VERSION 5.8 ;
BUSBITCHARS "[]" ;
DIVIDERCHAR "/" ;
UNITS
    DATABASE MICRONS 1000 ;
END UNITS

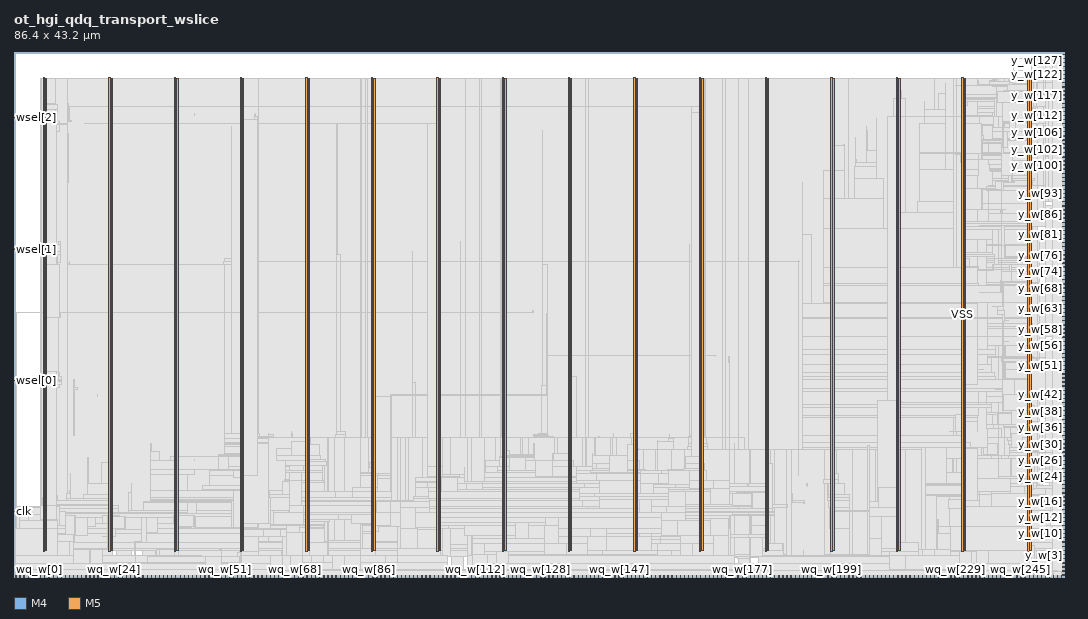
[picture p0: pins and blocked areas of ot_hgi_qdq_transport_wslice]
MACRO ot_hgi_qdq_transport_wslice
  FOREIGN ot_hgi_qdq_transport_wslice 0 0 ;
  CLASS BLOCK ;
  SIZE 86.4 BY 43.2 ;
  PIN clk
    DIRECTION INPUT ;
    USE SIGNAL ;
    PORT
      LAYER M4 ;
        RECT  0 5.376 0.084 5.4 ;
    END
    PORT
      LAYER M4 ;
        RECT  0.06 5.376 0.469 5.4 ;
    END
  END clk
  PIN wq_w[0]
    DIRECTION OUTPUT ;
    USE SIGNAL ;
    PORT
      LAYER M5 ;
        RECT  0.144 0 0.168 0.084 ;
    END
  END wq_w[0]
  PIN wq_w[100]
    DIRECTION OUTPUT ;
    USE SIGNAL ;
    PORT
      LAYER M5 ;
        RECT  33.888 0 33.912 0.084 ;
    END
  END wq_w[100]
  PIN wq_w[101]
    DIRECTION OUTPUT ;
    USE SIGNAL ;
    PORT
      LAYER M5 ;
        RECT  34.224 0 34.248 0.084 ;
    END
  END wq_w[101]
  PIN wq_w[102]
    DIRECTION OUTPUT ;
    USE SIGNAL ;
    PORT
      LAYER M5 ;
        RECT  34.56 0 34.584 0.084 ;
    END
  END wq_w[102]
  PIN wq_w[103]
    DIRECTION OUTPUT ;
    USE SIGNAL ;
    PORT
      LAYER M5 ;
        RECT  34.896 0 34.92 0.084 ;
    END
  END wq_w[103]
  PIN wq_w[104]
    DIRECTION OUTPUT ;
    USE SIGNAL ;
    PORT
      LAYER M5 ;
        RECT  35.28 0 35.304 0.084 ;
    END
  END wq_w[104]
  PIN wq_w[105]
    DIRECTION OUTPUT ;
    USE SIGNAL ;
    PORT
      LAYER M5 ;
        RECT  35.616 0 35.64 0.084 ;
    END
  END wq_w[105]
  PIN wq_w[106]
    DIRECTION OUTPUT ;
    USE SIGNAL ;
    PORT
      LAYER M5 ;
        RECT  35.952 0 35.976 0.084 ;
    END
  END wq_w[106]
  PIN wq_w[107]
    DIRECTION OUTPUT ;
    USE SIGNAL ;
    PORT
      LAYER M5 ;
        RECT  36.288 0 36.312 0.084 ;
    END
  END wq_w[107]
  PIN wq_w[108]
    DIRECTION OUTPUT ;
    USE SIGNAL ;
    PORT
      LAYER M5 ;
        RECT  36.624 0 36.648 0.084 ;
    END
  END wq_w[108]
  PIN wq_w[109]
    DIRECTION OUTPUT ;
    USE SIGNAL ;
    PORT
      LAYER M5 ;
        RECT  36.96 0 36.984 0.084 ;
    END
  END wq_w[109]
  PIN wq_w[10]
    DIRECTION OUTPUT ;
    USE SIGNAL ;
    PORT
      LAYER M5 ;
        RECT  3.552 0 3.576 0.084 ;
    END
  END wq_w[10]
  PIN wq_w[110]
    DIRECTION OUTPUT ;
    USE SIGNAL ;
    PORT
      LAYER M5 ;
        RECT  37.296 0 37.32 0.084 ;
    END
  END wq_w[110]
  PIN wq_w[111]
    DIRECTION OUTPUT ;
    USE SIGNAL ;
    PORT
      LAYER M5 ;
        RECT  37.632 0 37.656 0.084 ;
    END
  END wq_w[111]
  PIN wq_w[112]
    DIRECTION OUTPUT ;
    USE SIGNAL ;
    PORT
      LAYER M5 ;
        RECT  37.968 0 37.992 0.084 ;
    END
  END wq_w[112]
  PIN wq_w[113]
    DIRECTION OUTPUT ;
    USE SIGNAL ;
    PORT
      LAYER M5 ;
        RECT  38.304 0 38.328 0.084 ;
    END
  END wq_w[113]
  PIN wq_w[114]
    DIRECTION OUTPUT ;
    USE SIGNAL ;
    PORT
      LAYER M5 ;
        RECT  38.64 0 38.664 0.084 ;
    END
  END wq_w[114]
  PIN wq_w[115]
    DIRECTION OUTPUT ;
    USE SIGNAL ;
    PORT
      LAYER M5 ;
        RECT  38.976 0 39 0.084 ;
    END
  END wq_w[115]
  PIN wq_w[116]
    DIRECTION OUTPUT ;
    USE SIGNAL ;
    PORT
      LAYER M5 ;
        RECT  39.312 0 39.336 0.084 ;
    END
  END wq_w[116]
  PIN wq_w[117]
    DIRECTION OUTPUT ;
    USE SIGNAL ;
    PORT
      LAYER M5 ;
        RECT  39.648 0 39.672 0.084 ;
    END
  END wq_w[117]
  PIN wq_w[118]
    DIRECTION OUTPUT ;
    USE SIGNAL ;
    PORT
      LAYER M5 ;
        RECT  39.984 0 40.008 0.084 ;
    END
  END wq_w[118]
  PIN wq_w[119]
    DIRECTION OUTPUT ;
    USE SIGNAL ;
    PORT
      LAYER M5 ;
        RECT  40.32 0 40.344 0.084 ;
    END
  END wq_w[119]
  PIN wq_w[11]
    DIRECTION OUTPUT ;
    USE SIGNAL ;
    PORT
      LAYER M5 ;
        RECT  3.888 0 3.912 0.084 ;
    END
  END wq_w[11]
  PIN wq_w[120]
    DIRECTION OUTPUT ;
    USE SIGNAL ;
    PORT
      LAYER M5 ;
        RECT  40.656 0 40.68 0.084 ;
    END
  END wq_w[120]
  PIN wq_w[121]
    DIRECTION OUTPUT ;
    USE SIGNAL ;
    PORT
      LAYER M5 ;
        RECT  40.992 0 41.016 0.084 ;
    END
  END wq_w[121]
  PIN wq_w[122]
    DIRECTION OUTPUT ;
    USE SIGNAL ;
    PORT
      LAYER M5 ;
        RECT  41.328 0 41.352 0.084 ;
    END
  END wq_w[122]
  PIN wq_w[123]
    DIRECTION OUTPUT ;
    USE SIGNAL ;
    PORT
      LAYER M5 ;
        RECT  41.664 0 41.688 0.084 ;
    END
  END wq_w[123]
  PIN wq_w[124]
    DIRECTION OUTPUT ;
    USE SIGNAL ;
    PORT
      LAYER M5 ;
        RECT  42 0 42.024 0.084 ;
    END
  END wq_w[124]
  PIN wq_w[125]
    DIRECTION OUTPUT ;
    USE SIGNAL ;
    PORT
      LAYER M5 ;
        RECT  42.336 0 42.36 0.084 ;
    END
  END wq_w[125]
  PIN wq_w[126]
    DIRECTION OUTPUT ;
    USE SIGNAL ;
    PORT
      LAYER M5 ;
        RECT  42.672 0 42.696 0.084 ;
    END
  END wq_w[126]
  PIN wq_w[127]
    DIRECTION OUTPUT ;
    USE SIGNAL ;
    PORT
      LAYER M5 ;
        RECT  43.008 0 43.032 0.084 ;
    END
  END wq_w[127]
  PIN wq_w[128]
    DIRECTION OUTPUT ;
    USE SIGNAL ;
    PORT
      LAYER M5 ;
        RECT  43.344 0 43.368 0.084 ;
    END
  END wq_w[128]
  PIN wq_w[129]
    DIRECTION OUTPUT ;
    USE SIGNAL ;
    PORT
      LAYER M5 ;
        RECT  43.68 0 43.704 0.084 ;
    END
  END wq_w[129]
  PIN wq_w[12]
    DIRECTION OUTPUT ;
    USE SIGNAL ;
    PORT
      LAYER M5 ;
        RECT  4.224 0 4.248 0.084 ;
    END
  END wq_w[12]
  PIN wq_w[130]
    DIRECTION OUTPUT ;
    USE SIGNAL ;
    PORT
      LAYER M5 ;
        RECT  44.016 0 44.04 0.084 ;
    END
  END wq_w[130]
  PIN wq_w[131]
    DIRECTION OUTPUT ;
    USE SIGNAL ;
    PORT
      LAYER M5 ;
        RECT  44.352 0 44.376 0.084 ;
    END
  END wq_w[131]
  PIN wq_w[132]
    DIRECTION OUTPUT ;
    USE SIGNAL ;
    PORT
      LAYER M5 ;
        RECT  44.688 0 44.712 0.084 ;
    END
  END wq_w[132]
  PIN wq_w[133]
    DIRECTION OUTPUT ;
    USE SIGNAL ;
    PORT
      LAYER M5 ;
        RECT  45.024 0 45.048 0.084 ;
    END
  END wq_w[133]
  PIN wq_w[134]
    DIRECTION OUTPUT ;
    USE SIGNAL ;
    PORT
      LAYER M5 ;
        RECT  45.36 0 45.384 0.084 ;
    END
  END wq_w[134]
  PIN wq_w[135]
    DIRECTION OUTPUT ;
    USE SIGNAL ;
    PORT
      LAYER M5 ;
        RECT  45.696 0 45.72 0.084 ;
    END
  END wq_w[135]
  PIN wq_w[136]
    DIRECTION OUTPUT ;
    USE SIGNAL ;
    PORT
      LAYER M5 ;
        RECT  46.08 0 46.104 0.084 ;
    END
  END wq_w[136]
  PIN wq_w[137]
    DIRECTION OUTPUT ;
    USE SIGNAL ;
    PORT
      LAYER M5 ;
        RECT  46.416 0 46.44 0.084 ;
    END
  END wq_w[137]
  PIN wq_w[138]
    DIRECTION OUTPUT ;
    USE SIGNAL ;
    PORT
      LAYER M5 ;
        RECT  46.752 0 46.776 0.084 ;
    END
  END wq_w[138]
  PIN wq_w[139]
    DIRECTION OUTPUT ;
    USE SIGNAL ;
    PORT
      LAYER M5 ;
        RECT  47.088 0 47.112 0.084 ;
    END
  END wq_w[139]
  PIN wq_w[13]
    DIRECTION OUTPUT ;
    USE SIGNAL ;
    PORT
      LAYER M5 ;
        RECT  4.56 0 4.584 0.084 ;
    END
  END wq_w[13]
  PIN wq_w[140]
    DIRECTION OUTPUT ;
    USE SIGNAL ;
    PORT
      LAYER M5 ;
        RECT  47.424 0 47.448 0.084 ;
    END
  END wq_w[140]
  PIN wq_w[141]
    DIRECTION OUTPUT ;
    USE SIGNAL ;
    PORT
      LAYER M5 ;
        RECT  47.76 0 47.784 0.084 ;
    END
  END wq_w[141]
  PIN wq_w[142]
    DIRECTION OUTPUT ;
    USE SIGNAL ;
    PORT
      LAYER M5 ;
        RECT  48.096 0 48.12 0.084 ;
    END
  END wq_w[142]
  PIN wq_w[143]
    DIRECTION OUTPUT ;
    USE SIGNAL ;
    PORT
      LAYER M5 ;
        RECT  48.432 0 48.456 0.084 ;
    END
  END wq_w[143]
  PIN wq_w[144]
    DIRECTION OUTPUT ;
    USE SIGNAL ;
    PORT
      LAYER M5 ;
        RECT  48.768 0 48.792 0.084 ;
    END
  END wq_w[144]
  PIN wq_w[145]
    DIRECTION OUTPUT ;
    USE SIGNAL ;
    PORT
      LAYER M5 ;
        RECT  49.104 0 49.128 0.084 ;
    END
  END wq_w[145]
  PIN wq_w[146]
    DIRECTION OUTPUT ;
    USE SIGNAL ;
    PORT
      LAYER M5 ;
        RECT  49.44 0 49.464 0.084 ;
    END
  END wq_w[146]
  PIN wq_w[147]
    DIRECTION OUTPUT ;
    USE SIGNAL ;
    PORT
      LAYER M5 ;
        RECT  49.776 0 49.8 0.084 ;
    END
  END wq_w[147]
  PIN wq_w[148]
    DIRECTION OUTPUT ;
    USE SIGNAL ;
    PORT
      LAYER M5 ;
        RECT  50.112 0 50.136 0.084 ;
    END
  END wq_w[148]
  PIN wq_w[149]
    DIRECTION OUTPUT ;
    USE SIGNAL ;
    PORT
      LAYER M5 ;
        RECT  50.448 0 50.472 0.084 ;
    END
  END wq_w[149]
  PIN wq_w[14]
    DIRECTION OUTPUT ;
    USE SIGNAL ;
    PORT
      LAYER M5 ;
        RECT  4.896 0 4.92 0.084 ;
    END
  END wq_w[14]
  PIN wq_w[150]
    DIRECTION OUTPUT ;
    USE SIGNAL ;
    PORT
      LAYER M5 ;
        RECT  50.784 0 50.808 0.084 ;
    END
  END wq_w[150]
  PIN wq_w[151]
    DIRECTION OUTPUT ;
    USE SIGNAL ;
    PORT
      LAYER M5 ;
        RECT  51.12 0 51.144 0.084 ;
    END
  END wq_w[151]
  PIN wq_w[152]
    DIRECTION OUTPUT ;
    USE SIGNAL ;
    PORT
      LAYER M5 ;
        RECT  51.456 0 51.48 0.084 ;
    END
  END wq_w[152]
  PIN wq_w[153]
    DIRECTION OUTPUT ;
    USE SIGNAL ;
    PORT
      LAYER M5 ;
        RECT  51.792 0 51.816 0.084 ;
    END
  END wq_w[153]
  PIN wq_w[154]
    DIRECTION OUTPUT ;
    USE SIGNAL ;
    PORT
      LAYER M5 ;
        RECT  52.128 0 52.152 0.084 ;
    END
  END wq_w[154]
  PIN wq_w[155]
    DIRECTION OUTPUT ;
    USE SIGNAL ;
    PORT
      LAYER M5 ;
        RECT  52.464 0 52.488 0.084 ;
    END
  END wq_w[155]
  PIN wq_w[156]
    DIRECTION OUTPUT ;
    USE SIGNAL ;
    PORT
      LAYER M5 ;
        RECT  52.8 0 52.824 0.084 ;
    END
  END wq_w[156]
  PIN wq_w[157]
    DIRECTION OUTPUT ;
    USE SIGNAL ;
    PORT
      LAYER M5 ;
        RECT  53.136 0 53.16 0.084 ;
    END
  END wq_w[157]
  PIN wq_w[158]
    DIRECTION OUTPUT ;
    USE SIGNAL ;
    PORT
      LAYER M5 ;
        RECT  53.472 0 53.496 0.084 ;
    END
  END wq_w[158]
  PIN wq_w[159]
    DIRECTION OUTPUT ;
    USE SIGNAL ;
    PORT
      LAYER M5 ;
        RECT  53.808 0 53.832 0.084 ;
    END
  END wq_w[159]
  PIN wq_w[15]
    DIRECTION OUTPUT ;
    USE SIGNAL ;
    PORT
      LAYER M5 ;
        RECT  5.232 0 5.256 0.084 ;
    END
  END wq_w[15]
  PIN wq_w[160]
    DIRECTION OUTPUT ;
    USE SIGNAL ;
    PORT
      LAYER M5 ;
        RECT  54.144 0 54.168 0.084 ;
    END
  END wq_w[160]
  PIN wq_w[161]
    DIRECTION OUTPUT ;
    USE SIGNAL ;
    PORT
      LAYER M5 ;
        RECT  54.48 0 54.504 0.084 ;
    END
  END wq_w[161]
  PIN wq_w[162]
    DIRECTION OUTPUT ;
    USE SIGNAL ;
    PORT
      LAYER M5 ;
        RECT  54.816 0 54.84 0.084 ;
    END
  END wq_w[162]
  PIN wq_w[163]
    DIRECTION OUTPUT ;
    USE SIGNAL ;
    PORT
      LAYER M5 ;
        RECT  55.152 0 55.176 0.084 ;
    END
  END wq_w[163]
  PIN wq_w[164]
    DIRECTION OUTPUT ;
    USE SIGNAL ;
    PORT
      LAYER M5 ;
        RECT  55.488 0 55.512 0.084 ;
    END
  END wq_w[164]
  PIN wq_w[165]
    DIRECTION OUTPUT ;
    USE SIGNAL ;
    PORT
      LAYER M5 ;
        RECT  55.824 0 55.848 0.084 ;
    END
  END wq_w[165]
  PIN wq_w[166]
    DIRECTION OUTPUT ;
    USE SIGNAL ;
    PORT
      LAYER M5 ;
        RECT  56.16 0 56.184 0.084 ;
    END
  END wq_w[166]
  PIN wq_w[167]
    DIRECTION OUTPUT ;
    USE SIGNAL ;
    PORT
      LAYER M5 ;
        RECT  56.496 0 56.52 0.084 ;
    END
  END wq_w[167]
  PIN wq_w[168]
    DIRECTION OUTPUT ;
    USE SIGNAL ;
    PORT
      LAYER M5 ;
        RECT  56.88 0 56.904 0.084 ;
    END
  END wq_w[168]
  PIN wq_w[169]
    DIRECTION OUTPUT ;
    USE SIGNAL ;
    PORT
      LAYER M5 ;
        RECT  57.216 0 57.24 0.084 ;
    END
  END wq_w[169]
  PIN wq_w[16]
    DIRECTION OUTPUT ;
    USE SIGNAL ;
    PORT
      LAYER M5 ;
        RECT  5.568 0 5.592 0.084 ;
    END
  END wq_w[16]
  PIN wq_w[170]
    DIRECTION OUTPUT ;
    USE SIGNAL ;
    PORT
      LAYER M5 ;
        RECT  57.552 0 57.576 0.084 ;
    END
  END wq_w[170]
  PIN wq_w[171]
    DIRECTION OUTPUT ;
    USE SIGNAL ;
    PORT
      LAYER M5 ;
        RECT  57.888 0 57.912 0.084 ;
    END
  END wq_w[171]
  PIN wq_w[172]
    DIRECTION OUTPUT ;
    USE SIGNAL ;
    PORT
      LAYER M5 ;
        RECT  58.224 0 58.248 0.084 ;
    END
  END wq_w[172]
  PIN wq_w[173]
    DIRECTION OUTPUT ;
    USE SIGNAL ;
    PORT
      LAYER M5 ;
        RECT  58.56 0 58.584 0.084 ;
    END
  END wq_w[173]
  PIN wq_w[174]
    DIRECTION OUTPUT ;
    USE SIGNAL ;
    PORT
      LAYER M5 ;
        RECT  58.896 0 58.92 0.084 ;
    END
  END wq_w[174]
  PIN wq_w[175]
    DIRECTION OUTPUT ;
    USE SIGNAL ;
    PORT
      LAYER M5 ;
        RECT  59.232 0 59.256 0.084 ;
    END
  END wq_w[175]
  PIN wq_w[176]
    DIRECTION OUTPUT ;
    USE SIGNAL ;
    PORT
      LAYER M5 ;
        RECT  59.568 0 59.592 0.084 ;
    END
  END wq_w[176]
  PIN wq_w[177]
    DIRECTION OUTPUT ;
    USE SIGNAL ;
    PORT
      LAYER M5 ;
        RECT  59.904 0 59.928 0.084 ;
    END
  END wq_w[177]
  PIN wq_w[178]
    DIRECTION OUTPUT ;
    USE SIGNAL ;
    PORT
      LAYER M5 ;
        RECT  60.24 0 60.264 0.084 ;
    END
  END wq_w[178]
  PIN wq_w[179]
    DIRECTION OUTPUT ;
    USE SIGNAL ;
    PORT
      LAYER M5 ;
        RECT  60.576 0 60.6 0.084 ;
    END
  END wq_w[179]
  PIN wq_w[17]
    DIRECTION OUTPUT ;
    USE SIGNAL ;
    PORT
      LAYER M5 ;
        RECT  5.904 0 5.928 0.084 ;
    END
  END wq_w[17]
  PIN wq_w[180]
    DIRECTION OUTPUT ;
    USE SIGNAL ;
    PORT
      LAYER M5 ;
        RECT  60.912 0 60.936 0.084 ;
    END
  END wq_w[180]
  PIN wq_w[181]
    DIRECTION OUTPUT ;
    USE SIGNAL ;
    PORT
      LAYER M5 ;
        RECT  61.248 0 61.272 0.084 ;
    END
  END wq_w[181]
  PIN wq_w[182]
    DIRECTION OUTPUT ;
    USE SIGNAL ;
    PORT
      LAYER M5 ;
        RECT  61.584 0 61.608 0.084 ;
    END
  END wq_w[182]
  PIN wq_w[183]
    DIRECTION OUTPUT ;
    USE SIGNAL ;
    PORT
      LAYER M5 ;
        RECT  61.92 0 61.944 0.084 ;
    END
  END wq_w[183]
  PIN wq_w[184]
    DIRECTION OUTPUT ;
    USE SIGNAL ;
    PORT
      LAYER M5 ;
        RECT  62.256 0 62.28 0.084 ;
    END
  END wq_w[184]
  PIN wq_w[185]
    DIRECTION OUTPUT ;
    USE SIGNAL ;
    PORT
      LAYER M5 ;
        RECT  62.592 0 62.616 0.084 ;
    END
  END wq_w[185]
  PIN wq_w[186]
    DIRECTION OUTPUT ;
    USE SIGNAL ;
    PORT
      LAYER M5 ;
        RECT  62.928 0 62.952 0.084 ;
    END
  END wq_w[186]
  PIN wq_w[187]
    DIRECTION OUTPUT ;
    USE SIGNAL ;
    PORT
      LAYER M5 ;
        RECT  63.264 0 63.288 0.084 ;
    END
  END wq_w[187]
  PIN wq_w[188]
    DIRECTION OUTPUT ;
    USE SIGNAL ;
    PORT
      LAYER M5 ;
        RECT  63.6 0 63.624 0.084 ;
    END
  END wq_w[188]
  PIN wq_w[189]
    DIRECTION OUTPUT ;
    USE SIGNAL ;
    PORT
      LAYER M5 ;
        RECT  63.936 0 63.96 0.084 ;
    END
  END wq_w[189]
  PIN wq_w[18]
    DIRECTION OUTPUT ;
    USE SIGNAL ;
    PORT
      LAYER M5 ;
        RECT  6.24 0 6.264 0.084 ;
    END
  END wq_w[18]
  PIN wq_w[190]
    DIRECTION OUTPUT ;
    USE SIGNAL ;
    PORT
      LAYER M5 ;
        RECT  64.272 0 64.296 0.084 ;
    END
  END wq_w[190]
  PIN wq_w[191]
    DIRECTION OUTPUT ;
    USE SIGNAL ;
    PORT
      LAYER M5 ;
        RECT  64.608 0 64.632 0.084 ;
    END
  END wq_w[191]
  PIN wq_w[192]
    DIRECTION OUTPUT ;
    USE SIGNAL ;
    PORT
      LAYER M5 ;
        RECT  64.944 0 64.968 0.084 ;
    END
  END wq_w[192]
  PIN wq_w[193]
    DIRECTION OUTPUT ;
    USE SIGNAL ;
    PORT
      LAYER M5 ;
        RECT  65.28 0 65.304 0.084 ;
    END
  END wq_w[193]
  PIN wq_w[194]
    DIRECTION OUTPUT ;
    USE SIGNAL ;
    PORT
      LAYER M5 ;
        RECT  65.616 0 65.64 0.084 ;
    END
  END wq_w[194]
  PIN wq_w[195]
    DIRECTION OUTPUT ;
    USE SIGNAL ;
    PORT
      LAYER M5 ;
        RECT  65.952 0 65.976 0.084 ;
    END
  END wq_w[195]
  PIN wq_w[196]
    DIRECTION OUTPUT ;
    USE SIGNAL ;
    PORT
      LAYER M5 ;
        RECT  66.288 0 66.312 0.084 ;
    END
  END wq_w[196]
  PIN wq_w[197]
    DIRECTION OUTPUT ;
    USE SIGNAL ;
    PORT
      LAYER M5 ;
        RECT  66.624 0 66.648 0.084 ;
    END
  END wq_w[197]
  PIN wq_w[198]
    DIRECTION OUTPUT ;
    USE SIGNAL ;
    PORT
      LAYER M5 ;
        RECT  66.96 0 66.984 0.084 ;
    END
  END wq_w[198]
  PIN wq_w[199]
    DIRECTION OUTPUT ;
    USE SIGNAL ;
    PORT
      LAYER M5 ;
        RECT  67.296 0 67.32 0.084 ;
    END
  END wq_w[199]
  PIN wq_w[19]
    DIRECTION OUTPUT ;
    USE SIGNAL ;
    PORT
      LAYER M5 ;
        RECT  6.576 0 6.6 0.084 ;
    END
  END wq_w[19]
  PIN wq_w[1]
    DIRECTION OUTPUT ;
    USE SIGNAL ;
    PORT
      LAYER M5 ;
        RECT  0.48 0 0.504 0.084 ;
    END
  END wq_w[1]
  PIN wq_w[200]
    DIRECTION OUTPUT ;
    USE SIGNAL ;
    PORT
      LAYER M5 ;
        RECT  67.68 0 67.704 0.084 ;
    END
  END wq_w[200]
  PIN wq_w[201]
    DIRECTION OUTPUT ;
    USE SIGNAL ;
    PORT
      LAYER M5 ;
        RECT  68.016 0 68.04 0.084 ;
    END
  END wq_w[201]
  PIN wq_w[202]
    DIRECTION OUTPUT ;
    USE SIGNAL ;
    PORT
      LAYER M5 ;
        RECT  68.352 0 68.376 0.084 ;
    END
  END wq_w[202]
  PIN wq_w[203]
    DIRECTION OUTPUT ;
    USE SIGNAL ;
    PORT
      LAYER M5 ;
        RECT  68.688 0 68.712 0.084 ;
    END
  END wq_w[203]
  PIN wq_w[204]
    DIRECTION OUTPUT ;
    USE SIGNAL ;
    PORT
      LAYER M5 ;
        RECT  69.024 0 69.048 0.084 ;
    END
  END wq_w[204]
  PIN wq_w[205]
    DIRECTION OUTPUT ;
    USE SIGNAL ;
    PORT
      LAYER M5 ;
        RECT  69.36 0 69.384 0.084 ;
    END
  END wq_w[205]
  PIN wq_w[206]
    DIRECTION OUTPUT ;
    USE SIGNAL ;
    PORT
      LAYER M5 ;
        RECT  69.696 0 69.72 0.084 ;
    END
  END wq_w[206]
  PIN wq_w[207]
    DIRECTION OUTPUT ;
    USE SIGNAL ;
    PORT
      LAYER M5 ;
        RECT  70.032 0 70.056 0.084 ;
    END
  END wq_w[207]
  PIN wq_w[208]
    DIRECTION OUTPUT ;
    USE SIGNAL ;
    PORT
      LAYER M5 ;
        RECT  70.368 0 70.392 0.084 ;
    END
  END wq_w[208]
  PIN wq_w[209]
    DIRECTION OUTPUT ;
    USE SIGNAL ;
    PORT
      LAYER M5 ;
        RECT  70.704 0 70.728 0.084 ;
    END
  END wq_w[209]
  PIN wq_w[20]
    DIRECTION OUTPUT ;
    USE SIGNAL ;
    PORT
      LAYER M5 ;
        RECT  6.912 0 6.936 0.084 ;
    END
  END wq_w[20]
  PIN wq_w[210]
    DIRECTION OUTPUT ;
    USE SIGNAL ;
    PORT
      LAYER M5 ;
        RECT  71.04 0 71.064 0.084 ;
    END
  END wq_w[210]
  PIN wq_w[211]
    DIRECTION OUTPUT ;
    USE SIGNAL ;
    PORT
      LAYER M5 ;
        RECT  71.376 0 71.4 0.084 ;
    END
  END wq_w[211]
  PIN wq_w[212]
    DIRECTION OUTPUT ;
    USE SIGNAL ;
    PORT
      LAYER M5 ;
        RECT  71.712 0 71.736 0.084 ;
    END
  END wq_w[212]
  PIN wq_w[213]
    DIRECTION OUTPUT ;
    USE SIGNAL ;
    PORT
      LAYER M5 ;
        RECT  72.048 0 72.072 0.084 ;
    END
  END wq_w[213]
  PIN wq_w[214]
    DIRECTION OUTPUT ;
    USE SIGNAL ;
    PORT
      LAYER M5 ;
        RECT  72.384 0 72.408 0.084 ;
    END
  END wq_w[214]
  PIN wq_w[215]
    DIRECTION OUTPUT ;
    USE SIGNAL ;
    PORT
      LAYER M5 ;
        RECT  72.72 0 72.744 0.084 ;
    END
  END wq_w[215]
  PIN wq_w[216]
    DIRECTION OUTPUT ;
    USE SIGNAL ;
    PORT
      LAYER M5 ;
        RECT  73.056 0 73.08 0.084 ;
    END
  END wq_w[216]
  PIN wq_w[217]
    DIRECTION OUTPUT ;
    USE SIGNAL ;
    PORT
      LAYER M5 ;
        RECT  73.392 0 73.416 0.084 ;
    END
  END wq_w[217]
  PIN wq_w[218]
    DIRECTION OUTPUT ;
    USE SIGNAL ;
    PORT
      LAYER M5 ;
        RECT  73.728 0 73.752 0.084 ;
    END
  END wq_w[218]
  PIN wq_w[219]
    DIRECTION OUTPUT ;
    USE SIGNAL ;
    PORT
      LAYER M5 ;
        RECT  74.064 0 74.088 0.084 ;
    END
  END wq_w[219]
  PIN wq_w[21]
    DIRECTION OUTPUT ;
    USE SIGNAL ;
    PORT
      LAYER M5 ;
        RECT  7.248 0 7.272 0.084 ;
    END
  END wq_w[21]
  PIN wq_w[220]
    DIRECTION OUTPUT ;
    USE SIGNAL ;
    PORT
      LAYER M5 ;
        RECT  74.4 0 74.424 0.084 ;
    END
  END wq_w[220]
  PIN wq_w[221]
    DIRECTION OUTPUT ;
    USE SIGNAL ;
    PORT
      LAYER M5 ;
        RECT  74.736 0 74.76 0.084 ;
    END
  END wq_w[221]
  PIN wq_w[222]
    DIRECTION OUTPUT ;
    USE SIGNAL ;
    PORT
      LAYER M5 ;
        RECT  75.072 0 75.096 0.084 ;
    END
  END wq_w[222]
  PIN wq_w[223]
    DIRECTION OUTPUT ;
    USE SIGNAL ;
    PORT
      LAYER M5 ;
        RECT  75.408 0 75.432 0.084 ;
    END
  END wq_w[223]
  PIN wq_w[224]
    DIRECTION OUTPUT ;
    USE SIGNAL ;
    PORT
      LAYER M5 ;
        RECT  75.744 0 75.768 0.084 ;
    END
  END wq_w[224]
  PIN wq_w[225]
    DIRECTION OUTPUT ;
    USE SIGNAL ;
    PORT
      LAYER M5 ;
        RECT  76.08 0 76.104 0.084 ;
    END
  END wq_w[225]
  PIN wq_w[226]
    DIRECTION OUTPUT ;
    USE SIGNAL ;
    PORT
      LAYER M5 ;
        RECT  76.416 0 76.44 0.084 ;
    END
  END wq_w[226]
  PIN wq_w[227]
    DIRECTION OUTPUT ;
    USE SIGNAL ;
    PORT
      LAYER M5 ;
        RECT  76.752 0 76.776 0.084 ;
    END
  END wq_w[227]
  PIN wq_w[228]
    DIRECTION OUTPUT ;
    USE SIGNAL ;
    PORT
      LAYER M5 ;
        RECT  77.088 0 77.112 0.084 ;
    END
  END wq_w[228]
  PIN wq_w[229]
    DIRECTION OUTPUT ;
    USE SIGNAL ;
    PORT
      LAYER M5 ;
        RECT  77.424 0 77.448 0.084 ;
    END
  END wq_w[229]
  PIN wq_w[22]
    DIRECTION OUTPUT ;
    USE SIGNAL ;
    PORT
      LAYER M5 ;
        RECT  7.584 0 7.608 0.084 ;
    END
  END wq_w[22]
  PIN wq_w[230]
    DIRECTION OUTPUT ;
    USE SIGNAL ;
    PORT
      LAYER M5 ;
        RECT  77.76 0 77.784 0.084 ;
    END
  END wq_w[230]
  PIN wq_w[231]
    DIRECTION OUTPUT ;
    USE SIGNAL ;
    PORT
      LAYER M5 ;
        RECT  78.096 0 78.12 0.084 ;
    END
  END wq_w[231]
  PIN wq_w[232]
    DIRECTION OUTPUT ;
    USE SIGNAL ;
    PORT
      LAYER M5 ;
        RECT  78.48 0 78.504 0.084 ;
    END
  END wq_w[232]
  PIN wq_w[233]
    DIRECTION OUTPUT ;
    USE SIGNAL ;
    PORT
      LAYER M5 ;
        RECT  78.816 0 78.84 0.084 ;
    END
  END wq_w[233]
  PIN wq_w[234]
    DIRECTION OUTPUT ;
    USE SIGNAL ;
    PORT
      LAYER M5 ;
        RECT  79.152 0 79.176 0.084 ;
    END
  END wq_w[234]
  PIN wq_w[235]
    DIRECTION OUTPUT ;
    USE SIGNAL ;
    PORT
      LAYER M5 ;
        RECT  79.488 0 79.512 0.084 ;
    END
  END wq_w[235]
  PIN wq_w[236]
    DIRECTION OUTPUT ;
    USE SIGNAL ;
    PORT
      LAYER M5 ;
        RECT  79.824 0 79.848 0.084 ;
    END
  END wq_w[236]
  PIN wq_w[237]
    DIRECTION OUTPUT ;
    USE SIGNAL ;
    PORT
      LAYER M5 ;
        RECT  80.16 0 80.184 0.084 ;
    END
  END wq_w[237]
  PIN wq_w[238]
    DIRECTION OUTPUT ;
    USE SIGNAL ;
    PORT
      LAYER M5 ;
        RECT  80.496 0 80.52 0.084 ;
    END
  END wq_w[238]
  PIN wq_w[239]
    DIRECTION OUTPUT ;
    USE SIGNAL ;
    PORT
      LAYER M5 ;
        RECT  80.832 0 80.856 0.084 ;
    END
  END wq_w[239]
  PIN wq_w[23]
    DIRECTION OUTPUT ;
    USE SIGNAL ;
    PORT
      LAYER M5 ;
        RECT  7.92 0 7.944 0.084 ;
    END
  END wq_w[23]
  PIN wq_w[240]
    DIRECTION OUTPUT ;
    USE SIGNAL ;
    PORT
      LAYER M5 ;
        RECT  81.168 0 81.192 0.084 ;
    END
  END wq_w[240]
  PIN wq_w[241]
    DIRECTION OUTPUT ;
    USE SIGNAL ;
    PORT
      LAYER M5 ;
        RECT  81.504 0 81.528 0.084 ;
    END
  END wq_w[241]
  PIN wq_w[242]
    DIRECTION OUTPUT ;
    USE SIGNAL ;
    PORT
      LAYER M5 ;
        RECT  81.84 0 81.864 0.084 ;
    END
  END wq_w[242]
  PIN wq_w[243]
    DIRECTION OUTPUT ;
    USE SIGNAL ;
    PORT
      LAYER M5 ;
        RECT  82.176 0 82.2 0.084 ;
    END
  END wq_w[243]
  PIN wq_w[244]
    DIRECTION OUTPUT ;
    USE SIGNAL ;
    PORT
      LAYER M5 ;
        RECT  82.512 0 82.536 0.084 ;
    END
  END wq_w[244]
  PIN wq_w[245]
    DIRECTION OUTPUT ;
    USE SIGNAL ;
    PORT
      LAYER M5 ;
        RECT  82.848 0 82.872 0.084 ;
    END
  END wq_w[245]
  PIN wq_w[246]
    DIRECTION OUTPUT ;
    USE SIGNAL ;
    PORT
      LAYER M5 ;
        RECT  83.184 0 83.208 0.084 ;
    END
  END wq_w[246]
  PIN wq_w[247]
    DIRECTION OUTPUT ;
    USE SIGNAL ;
    PORT
      LAYER M5 ;
        RECT  83.52 0 83.544 0.084 ;
    END
  END wq_w[247]
  PIN wq_w[248]
    DIRECTION OUTPUT ;
    USE SIGNAL ;
    PORT
      LAYER M5 ;
        RECT  83.856 0 83.88 0.084 ;
    END
  END wq_w[248]
  PIN wq_w[249]
    DIRECTION OUTPUT ;
    USE SIGNAL ;
    PORT
      LAYER M5 ;
        RECT  84.192 0 84.216 0.084 ;
    END
  END wq_w[249]
  PIN wq_w[24]
    DIRECTION OUTPUT ;
    USE SIGNAL ;
    PORT
      LAYER M5 ;
        RECT  8.256 0 8.28 0.084 ;
    END
  END wq_w[24]
  PIN wq_w[250]
    DIRECTION OUTPUT ;
    USE SIGNAL ;
    PORT
      LAYER M5 ;
        RECT  84.528 0 84.552 0.084 ;
    END
  END wq_w[250]
  PIN wq_w[251]
    DIRECTION OUTPUT ;
    USE SIGNAL ;
    PORT
      LAYER M5 ;
        RECT  84.864 0 84.888 0.084 ;
    END
  END wq_w[251]
  PIN wq_w[252]
    DIRECTION OUTPUT ;
    USE SIGNAL ;
    PORT
      LAYER M5 ;
        RECT  85.2 0 85.224 0.084 ;
    END
  END wq_w[252]
  PIN wq_w[253]
    DIRECTION OUTPUT ;
    USE SIGNAL ;
    PORT
      LAYER M5 ;
        RECT  85.536 0 85.56 0.084 ;
    END
  END wq_w[253]
  PIN wq_w[254]
    DIRECTION OUTPUT ;
    USE SIGNAL ;
    PORT
      LAYER M5 ;
        RECT  85.872 0 85.896 0.084 ;
    END
  END wq_w[254]
  PIN wq_w[255]
    DIRECTION OUTPUT ;
    USE SIGNAL ;
    PORT
      LAYER M5 ;
        RECT  86.208 0 86.232 0.084 ;
    END
  END wq_w[255]
  PIN wq_w[25]
    DIRECTION OUTPUT ;
    USE SIGNAL ;
    PORT
      LAYER M5 ;
        RECT  8.592 0 8.616 0.084 ;
    END
  END wq_w[25]
  PIN wq_w[26]
    DIRECTION OUTPUT ;
    USE SIGNAL ;
    PORT
      LAYER M5 ;
        RECT  8.928 0 8.952 0.084 ;
    END
  END wq_w[26]
  PIN wq_w[27]
    DIRECTION OUTPUT ;
    USE SIGNAL ;
    PORT
      LAYER M5 ;
        RECT  9.264 0 9.288 0.084 ;
    END
  END wq_w[27]
  PIN wq_w[28]
    DIRECTION OUTPUT ;
    USE SIGNAL ;
    PORT
      LAYER M5 ;
        RECT  9.6 0 9.624 0.084 ;
    END
  END wq_w[28]
  PIN wq_w[29]
    DIRECTION OUTPUT ;
    USE SIGNAL ;
    PORT
      LAYER M5 ;
        RECT  9.936 0 9.96 0.084 ;
    END
  END wq_w[29]
  PIN wq_w[2]
    DIRECTION OUTPUT ;
    USE SIGNAL ;
    PORT
      LAYER M5 ;
        RECT  0.816 0 0.84 0.084 ;
    END
  END wq_w[2]
  PIN wq_w[30]
    DIRECTION OUTPUT ;
    USE SIGNAL ;
    PORT
      LAYER M5 ;
        RECT  10.272 0 10.296 0.084 ;
    END
  END wq_w[30]
  PIN wq_w[31]
    DIRECTION OUTPUT ;
    USE SIGNAL ;
    PORT
      LAYER M5 ;
        RECT  10.608 0 10.632 0.084 ;
    END
  END wq_w[31]
  PIN wq_w[32]
    DIRECTION OUTPUT ;
    USE SIGNAL ;
    PORT
      LAYER M5 ;
        RECT  10.944 0 10.968 0.084 ;
    END
  END wq_w[32]
  PIN wq_w[33]
    DIRECTION OUTPUT ;
    USE SIGNAL ;
    PORT
      LAYER M5 ;
        RECT  11.28 0 11.304 0.084 ;
    END
  END wq_w[33]
  PIN wq_w[34]
    DIRECTION OUTPUT ;
    USE SIGNAL ;
    PORT
      LAYER M5 ;
        RECT  11.616 0 11.64 0.084 ;
    END
  END wq_w[34]
  PIN wq_w[35]
    DIRECTION OUTPUT ;
    USE SIGNAL ;
    PORT
      LAYER M5 ;
        RECT  11.952 0 11.976 0.084 ;
    END
  END wq_w[35]
  PIN wq_w[36]
    DIRECTION OUTPUT ;
    USE SIGNAL ;
    PORT
      LAYER M5 ;
        RECT  12.288 0 12.312 0.084 ;
    END
  END wq_w[36]
  PIN wq_w[37]
    DIRECTION OUTPUT ;
    USE SIGNAL ;
    PORT
      LAYER M5 ;
        RECT  12.624 0 12.648 0.084 ;
    END
  END wq_w[37]
  PIN wq_w[38]
    DIRECTION OUTPUT ;
    USE SIGNAL ;
    PORT
      LAYER M5 ;
        RECT  12.96 0 12.984 0.084 ;
    END
  END wq_w[38]
  PIN wq_w[39]
    DIRECTION OUTPUT ;
    USE SIGNAL ;
    PORT
      LAYER M5 ;
        RECT  13.296 0 13.32 0.084 ;
    END
  END wq_w[39]
  PIN wq_w[3]
    DIRECTION OUTPUT ;
    USE SIGNAL ;
    PORT
      LAYER M5 ;
        RECT  1.152 0 1.176 0.084 ;
    END
  END wq_w[3]
  PIN wq_w[40]
    DIRECTION OUTPUT ;
    USE SIGNAL ;
    PORT
      LAYER M5 ;
        RECT  13.68 0 13.704 0.084 ;
    END
  END wq_w[40]
  PIN wq_w[41]
    DIRECTION OUTPUT ;
    USE SIGNAL ;
    PORT
      LAYER M5 ;
        RECT  14.016 0 14.04 0.084 ;
    END
  END wq_w[41]
  PIN wq_w[42]
    DIRECTION OUTPUT ;
    USE SIGNAL ;
    PORT
      LAYER M5 ;
        RECT  14.352 0 14.376 0.084 ;
    END
  END wq_w[42]
  PIN wq_w[43]
    DIRECTION OUTPUT ;
    USE SIGNAL ;
    PORT
      LAYER M5 ;
        RECT  14.688 0 14.712 0.084 ;
    END
  END wq_w[43]
  PIN wq_w[44]
    DIRECTION OUTPUT ;
    USE SIGNAL ;
    PORT
      LAYER M5 ;
        RECT  15.024 0 15.048 0.084 ;
    END
  END wq_w[44]
  PIN wq_w[45]
    DIRECTION OUTPUT ;
    USE SIGNAL ;
    PORT
      LAYER M5 ;
        RECT  15.36 0 15.384 0.084 ;
    END
  END wq_w[45]
  PIN wq_w[46]
    DIRECTION OUTPUT ;
    USE SIGNAL ;
    PORT
      LAYER M5 ;
        RECT  15.696 0 15.72 0.084 ;
    END
  END wq_w[46]
  PIN wq_w[47]
    DIRECTION OUTPUT ;
    USE SIGNAL ;
    PORT
      LAYER M5 ;
        RECT  16.032 0 16.056 0.084 ;
    END
  END wq_w[47]
  PIN wq_w[48]
    DIRECTION OUTPUT ;
    USE SIGNAL ;
    PORT
      LAYER M5 ;
        RECT  16.368 0 16.392 0.084 ;
    END
  END wq_w[48]
  PIN wq_w[49]
    DIRECTION OUTPUT ;
    USE SIGNAL ;
    PORT
      LAYER M5 ;
        RECT  16.704 0 16.728 0.084 ;
    END
  END wq_w[49]
  PIN wq_w[4]
    DIRECTION OUTPUT ;
    USE SIGNAL ;
    PORT
      LAYER M5 ;
        RECT  1.488 0 1.512 0.084 ;
    END
  END wq_w[4]
  PIN wq_w[50]
    DIRECTION OUTPUT ;
    USE SIGNAL ;
    PORT
      LAYER M5 ;
        RECT  17.04 0 17.064 0.084 ;
    END
  END wq_w[50]
  PIN wq_w[51]
    DIRECTION OUTPUT ;
    USE SIGNAL ;
    PORT
      LAYER M5 ;
        RECT  17.376 0 17.4 0.084 ;
    END
  END wq_w[51]
  PIN wq_w[52]
    DIRECTION OUTPUT ;
    USE SIGNAL ;
    PORT
      LAYER M5 ;
        RECT  17.712 0 17.736 0.084 ;
    END
  END wq_w[52]
  PIN wq_w[53]
    DIRECTION OUTPUT ;
    USE SIGNAL ;
    PORT
      LAYER M5 ;
        RECT  18.048 0 18.072 0.084 ;
    END
  END wq_w[53]
  PIN wq_w[54]
    DIRECTION OUTPUT ;
    USE SIGNAL ;
    PORT
      LAYER M5 ;
        RECT  18.384 0 18.408 0.084 ;
    END
  END wq_w[54]
  PIN wq_w[55]
    DIRECTION OUTPUT ;
    USE SIGNAL ;
    PORT
      LAYER M5 ;
        RECT  18.72 0 18.744 0.084 ;
    END
  END wq_w[55]
  PIN wq_w[56]
    DIRECTION OUTPUT ;
    USE SIGNAL ;
    PORT
      LAYER M5 ;
        RECT  19.056 0 19.08 0.084 ;
    END
  END wq_w[56]
  PIN wq_w[57]
    DIRECTION OUTPUT ;
    USE SIGNAL ;
    PORT
      LAYER M5 ;
        RECT  19.392 0 19.416 0.084 ;
    END
  END wq_w[57]
  PIN wq_w[58]
    DIRECTION OUTPUT ;
    USE SIGNAL ;
    PORT
      LAYER M5 ;
        RECT  19.728 0 19.752 0.084 ;
    END
  END wq_w[58]
  PIN wq_w[59]
    DIRECTION OUTPUT ;
    USE SIGNAL ;
    PORT
      LAYER M5 ;
        RECT  20.064 0 20.088 0.084 ;
    END
  END wq_w[59]
  PIN wq_w[5]
    DIRECTION OUTPUT ;
    USE SIGNAL ;
    PORT
      LAYER M5 ;
        RECT  1.824 0 1.848 0.084 ;
    END
  END wq_w[5]
  PIN wq_w[60]
    DIRECTION OUTPUT ;
    USE SIGNAL ;
    PORT
      LAYER M5 ;
        RECT  20.4 0 20.424 0.084 ;
    END
  END wq_w[60]
  PIN wq_w[61]
    DIRECTION OUTPUT ;
    USE SIGNAL ;
    PORT
      LAYER M5 ;
        RECT  20.736 0 20.76 0.084 ;
    END
  END wq_w[61]
  PIN wq_w[62]
    DIRECTION OUTPUT ;
    USE SIGNAL ;
    PORT
      LAYER M5 ;
        RECT  21.072 0 21.096 0.084 ;
    END
  END wq_w[62]
  PIN wq_w[63]
    DIRECTION OUTPUT ;
    USE SIGNAL ;
    PORT
      LAYER M5 ;
        RECT  21.408 0 21.432 0.084 ;
    END
  END wq_w[63]
  PIN wq_w[64]
    DIRECTION OUTPUT ;
    USE SIGNAL ;
    PORT
      LAYER M5 ;
        RECT  21.744 0 21.768 0.084 ;
    END
  END wq_w[64]
  PIN wq_w[65]
    DIRECTION OUTPUT ;
    USE SIGNAL ;
    PORT
      LAYER M5 ;
        RECT  22.08 0 22.104 0.084 ;
    END
  END wq_w[65]
  PIN wq_w[66]
    DIRECTION OUTPUT ;
    USE SIGNAL ;
    PORT
      LAYER M5 ;
        RECT  22.416 0 22.44 0.084 ;
    END
  END wq_w[66]
  PIN wq_w[67]
    DIRECTION OUTPUT ;
    USE SIGNAL ;
    PORT
      LAYER M5 ;
        RECT  22.752 0 22.776 0.084 ;
    END
  END wq_w[67]
  PIN wq_w[68]
    DIRECTION OUTPUT ;
    USE SIGNAL ;
    PORT
      LAYER M5 ;
        RECT  23.088 0 23.112 0.084 ;
    END
  END wq_w[68]
  PIN wq_w[69]
    DIRECTION OUTPUT ;
    USE SIGNAL ;
    PORT
      LAYER M5 ;
        RECT  23.424 0 23.448 0.084 ;
    END
  END wq_w[69]
  PIN wq_w[6]
    DIRECTION OUTPUT ;
    USE SIGNAL ;
    PORT
      LAYER M5 ;
        RECT  2.16 0 2.184 0.084 ;
    END
  END wq_w[6]
  PIN wq_w[70]
    DIRECTION OUTPUT ;
    USE SIGNAL ;
    PORT
      LAYER M5 ;
        RECT  23.76 0 23.784 0.084 ;
    END
  END wq_w[70]
  PIN wq_w[71]
    DIRECTION OUTPUT ;
    USE SIGNAL ;
    PORT
      LAYER M5 ;
        RECT  24.096 0 24.12 0.084 ;
    END
  END wq_w[71]
  PIN wq_w[72]
    DIRECTION OUTPUT ;
    USE SIGNAL ;
    PORT
      LAYER M5 ;
        RECT  24.48 0 24.504 0.084 ;
    END
  END wq_w[72]
  PIN wq_w[73]
    DIRECTION OUTPUT ;
    USE SIGNAL ;
    PORT
      LAYER M5 ;
        RECT  24.816 0 24.84 0.084 ;
    END
  END wq_w[73]
  PIN wq_w[74]
    DIRECTION OUTPUT ;
    USE SIGNAL ;
    PORT
      LAYER M5 ;
        RECT  25.152 0 25.176 0.084 ;
    END
  END wq_w[74]
  PIN wq_w[75]
    DIRECTION OUTPUT ;
    USE SIGNAL ;
    PORT
      LAYER M5 ;
        RECT  25.488 0 25.512 0.084 ;
    END
  END wq_w[75]
  PIN wq_w[76]
    DIRECTION OUTPUT ;
    USE SIGNAL ;
    PORT
      LAYER M5 ;
        RECT  25.824 0 25.848 0.084 ;
    END
  END wq_w[76]
  PIN wq_w[77]
    DIRECTION OUTPUT ;
    USE SIGNAL ;
    PORT
      LAYER M5 ;
        RECT  26.16 0 26.184 0.084 ;
    END
  END wq_w[77]
  PIN wq_w[78]
    DIRECTION OUTPUT ;
    USE SIGNAL ;
    PORT
      LAYER M5 ;
        RECT  26.496 0 26.52 0.084 ;
    END
  END wq_w[78]
  PIN wq_w[79]
    DIRECTION OUTPUT ;
    USE SIGNAL ;
    PORT
      LAYER M5 ;
        RECT  26.832 0 26.856 0.084 ;
    END
  END wq_w[79]
  PIN wq_w[7]
    DIRECTION OUTPUT ;
    USE SIGNAL ;
    PORT
      LAYER M5 ;
        RECT  2.496 0 2.52 0.084 ;
    END
  END wq_w[7]
  PIN wq_w[80]
    DIRECTION OUTPUT ;
    USE SIGNAL ;
    PORT
      LAYER M5 ;
        RECT  27.168 0 27.192 0.084 ;
    END
  END wq_w[80]
  PIN wq_w[81]
    DIRECTION OUTPUT ;
    USE SIGNAL ;
    PORT
      LAYER M5 ;
        RECT  27.504 0 27.528 0.084 ;
    END
  END wq_w[81]
  PIN wq_w[82]
    DIRECTION OUTPUT ;
    USE SIGNAL ;
    PORT
      LAYER M5 ;
        RECT  27.84 0 27.864 0.084 ;
    END
  END wq_w[82]
  PIN wq_w[83]
    DIRECTION OUTPUT ;
    USE SIGNAL ;
    PORT
      LAYER M5 ;
        RECT  28.176 0 28.2 0.084 ;
    END
  END wq_w[83]
  PIN wq_w[84]
    DIRECTION OUTPUT ;
    USE SIGNAL ;
    PORT
      LAYER M5 ;
        RECT  28.512 0 28.536 0.084 ;
    END
  END wq_w[84]
  PIN wq_w[85]
    DIRECTION OUTPUT ;
    USE SIGNAL ;
    PORT
      LAYER M5 ;
        RECT  28.848 0 28.872 0.084 ;
    END
  END wq_w[85]
  PIN wq_w[86]
    DIRECTION OUTPUT ;
    USE SIGNAL ;
    PORT
      LAYER M5 ;
        RECT  29.184 0 29.208 0.084 ;
    END
  END wq_w[86]
  PIN wq_w[87]
    DIRECTION OUTPUT ;
    USE SIGNAL ;
    PORT
      LAYER M5 ;
        RECT  29.52 0 29.544 0.084 ;
    END
  END wq_w[87]
  PIN wq_w[88]
    DIRECTION OUTPUT ;
    USE SIGNAL ;
    PORT
      LAYER M5 ;
        RECT  29.856 0 29.88 0.084 ;
    END
  END wq_w[88]
  PIN wq_w[89]
    DIRECTION OUTPUT ;
    USE SIGNAL ;
    PORT
      LAYER M5 ;
        RECT  30.192 0 30.216 0.084 ;
    END
  END wq_w[89]
  PIN wq_w[8]
    DIRECTION OUTPUT ;
    USE SIGNAL ;
    PORT
      LAYER M5 ;
        RECT  2.88 0 2.904 0.084 ;
    END
  END wq_w[8]
  PIN wq_w[90]
    DIRECTION OUTPUT ;
    USE SIGNAL ;
    PORT
      LAYER M5 ;
        RECT  30.528 0 30.552 0.084 ;
    END
  END wq_w[90]
  PIN wq_w[91]
    DIRECTION OUTPUT ;
    USE SIGNAL ;
    PORT
      LAYER M5 ;
        RECT  30.864 0 30.888 0.084 ;
    END
  END wq_w[91]
  PIN wq_w[92]
    DIRECTION OUTPUT ;
    USE SIGNAL ;
    PORT
      LAYER M5 ;
        RECT  31.2 0 31.224 0.084 ;
    END
  END wq_w[92]
  PIN wq_w[93]
    DIRECTION OUTPUT ;
    USE SIGNAL ;
    PORT
      LAYER M5 ;
        RECT  31.536 0 31.56 0.084 ;
    END
  END wq_w[93]
  PIN wq_w[94]
    DIRECTION OUTPUT ;
    USE SIGNAL ;
    PORT
      LAYER M5 ;
        RECT  31.872 0 31.896 0.084 ;
    END
  END wq_w[94]
  PIN wq_w[95]
    DIRECTION OUTPUT ;
    USE SIGNAL ;
    PORT
      LAYER M5 ;
        RECT  32.208 0 32.232 0.084 ;
    END
  END wq_w[95]
  PIN wq_w[96]
    DIRECTION OUTPUT ;
    USE SIGNAL ;
    PORT
      LAYER M5 ;
        RECT  32.544 0 32.568 0.084 ;
    END
  END wq_w[96]
  PIN wq_w[97]
    DIRECTION OUTPUT ;
    USE SIGNAL ;
    PORT
      LAYER M5 ;
        RECT  32.88 0 32.904 0.084 ;
    END
  END wq_w[97]
  PIN wq_w[98]
    DIRECTION OUTPUT ;
    USE SIGNAL ;
    PORT
      LAYER M5 ;
        RECT  33.216 0 33.24 0.084 ;
    END
  END wq_w[98]
  PIN wq_w[99]
    DIRECTION OUTPUT ;
    USE SIGNAL ;
    PORT
      LAYER M5 ;
        RECT  33.552 0 33.576 0.084 ;
    END
  END wq_w[99]
  PIN wq_w[9]
    DIRECTION OUTPUT ;
    USE SIGNAL ;
    PORT
      LAYER M5 ;
        RECT  3.216 0 3.24 0.084 ;
    END
  END wq_w[9]
  PIN wsel[0]
    DIRECTION INPUT ;
    USE SIGNAL ;
    PORT
      LAYER M4 ;
        RECT  0 16.176 0.084 16.2 ;
    END
    PORT
      LAYER M4 ;
        RECT  0.06 16.176 2.408 16.2 ;
    END
  END wsel[0]
  PIN wsel[1]
    DIRECTION INPUT ;
    USE SIGNAL ;
    PORT
      LAYER M4 ;
        RECT  0 26.976 0.084 27 ;
    END
    PORT
      LAYER M4 ;
        RECT  0.06 26.976 2.408 27 ;
    END
  END wsel[1]
  PIN wsel[2]
    DIRECTION INPUT ;
    USE SIGNAL ;
    PORT
      LAYER M4 ;
        RECT  0 37.776 0.084 37.8 ;
    END
    PORT
      LAYER M4 ;
        RECT  0.06 37.776 0.137 37.8 ;
    END
  END wsel[2]
  PIN y_w[0]
    DIRECTION INPUT ;
    USE SIGNAL ;
    PORT
      LAYER M4 ;
        RECT  86.316 0.144 86.4 0.168 ;
    END
  END y_w[0]
  PIN y_w[100]
    DIRECTION INPUT ;
    USE SIGNAL ;
    PORT
      LAYER M4 ;
        RECT  86.316 33.888 86.4 33.912 ;
    END
  END y_w[100]
  PIN y_w[101]
    DIRECTION INPUT ;
    USE SIGNAL ;
    PORT
      LAYER M4 ;
        RECT  86.316 34.224 86.4 34.248 ;
    END
  END y_w[101]
  PIN y_w[102]
    DIRECTION INPUT ;
    USE SIGNAL ;
    PORT
      LAYER M4 ;
        RECT  86.316 34.56 86.4 34.584 ;
    END
  END y_w[102]
  PIN y_w[103]
    DIRECTION INPUT ;
    USE SIGNAL ;
    PORT
      LAYER M4 ;
        RECT  86.316 34.896 86.4 34.92 ;
    END
  END y_w[103]
  PIN y_w[104]
    DIRECTION INPUT ;
    USE SIGNAL ;
    PORT
      LAYER M4 ;
        RECT  86.316 35.28 86.4 35.304 ;
    END
  END y_w[104]
  PIN y_w[105]
    DIRECTION INPUT ;
    USE SIGNAL ;
    PORT
      LAYER M4 ;
        RECT  86.316 35.616 86.4 35.64 ;
    END
  END y_w[105]
  PIN y_w[106]
    DIRECTION INPUT ;
    USE SIGNAL ;
    PORT
      LAYER M4 ;
        RECT  86.316 35.952 86.4 35.976 ;
    END
  END y_w[106]
  PIN y_w[107]
    DIRECTION INPUT ;
    USE SIGNAL ;
    PORT
      LAYER M4 ;
        RECT  86.316 36.288 86.4 36.312 ;
    END
  END y_w[107]
  PIN y_w[108]
    DIRECTION INPUT ;
    USE SIGNAL ;
    PORT
      LAYER M4 ;
        RECT  86.316 36.624 86.4 36.648 ;
    END
  END y_w[108]
  PIN y_w[109]
    DIRECTION INPUT ;
    USE SIGNAL ;
    PORT
      LAYER M4 ;
        RECT  86.316 36.96 86.4 36.984 ;
    END
  END y_w[109]
  PIN y_w[10]
    DIRECTION INPUT ;
    USE SIGNAL ;
    PORT
      LAYER M4 ;
        RECT  86.316 3.552 86.4 3.576 ;
    END
  END y_w[10]
  PIN y_w[110]
    DIRECTION INPUT ;
    USE SIGNAL ;
    PORT
      LAYER M4 ;
        RECT  86.316 37.296 86.4 37.32 ;
    END
  END y_w[110]
  PIN y_w[111]
    DIRECTION INPUT ;
    USE SIGNAL ;
    PORT
      LAYER M4 ;
        RECT  86.316 37.632 86.4 37.656 ;
    END
  END y_w[111]
  PIN y_w[112]
    DIRECTION INPUT ;
    USE SIGNAL ;
    PORT
      LAYER M4 ;
        RECT  86.316 37.968 86.4 37.992 ;
    END
  END y_w[112]
  PIN y_w[113]
    DIRECTION INPUT ;
    USE SIGNAL ;
    PORT
      LAYER M4 ;
        RECT  86.316 38.304 86.4 38.328 ;
    END
  END y_w[113]
  PIN y_w[114]
    DIRECTION INPUT ;
    USE SIGNAL ;
    PORT
      LAYER M4 ;
        RECT  86.316 38.64 86.4 38.664 ;
    END
  END y_w[114]
  PIN y_w[115]
    DIRECTION INPUT ;
    USE SIGNAL ;
    PORT
      LAYER M4 ;
        RECT  86.316 38.976 86.4 39 ;
    END
  END y_w[115]
  PIN y_w[116]
    DIRECTION INPUT ;
    USE SIGNAL ;
    PORT
      LAYER M4 ;
        RECT  86.316 39.312 86.4 39.336 ;
    END
  END y_w[116]
  PIN y_w[117]
    DIRECTION INPUT ;
    USE SIGNAL ;
    PORT
      LAYER M4 ;
        RECT  86.316 39.648 86.4 39.672 ;
    END
  END y_w[117]
  PIN y_w[118]
    DIRECTION INPUT ;
    USE SIGNAL ;
    PORT
      LAYER M4 ;
        RECT  86.316 39.984 86.4 40.008 ;
    END
  END y_w[118]
  PIN y_w[119]
    DIRECTION INPUT ;
    USE SIGNAL ;
    PORT
      LAYER M4 ;
        RECT  86.316 40.32 86.4 40.344 ;
    END
  END y_w[119]
  PIN y_w[11]
    DIRECTION INPUT ;
    USE SIGNAL ;
    PORT
      LAYER M4 ;
        RECT  86.316 3.888 86.4 3.912 ;
    END
  END y_w[11]
  PIN y_w[120]
    DIRECTION INPUT ;
    USE SIGNAL ;
    PORT
      LAYER M4 ;
        RECT  86.316 40.656 86.4 40.68 ;
    END
  END y_w[120]
  PIN y_w[121]
    DIRECTION INPUT ;
    USE SIGNAL ;
    PORT
      LAYER M4 ;
        RECT  86.316 40.992 86.4 41.016 ;
    END
  END y_w[121]
  PIN y_w[122]
    DIRECTION INPUT ;
    USE SIGNAL ;
    PORT
      LAYER M4 ;
        RECT  86.316 41.328 86.4 41.352 ;
    END
  END y_w[122]
  PIN y_w[123]
    DIRECTION INPUT ;
    USE SIGNAL ;
    PORT
      LAYER M4 ;
        RECT  86.316 41.664 86.4 41.688 ;
    END
  END y_w[123]
  PIN y_w[124]
    DIRECTION INPUT ;
    USE SIGNAL ;
    PORT
      LAYER M4 ;
        RECT  86.316 42 86.4 42.024 ;
    END
  END y_w[124]
  PIN y_w[125]
    DIRECTION INPUT ;
    USE SIGNAL ;
    PORT
      LAYER M4 ;
        RECT  86.316 42.336 86.4 42.36 ;
    END
  END y_w[125]
  PIN y_w[126]
    DIRECTION INPUT ;
    USE SIGNAL ;
    PORT
      LAYER M4 ;
        RECT  86.316 42.672 86.4 42.696 ;
    END
  END y_w[126]
  PIN y_w[127]
    DIRECTION INPUT ;
    USE SIGNAL ;
    PORT
      LAYER M4 ;
        RECT  86.316 43.008 86.4 43.032 ;
    END
  END y_w[127]
  PIN y_w[12]
    DIRECTION INPUT ;
    USE SIGNAL ;
    PORT
      LAYER M4 ;
        RECT  86.316 4.224 86.4 4.248 ;
    END
  END y_w[12]
  PIN y_w[13]
    DIRECTION INPUT ;
    USE SIGNAL ;
    PORT
      LAYER M4 ;
        RECT  86.316 4.56 86.4 4.584 ;
    END
  END y_w[13]
  PIN y_w[14]
    DIRECTION INPUT ;
    USE SIGNAL ;
    PORT
      LAYER M4 ;
        RECT  86.316 4.896 86.4 4.92 ;
    END
  END y_w[14]
  PIN y_w[15]
    DIRECTION INPUT ;
    USE SIGNAL ;
    PORT
      LAYER M4 ;
        RECT  86.316 5.232 86.4 5.256 ;
    END
  END y_w[15]
  PIN y_w[16]
    DIRECTION INPUT ;
    USE SIGNAL ;
    PORT
      LAYER M4 ;
        RECT  86.316 5.568 86.4 5.592 ;
    END
  END y_w[16]
  PIN y_w[17]
    DIRECTION INPUT ;
    USE SIGNAL ;
    PORT
      LAYER M4 ;
        RECT  86.316 5.904 86.4 5.928 ;
    END
  END y_w[17]
  PIN y_w[18]
    DIRECTION INPUT ;
    USE SIGNAL ;
    PORT
      LAYER M4 ;
        RECT  86.316 6.24 86.4 6.264 ;
    END
  END y_w[18]
  PIN y_w[19]
    DIRECTION INPUT ;
    USE SIGNAL ;
    PORT
      LAYER M4 ;
        RECT  86.316 6.576 86.4 6.6 ;
    END
  END y_w[19]
  PIN y_w[1]
    DIRECTION INPUT ;
    USE SIGNAL ;
    PORT
      LAYER M4 ;
        RECT  86.316 0.48 86.4 0.504 ;
    END
  END y_w[1]
  PIN y_w[20]
    DIRECTION INPUT ;
    USE SIGNAL ;
    PORT
      LAYER M4 ;
        RECT  86.316 6.912 86.4 6.936 ;
    END
  END y_w[20]
  PIN y_w[21]
    DIRECTION INPUT ;
    USE SIGNAL ;
    PORT
      LAYER M4 ;
        RECT  86.316 7.248 86.4 7.272 ;
    END
  END y_w[21]
  PIN y_w[22]
    DIRECTION INPUT ;
    USE SIGNAL ;
    PORT
      LAYER M4 ;
        RECT  86.316 7.584 86.4 7.608 ;
    END
  END y_w[22]
  PIN y_w[23]
    DIRECTION INPUT ;
    USE SIGNAL ;
    PORT
      LAYER M4 ;
        RECT  86.316 7.92 86.4 7.944 ;
    END
  END y_w[23]
  PIN y_w[24]
    DIRECTION INPUT ;
    USE SIGNAL ;
    PORT
      LAYER M4 ;
        RECT  86.316 8.256 86.4 8.28 ;
    END
  END y_w[24]
  PIN y_w[25]
    DIRECTION INPUT ;
    USE SIGNAL ;
    PORT
      LAYER M4 ;
        RECT  86.316 8.592 86.4 8.616 ;
    END
  END y_w[25]
  PIN y_w[26]
    DIRECTION INPUT ;
    USE SIGNAL ;
    PORT
      LAYER M4 ;
        RECT  86.316 8.928 86.4 8.952 ;
    END
  END y_w[26]
  PIN y_w[27]
    DIRECTION INPUT ;
    USE SIGNAL ;
    PORT
      LAYER M4 ;
        RECT  86.316 9.264 86.4 9.288 ;
    END
  END y_w[27]
  PIN y_w[28]
    DIRECTION INPUT ;
    USE SIGNAL ;
    PORT
      LAYER M4 ;
        RECT  86.316 9.6 86.4 9.624 ;
    END
  END y_w[28]
  PIN y_w[29]
    DIRECTION INPUT ;
    USE SIGNAL ;
    PORT
      LAYER M4 ;
        RECT  86.316 9.936 86.4 9.96 ;
    END
  END y_w[29]
  PIN y_w[2]
    DIRECTION INPUT ;
    USE SIGNAL ;
    PORT
      LAYER M4 ;
        RECT  86.316 0.816 86.4 0.84 ;
    END
  END y_w[2]
  PIN y_w[30]
    DIRECTION INPUT ;
    USE SIGNAL ;
    PORT
      LAYER M4 ;
        RECT  86.316 10.272 86.4 10.296 ;
    END
  END y_w[30]
  PIN y_w[31]
    DIRECTION INPUT ;
    USE SIGNAL ;
    PORT
      LAYER M4 ;
        RECT  86.316 10.608 86.4 10.632 ;
    END
  END y_w[31]
  PIN y_w[32]
    DIRECTION INPUT ;
    USE SIGNAL ;
    PORT
      LAYER M4 ;
        RECT  86.316 10.944 86.4 10.968 ;
    END
  END y_w[32]
  PIN y_w[33]
    DIRECTION INPUT ;
    USE SIGNAL ;
    PORT
      LAYER M4 ;
        RECT  86.316 11.28 86.4 11.304 ;
    END
  END y_w[33]
  PIN y_w[34]
    DIRECTION INPUT ;
    USE SIGNAL ;
    PORT
      LAYER M4 ;
        RECT  86.316 11.616 86.4 11.64 ;
    END
  END y_w[34]
  PIN y_w[35]
    DIRECTION INPUT ;
    USE SIGNAL ;
    PORT
      LAYER M4 ;
        RECT  86.316 11.952 86.4 11.976 ;
    END
  END y_w[35]
  PIN y_w[36]
    DIRECTION INPUT ;
    USE SIGNAL ;
    PORT
      LAYER M4 ;
        RECT  86.316 12.288 86.4 12.312 ;
    END
  END y_w[36]
  PIN y_w[37]
    DIRECTION INPUT ;
    USE SIGNAL ;
    PORT
      LAYER M4 ;
        RECT  86.316 12.624 86.4 12.648 ;
    END
  END y_w[37]
  PIN y_w[38]
    DIRECTION INPUT ;
    USE SIGNAL ;
    PORT
      LAYER M4 ;
        RECT  86.316 12.96 86.4 12.984 ;
    END
  END y_w[38]
  PIN y_w[39]
    DIRECTION INPUT ;
    USE SIGNAL ;
    PORT
      LAYER M4 ;
        RECT  86.316 13.296 86.4 13.32 ;
    END
  END y_w[39]
  PIN y_w[3]
    DIRECTION INPUT ;
    USE SIGNAL ;
    PORT
      LAYER M4 ;
        RECT  86.316 1.152 86.4 1.176 ;
    END
  END y_w[3]
  PIN y_w[40]
    DIRECTION INPUT ;
    USE SIGNAL ;
    PORT
      LAYER M4 ;
        RECT  86.316 13.68 86.4 13.704 ;
    END
  END y_w[40]
  PIN y_w[41]
    DIRECTION INPUT ;
    USE SIGNAL ;
    PORT
      LAYER M4 ;
        RECT  86.316 14.016 86.4 14.04 ;
    END
  END y_w[41]
  PIN y_w[42]
    DIRECTION INPUT ;
    USE SIGNAL ;
    PORT
      LAYER M4 ;
        RECT  86.316 14.352 86.4 14.376 ;
    END
  END y_w[42]
  PIN y_w[43]
    DIRECTION INPUT ;
    USE SIGNAL ;
    PORT
      LAYER M4 ;
        RECT  86.316 14.688 86.4 14.712 ;
    END
  END y_w[43]
  PIN y_w[44]
    DIRECTION INPUT ;
    USE SIGNAL ;
    PORT
      LAYER M4 ;
        RECT  86.316 15.024 86.4 15.048 ;
    END
  END y_w[44]
  PIN y_w[45]
    DIRECTION INPUT ;
    USE SIGNAL ;
    PORT
      LAYER M4 ;
        RECT  86.316 15.36 86.4 15.384 ;
    END
  END y_w[45]
  PIN y_w[46]
    DIRECTION INPUT ;
    USE SIGNAL ;
    PORT
      LAYER M4 ;
        RECT  86.316 15.696 86.4 15.72 ;
    END
  END y_w[46]
  PIN y_w[47]
    DIRECTION INPUT ;
    USE SIGNAL ;
    PORT
      LAYER M4 ;
        RECT  86.316 16.032 86.4 16.056 ;
    END
  END y_w[47]
  PIN y_w[48]
    DIRECTION INPUT ;
    USE SIGNAL ;
    PORT
      LAYER M4 ;
        RECT  86.316 16.368 86.4 16.392 ;
    END
  END y_w[48]
  PIN y_w[49]
    DIRECTION INPUT ;
    USE SIGNAL ;
    PORT
      LAYER M4 ;
        RECT  86.316 16.704 86.4 16.728 ;
    END
  END y_w[49]
  PIN y_w[4]
    DIRECTION INPUT ;
    USE SIGNAL ;
    PORT
      LAYER M4 ;
        RECT  86.316 1.488 86.4 1.512 ;
    END
  END y_w[4]
  PIN y_w[50]
    DIRECTION INPUT ;
    USE SIGNAL ;
    PORT
      LAYER M4 ;
        RECT  86.316 17.04 86.4 17.064 ;
    END
  END y_w[50]
  PIN y_w[51]
    DIRECTION INPUT ;
    USE SIGNAL ;
    PORT
      LAYER M4 ;
        RECT  86.316 17.376 86.4 17.4 ;
    END
  END y_w[51]
  PIN y_w[52]
    DIRECTION INPUT ;
    USE SIGNAL ;
    PORT
      LAYER M4 ;
        RECT  86.316 17.712 86.4 17.736 ;
    END
  END y_w[52]
  PIN y_w[53]
    DIRECTION INPUT ;
    USE SIGNAL ;
    PORT
      LAYER M4 ;
        RECT  86.316 18.048 86.4 18.072 ;
    END
  END y_w[53]
  PIN y_w[54]
    DIRECTION INPUT ;
    USE SIGNAL ;
    PORT
      LAYER M4 ;
        RECT  86.316 18.384 86.4 18.408 ;
    END
  END y_w[54]
  PIN y_w[55]
    DIRECTION INPUT ;
    USE SIGNAL ;
    PORT
      LAYER M4 ;
        RECT  86.316 18.72 86.4 18.744 ;
    END
  END y_w[55]
  PIN y_w[56]
    DIRECTION INPUT ;
    USE SIGNAL ;
    PORT
      LAYER M4 ;
        RECT  86.316 19.056 86.4 19.08 ;
    END
  END y_w[56]
  PIN y_w[57]
    DIRECTION INPUT ;
    USE SIGNAL ;
    PORT
      LAYER M4 ;
        RECT  86.316 19.392 86.4 19.416 ;
    END
  END y_w[57]
  PIN y_w[58]
    DIRECTION INPUT ;
    USE SIGNAL ;
    PORT
      LAYER M4 ;
        RECT  86.316 19.728 86.4 19.752 ;
    END
  END y_w[58]
  PIN y_w[59]
    DIRECTION INPUT ;
    USE SIGNAL ;
    PORT
      LAYER M4 ;
        RECT  86.316 20.064 86.4 20.088 ;
    END
  END y_w[59]
  PIN y_w[5]
    DIRECTION INPUT ;
    USE SIGNAL ;
    PORT
      LAYER M4 ;
        RECT  86.316 1.824 86.4 1.848 ;
    END
  END y_w[5]
  PIN y_w[60]
    DIRECTION INPUT ;
    USE SIGNAL ;
    PORT
      LAYER M4 ;
        RECT  86.316 20.4 86.4 20.424 ;
    END
  END y_w[60]
  PIN y_w[61]
    DIRECTION INPUT ;
    USE SIGNAL ;
    PORT
      LAYER M4 ;
        RECT  86.316 20.736 86.4 20.76 ;
    END
  END y_w[61]
  PIN y_w[62]
    DIRECTION INPUT ;
    USE SIGNAL ;
    PORT
      LAYER M4 ;
        RECT  86.316 21.072 86.4 21.096 ;
    END
  END y_w[62]
  PIN y_w[63]
    DIRECTION INPUT ;
    USE SIGNAL ;
    PORT
      LAYER M4 ;
        RECT  86.316 21.408 86.4 21.432 ;
    END
  END y_w[63]
  PIN y_w[64]
    DIRECTION INPUT ;
    USE SIGNAL ;
    PORT
      LAYER M4 ;
        RECT  86.316 21.744 86.4 21.768 ;
    END
  END y_w[64]
  PIN y_w[65]
    DIRECTION INPUT ;
    USE SIGNAL ;
    PORT
      LAYER M4 ;
        RECT  86.316 22.08 86.4 22.104 ;
    END
  END y_w[65]
  PIN y_w[66]
    DIRECTION INPUT ;
    USE SIGNAL ;
    PORT
      LAYER M4 ;
        RECT  86.316 22.416 86.4 22.44 ;
    END
  END y_w[66]
  PIN y_w[67]
    DIRECTION INPUT ;
    USE SIGNAL ;
    PORT
      LAYER M4 ;
        RECT  86.316 22.752 86.4 22.776 ;
    END
  END y_w[67]
  PIN y_w[68]
    DIRECTION INPUT ;
    USE SIGNAL ;
    PORT
      LAYER M4 ;
        RECT  86.316 23.088 86.4 23.112 ;
    END
  END y_w[68]
  PIN y_w[69]
    DIRECTION INPUT ;
    USE SIGNAL ;
    PORT
      LAYER M4 ;
        RECT  86.316 23.424 86.4 23.448 ;
    END
  END y_w[69]
  PIN y_w[6]
    DIRECTION INPUT ;
    USE SIGNAL ;
    PORT
      LAYER M4 ;
        RECT  86.316 2.16 86.4 2.184 ;
    END
  END y_w[6]
  PIN y_w[70]
    DIRECTION INPUT ;
    USE SIGNAL ;
    PORT
      LAYER M4 ;
        RECT  86.316 23.76 86.4 23.784 ;
    END
  END y_w[70]
  PIN y_w[71]
    DIRECTION INPUT ;
    USE SIGNAL ;
    PORT
      LAYER M4 ;
        RECT  86.316 24.096 86.4 24.12 ;
    END
  END y_w[71]
  PIN y_w[72]
    DIRECTION INPUT ;
    USE SIGNAL ;
    PORT
      LAYER M4 ;
        RECT  86.316 24.48 86.4 24.504 ;
    END
  END y_w[72]
  PIN y_w[73]
    DIRECTION INPUT ;
    USE SIGNAL ;
    PORT
      LAYER M4 ;
        RECT  86.316 24.816 86.4 24.84 ;
    END
  END y_w[73]
  PIN y_w[74]
    DIRECTION INPUT ;
    USE SIGNAL ;
    PORT
      LAYER M4 ;
        RECT  86.316 25.152 86.4 25.176 ;
    END
  END y_w[74]
  PIN y_w[75]
    DIRECTION INPUT ;
    USE SIGNAL ;
    PORT
      LAYER M4 ;
        RECT  86.316 25.488 86.4 25.512 ;
    END
  END y_w[75]
  PIN y_w[76]
    DIRECTION INPUT ;
    USE SIGNAL ;
    PORT
      LAYER M4 ;
        RECT  86.316 25.824 86.4 25.848 ;
    END
  END y_w[76]
  PIN y_w[77]
    DIRECTION INPUT ;
    USE SIGNAL ;
    PORT
      LAYER M4 ;
        RECT  86.316 26.16 86.4 26.184 ;
    END
  END y_w[77]
  PIN y_w[78]
    DIRECTION INPUT ;
    USE SIGNAL ;
    PORT
      LAYER M4 ;
        RECT  86.316 26.496 86.4 26.52 ;
    END
  END y_w[78]
  PIN y_w[79]
    DIRECTION INPUT ;
    USE SIGNAL ;
    PORT
      LAYER M4 ;
        RECT  86.316 26.832 86.4 26.856 ;
    END
  END y_w[79]
  PIN y_w[7]
    DIRECTION INPUT ;
    USE SIGNAL ;
    PORT
      LAYER M4 ;
        RECT  86.316 2.496 86.4 2.52 ;
    END
  END y_w[7]
  PIN y_w[80]
    DIRECTION INPUT ;
    USE SIGNAL ;
    PORT
      LAYER M4 ;
        RECT  86.316 27.168 86.4 27.192 ;
    END
  END y_w[80]
  PIN y_w[81]
    DIRECTION INPUT ;
    USE SIGNAL ;
    PORT
      LAYER M4 ;
        RECT  86.316 27.504 86.4 27.528 ;
    END
  END y_w[81]
  PIN y_w[82]
    DIRECTION INPUT ;
    USE SIGNAL ;
    PORT
      LAYER M4 ;
        RECT  86.316 27.84 86.4 27.864 ;
    END
  END y_w[82]
  PIN y_w[83]
    DIRECTION INPUT ;
    USE SIGNAL ;
    PORT
      LAYER M4 ;
        RECT  86.316 28.176 86.4 28.2 ;
    END
  END y_w[83]
  PIN y_w[84]
    DIRECTION INPUT ;
    USE SIGNAL ;
    PORT
      LAYER M4 ;
        RECT  86.316 28.512 86.4 28.536 ;
    END
  END y_w[84]
  PIN y_w[85]
    DIRECTION INPUT ;
    USE SIGNAL ;
    PORT
      LAYER M4 ;
        RECT  86.316 28.848 86.4 28.872 ;
    END
  END y_w[85]
  PIN y_w[86]
    DIRECTION INPUT ;
    USE SIGNAL ;
    PORT
      LAYER M4 ;
        RECT  86.316 29.184 86.4 29.208 ;
    END
  END y_w[86]
  PIN y_w[87]
    DIRECTION INPUT ;
    USE SIGNAL ;
    PORT
      LAYER M4 ;
        RECT  86.316 29.52 86.4 29.544 ;
    END
  END y_w[87]
  PIN y_w[88]
    DIRECTION INPUT ;
    USE SIGNAL ;
    PORT
      LAYER M4 ;
        RECT  86.316 29.856 86.4 29.88 ;
    END
  END y_w[88]
  PIN y_w[89]
    DIRECTION INPUT ;
    USE SIGNAL ;
    PORT
      LAYER M4 ;
        RECT  86.316 30.192 86.4 30.216 ;
    END
  END y_w[89]
  PIN y_w[8]
    DIRECTION INPUT ;
    USE SIGNAL ;
    PORT
      LAYER M4 ;
        RECT  86.316 2.88 86.4 2.904 ;
    END
  END y_w[8]
  PIN y_w[90]
    DIRECTION INPUT ;
    USE SIGNAL ;
    PORT
      LAYER M4 ;
        RECT  86.316 30.528 86.4 30.552 ;
    END
  END y_w[90]
  PIN y_w[91]
    DIRECTION INPUT ;
    USE SIGNAL ;
    PORT
      LAYER M4 ;
        RECT  86.316 30.864 86.4 30.888 ;
    END
  END y_w[91]
  PIN y_w[92]
    DIRECTION INPUT ;
    USE SIGNAL ;
    PORT
      LAYER M4 ;
        RECT  86.316 31.2 86.4 31.224 ;
    END
  END y_w[92]
  PIN y_w[93]
    DIRECTION INPUT ;
    USE SIGNAL ;
    PORT
      LAYER M4 ;
        RECT  86.316 31.536 86.4 31.56 ;
    END
  END y_w[93]
  PIN y_w[94]
    DIRECTION INPUT ;
    USE SIGNAL ;
    PORT
      LAYER M4 ;
        RECT  86.316 31.872 86.4 31.896 ;
    END
  END y_w[94]
  PIN y_w[95]
    DIRECTION INPUT ;
    USE SIGNAL ;
    PORT
      LAYER M4 ;
        RECT  86.316 32.208 86.4 32.232 ;
    END
  END y_w[95]
  PIN y_w[96]
    DIRECTION INPUT ;
    USE SIGNAL ;
    PORT
      LAYER M4 ;
        RECT  86.316 32.544 86.4 32.568 ;
    END
  END y_w[96]
  PIN y_w[97]
    DIRECTION INPUT ;
    USE SIGNAL ;
    PORT
      LAYER M4 ;
        RECT  86.316 32.88 86.4 32.904 ;
    END
  END y_w[97]
  PIN y_w[98]
    DIRECTION INPUT ;
    USE SIGNAL ;
    PORT
      LAYER M4 ;
        RECT  86.316 33.216 86.4 33.24 ;
    END
  END y_w[98]
  PIN y_w[99]
    DIRECTION INPUT ;
    USE SIGNAL ;
    PORT
      LAYER M4 ;
        RECT  86.316 33.552 86.4 33.576 ;
    END
  END y_w[99]
  PIN y_w[9]
    DIRECTION INPUT ;
    USE SIGNAL ;
    PORT
      LAYER M4 ;
        RECT  86.316 3.216 86.4 3.24 ;
    END
  END y_w[9]
  PIN VSS
    DIRECTION INOUT ;
    USE GROUND ;
    PORT
      LAYER M5 ;
        RECT  83.4 2.137 83.52 41.063 ;
        RECT  78 2.137 78.12 41.063 ;
        RECT  72.6 2.137 72.72 41.063 ;
        RECT  67.2 2.137 67.32 41.063 ;
        RECT  61.8 2.137 61.92 41.063 ;
        RECT  56.4 2.137 56.52 41.063 ;
        RECT  51 2.137 51.12 41.063 ;
        RECT  45.6 2.137 45.72 41.063 ;
        RECT  40.2 2.137 40.32 41.063 ;
        RECT  34.8 2.137 34.92 41.063 ;
        RECT  29.4 2.137 29.52 41.063 ;
        RECT  24 2.137 24.12 41.063 ;
        RECT  18.6 2.137 18.72 41.063 ;
        RECT  13.2 2.137 13.32 41.063 ;
        RECT  7.8 2.137 7.92 41.063 ;
        RECT  2.4 2.137 2.52 41.063 ;
    END
  END VSS
  PIN VDD
    DIRECTION INOUT ;
    USE POWER ;
    PORT
      LAYER M5 ;
        RECT  83.592 2.151 83.712 41.049 ;
        RECT  78.192 2.151 78.312 41.049 ;
        RECT  72.792 2.151 72.912 41.049 ;
        RECT  67.392 2.151 67.512 41.049 ;
        RECT  61.992 2.151 62.112 41.049 ;
        RECT  56.592 2.151 56.712 41.049 ;
        RECT  51.192 2.151 51.312 41.049 ;
        RECT  45.792 2.151 45.912 41.049 ;
        RECT  40.392 2.151 40.512 41.049 ;
        RECT  34.992 2.151 35.112 41.049 ;
        RECT  29.592 2.151 29.712 41.049 ;
        RECT  24.192 2.151 24.312 41.049 ;
        RECT  18.792 2.151 18.912 41.049 ;
        RECT  13.392 2.151 13.512 41.049 ;
        RECT  7.992 2.151 8.112 41.049 ;
        RECT  2.592 2.151 2.712 41.049 ;
    END
  END VDD
  # OT_OBS_CLOSED layer=M5 d_um=1.536 added=211
  OBS
    LAYER RVTN ;
     RECT  2.16 2.16 84.24 2.295 ;
     RECT  2.16 2.565 84.24 2.835 ;
     RECT  2.16 3.105 84.24 3.375 ;
     RECT  2.16 3.645 84.24 3.915 ;
     RECT  2.16 4.185 84.24 4.455 ;
     RECT  2.16 4.725 84.24 4.995 ;
     RECT  2.16 5.265 84.24 5.535 ;
     RECT  2.16 5.805 84.24 6.075 ;
     RECT  2.16 6.345 84.24 6.615 ;
     RECT  2.16 6.885 84.24 7.155 ;
     RECT  2.16 7.425 84.24 7.695 ;
     RECT  2.16 7.965 84.24 8.235 ;
     RECT  2.16 8.505 84.24 8.775 ;
     RECT  2.16 9.045 84.24 9.315 ;
     RECT  2.16 9.585 84.24 9.855 ;
     RECT  2.16 10.125 84.24 10.395 ;
     RECT  2.16 10.665 84.24 10.935 ;
     RECT  2.16 11.205 84.24 11.475 ;
     RECT  2.16 11.745 84.24 12.015 ;
     RECT  2.16 12.285 84.24 12.555 ;
     RECT  2.16 12.825 84.24 13.095 ;
     RECT  2.16 13.365 84.24 13.635 ;
     RECT  2.16 13.905 84.24 14.175 ;
     RECT  2.16 14.445 84.24 14.715 ;
     RECT  2.16 14.985 84.24 15.255 ;
     RECT  2.16 15.525 84.24 15.795 ;
     RECT  2.16 16.065 84.24 16.335 ;
     RECT  2.16 16.605 84.24 16.875 ;
     RECT  2.16 17.145 84.24 17.415 ;
     RECT  2.16 17.685 84.24 17.955 ;
     RECT  2.16 18.225 84.24 18.495 ;
     RECT  2.16 18.765 84.24 19.035 ;
     RECT  2.16 19.305 84.24 19.575 ;
     RECT  2.16 19.845 84.24 20.115 ;
     RECT  2.16 20.385 84.24 20.655 ;
     RECT  2.16 20.925 84.24 21.195 ;
     RECT  2.16 21.465 84.24 21.735 ;
     RECT  2.16 22.005 84.24 22.275 ;
     RECT  2.16 22.545 84.24 22.815 ;
     RECT  2.16 23.085 84.24 23.355 ;
     RECT  2.16 23.625 84.24 23.895 ;
     RECT  2.16 24.165 84.24 24.435 ;
     RECT  2.16 24.705 84.24 24.975 ;
     RECT  2.16 25.245 84.24 25.515 ;
     RECT  2.16 25.785 84.24 26.055 ;
     RECT  2.16 26.325 84.24 26.595 ;
     RECT  2.16 26.865 84.24 27.135 ;
     RECT  2.16 27.405 84.24 27.675 ;
     RECT  2.16 27.945 84.24 28.215 ;
     RECT  2.16 28.485 84.24 28.755 ;
     RECT  2.16 29.025 84.24 29.295 ;
     RECT  2.16 29.565 84.24 29.835 ;
     RECT  2.16 30.105 84.24 30.375 ;
     RECT  2.16 30.645 84.24 30.915 ;
     RECT  2.16 31.185 84.24 31.455 ;
     RECT  2.16 31.725 84.24 31.995 ;
     RECT  2.16 32.265 84.24 32.535 ;
     RECT  2.16 32.805 84.24 33.075 ;
     RECT  2.16 33.345 84.24 33.615 ;
     RECT  2.16 33.885 84.24 34.155 ;
     RECT  2.16 34.425 84.24 34.695 ;
     RECT  2.16 34.965 84.24 35.235 ;
     RECT  2.16 35.505 84.24 35.775 ;
     RECT  2.16 36.045 84.24 36.315 ;
     RECT  2.16 36.585 84.24 36.855 ;
     RECT  2.16 37.125 84.24 37.395 ;
     RECT  2.16 37.665 84.24 37.935 ;
     RECT  2.16 38.205 84.24 38.475 ;
     RECT  2.16 38.745 84.24 39.015 ;
     RECT  2.16 39.285 84.24 39.555 ;
     RECT  2.16 39.825 84.24 40.095 ;
     RECT  2.16 40.365 84.24 40.635 ;
     RECT  2.16 40.905 84.24 41.04 ;
    LAYER RVTP ;
     RECT  2.16 2.295 84.24 2.565 ;
     RECT  2.16 2.835 84.24 3.105 ;
     RECT  2.16 3.375 84.24 3.645 ;
     RECT  2.16 3.915 84.24 4.185 ;
     RECT  2.16 4.455 84.24 4.725 ;
     RECT  2.16 4.995 84.24 5.265 ;
     RECT  2.16 5.535 84.24 5.805 ;
     RECT  2.16 6.075 84.24 6.345 ;
     RECT  2.16 6.615 84.24 6.885 ;
     RECT  2.16 7.155 84.24 7.425 ;
     RECT  2.16 7.695 84.24 7.965 ;
     RECT  2.16 8.235 84.24 8.505 ;
     RECT  2.16 8.775 84.24 9.045 ;
     RECT  2.16 9.315 84.24 9.585 ;
     RECT  2.16 9.855 84.24 10.125 ;
     RECT  2.16 10.395 84.24 10.665 ;
     RECT  2.16 10.935 84.24 11.205 ;
     RECT  2.16 11.475 84.24 11.745 ;
     RECT  2.16 12.015 84.24 12.285 ;
     RECT  2.16 12.555 84.24 12.825 ;
     RECT  2.16 13.095 84.24 13.365 ;
     RECT  2.16 13.635 84.24 13.905 ;
     RECT  2.16 14.175 84.24 14.445 ;
     RECT  2.16 14.715 84.24 14.985 ;
     RECT  2.16 15.255 84.24 15.525 ;
     RECT  2.16 15.795 84.24 16.065 ;
     RECT  2.16 16.335 84.24 16.605 ;
     RECT  2.16 16.875 84.24 17.145 ;
     RECT  2.16 17.415 84.24 17.685 ;
     RECT  2.16 17.955 84.24 18.225 ;
     RECT  2.16 18.495 84.24 18.765 ;
     RECT  2.16 19.035 84.24 19.305 ;
     RECT  2.16 19.575 84.24 19.845 ;
     RECT  2.16 20.115 84.24 20.385 ;
     RECT  2.16 20.655 84.24 20.925 ;
     RECT  2.16 21.195 84.24 21.465 ;
     RECT  2.16 21.735 84.24 22.005 ;
     RECT  2.16 22.275 84.24 22.545 ;
     RECT  2.16 22.815 84.24 23.085 ;
     RECT  2.16 23.355 84.24 23.625 ;
     RECT  2.16 23.895 84.24 24.165 ;
     RECT  2.16 24.435 84.24 24.705 ;
     RECT  2.16 24.975 84.24 25.245 ;
     RECT  2.16 25.515 84.24 25.785 ;
     RECT  2.16 26.055 84.24 26.325 ;
     RECT  2.16 26.595 84.24 26.865 ;
     RECT  2.16 27.135 84.24 27.405 ;
     RECT  2.16 27.675 84.24 27.945 ;
     RECT  2.16 28.215 84.24 28.485 ;
     RECT  2.16 28.755 84.24 29.025 ;
     RECT  2.16 29.295 84.24 29.565 ;
     RECT  2.16 29.835 84.24 30.105 ;
     RECT  2.16 30.375 84.24 30.645 ;
     RECT  2.16 30.915 84.24 31.185 ;
     RECT  2.16 31.455 84.24 31.725 ;
     RECT  2.16 31.995 84.24 32.265 ;
     RECT  2.16 32.535 84.24 32.805 ;
     RECT  2.16 33.075 84.24 33.345 ;
     RECT  2.16 33.615 84.24 33.885 ;
     RECT  2.16 34.155 84.24 34.425 ;
     RECT  2.16 34.695 84.24 34.965 ;
     RECT  2.16 35.235 84.24 35.505 ;
     RECT  2.16 35.775 84.24 36.045 ;
     RECT  2.16 36.315 84.24 36.585 ;
     RECT  2.16 36.855 84.24 37.125 ;
     RECT  2.16 37.395 84.24 37.665 ;
     RECT  2.16 37.935 84.24 38.205 ;
     RECT  2.16 38.475 84.24 38.745 ;
     RECT  2.16 39.015 84.24 39.285 ;
     RECT  2.16 39.555 84.24 39.825 ;
     RECT  2.16 40.095 84.24 40.365 ;
     RECT  2.16 40.635 84.24 40.905 ;
    LAYER M1 ;
     RECT  2.16 2.151 84.24 41.049 ;
    LAYER M2 ;
     RECT  1.831 5.616 2.16 5.634 ;
     RECT  0.103 37.602 2.16 37.62 ;
     RECT  2.16 2.151 2.299 41.049 ;
     RECT  2.299 2.106 3.415 41.049 ;
     RECT  3.415 1.728 4.415 41.049 ;
     RECT  18.031 1.152 18.599 1.17 ;
     RECT  4.415 2.151 20.155 41.049 ;
     RECT  22.999 1.152 23.099 1.17 ;
     RECT  20.155 2.034 28.543 41.049 ;
     RECT  28.543 1.998 28.615 41.049 ;
     RECT  28.615 1.962 28.895 41.049 ;
     RECT  28.895 1.998 29.075 41.049 ;
     RECT  34.951 1.152 35.195 1.17 ;
     RECT  36.643 1.152 36.743 1.17 ;
     RECT  29.075 2.034 37.183 41.049 ;
     RECT  37.183 1.692 38.335 41.049 ;
     RECT  38.335 1.152 38.471 41.049 ;
     RECT  38.471 1.566 40.027 41.049 ;
     RECT  40.027 1.152 40.127 41.049 ;
     RECT  40.127 1.566 47.047 41.049 ;
     RECT  47.047 1.152 47.291 41.049 ;
     RECT  47.291 1.566 56.803 41.049 ;
     RECT  56.803 1.152 56.903 41.049 ;
     RECT  56.903 1.566 58.315 41.049 ;
     RECT  58.315 1.152 58.523 41.049 ;
     RECT  58.523 1.566 59.575 41.049 ;
     RECT  59.575 1.152 60.431 41.049 ;
     RECT  60.431 1.611 68.675 41.049 ;
     RECT  68.675 1.692 75.767 41.049 ;
     RECT  75.767 2.151 77.323 41.049 ;
     RECT  77.323 1.728 77.567 41.049 ;
     RECT  77.827 1.152 77.963 1.17 ;
     RECT  77.567 2.151 81.031 41.049 ;
     RECT  81.031 2.106 81.491 41.049 ;
     RECT  81.491 2.151 83.623 41.049 ;
     RECT  83.623 2.106 84.24 41.049 ;
     RECT  84.24 2.106 84.371 14.67 ;
     RECT  84.24 15.462 84.371 20.07 ;
     RECT  84.24 20.898 84.371 28.44 ;
     RECT  84.371 15.462 84.407 15.552 ;
     RECT  84.371 2.106 84.659 12.312 ;
     RECT  84.24 29.232 84.695 40.968 ;
     RECT  84.659 2.106 84.875 6.84 ;
     RECT  84.371 20.898 84.875 23.85 ;
     RECT  84.695 37.872 84.875 40.968 ;
     RECT  84.659 7.74 84.911 12.312 ;
     RECT  84.371 13.068 84.911 14.67 ;
     RECT  84.407 15.462 84.911 15.48 ;
     RECT  84.371 16.65 84.911 20.07 ;
     RECT  84.875 20.97 84.911 23.85 ;
     RECT  84.371 24.642 84.911 28.44 ;
     RECT  84.695 29.232 84.911 37.116 ;
     RECT  84.875 37.872 84.911 37.89 ;
     RECT  84.875 38.682 84.911 40.968 ;
     RECT  84.875 2.232 85.019 6.84 ;
     RECT  84.911 34.362 85.127 35.46 ;
     RECT  84.911 7.74 85.307 9.036 ;
     RECT  85.019 2.232 85.487 3.6 ;
     RECT  85.019 4.662 85.487 6.84 ;
     RECT  85.307 8.712 85.487 9.036 ;
     RECT  84.911 9.792 85.487 10.62 ;
     RECT  84.911 17.928 85.487 17.946 ;
     RECT  84.911 18.972 85.487 18.99 ;
     RECT  84.911 19.782 85.487 20.07 ;
     RECT  84.911 22.212 85.487 22.806 ;
     RECT  84.911 23.832 85.487 23.85 ;
     RECT  84.911 24.642 85.487 24.66 ;
     RECT  84.911 25.452 85.487 25.47 ;
     RECT  84.911 26.838 85.487 26.856 ;
     RECT  84.911 27.612 85.487 27.63 ;
     RECT  84.911 28.422 85.487 28.44 ;
     RECT  84.911 30.312 85.487 30.6 ;
     RECT  84.911 31.968 85.487 32.49 ;
     RECT  85.127 34.362 85.487 34.38 ;
     RECT  85.127 35.442 85.487 35.46 ;
     RECT  84.911 36.594 85.487 36.612 ;
     RECT  84.911 39.798 85.487 40.968 ;
     RECT  85.487 6.822 85.523 6.84 ;
     RECT  85.307 7.74 85.523 7.758 ;
     RECT  84.911 13.572 85.523 13.59 ;
     RECT  85.487 40.95 85.523 40.968 ;
     RECT  85.487 39.798 85.559 39.816 ;
     RECT  85.487 2.808 86.243 2.934 ;
     RECT  85.487 4.662 86.243 5.796 ;
     RECT  85.487 9.018 86.243 9.036 ;
     RECT  86.243 2.916 86.279 2.934 ;
     RECT  86.243 4.662 86.315 5.22 ;
    LAYER M3 ;
     RECT  84.204 0.091 85.23 0.427 ;
     RECT  84.204 0.427 85.302 0.475 ;
     RECT  23.436 0.091 23.454 0.523 ;
     RECT  27.9 0.091 27.918 0.523 ;
     RECT  35.964 0.091 35.982 0.523 ;
     RECT  38.16 0.091 38.178 0.523 ;
     RECT  52.308 0.091 52.326 0.523 ;
     RECT  72.576 0.091 72.594 0.523 ;
     RECT  77.544 0.475 77.562 0.523 ;
     RECT  82.692 0.139 82.71 0.523 ;
     RECT  13.968 0.091 13.986 0.571 ;
     RECT  27.18 0.523 27.918 0.571 ;
     RECT  35.964 0.523 36.234 0.571 ;
     RECT  37.008 0.091 37.026 0.571 ;
     RECT  60.012 0.091 60.426 0.571 ;
     RECT  72.54 0.523 72.594 0.571 ;
     RECT  5.544 0.523 5.562 1.099 ;
     RECT  6.588 0.091 6.606 1.099 ;
     RECT  7.632 0.571 7.65 1.099 ;
     RECT  16.128 0.571 17.406 1.099 ;
     RECT  18.576 0.571 18.594 1.099 ;
     RECT  40.104 0.091 40.122 1.099 ;
     RECT  59.58 0.571 60.426 1.099 ;
     RECT  79.38 0.523 79.398 1.099 ;
     RECT  10.62 0.091 10.638 1.147 ;
     RECT  12.636 0.091 12.654 1.147 ;
     RECT  13.968 0.571 14.706 1.147 ;
     RECT  23.076 0.523 23.454 1.147 ;
     RECT  24.444 0.571 24.462 1.147 ;
     RECT  34.56 0.091 34.974 1.147 ;
     RECT  40.068 1.099 40.122 1.147 ;
     RECT  47.052 1.099 47.07 1.147 ;
     RECT  56.808 0.571 56.826 1.147 ;
     RECT  58.5 0.571 58.518 1.147 ;
     RECT  84.132 0.475 85.302 1.147 ;
     RECT  16.128 1.099 18.594 1.175 ;
     RECT  40.032 1.147 40.122 1.175 ;
     RECT  47.052 1.147 47.286 1.175 ;
     RECT  77.544 0.523 77.958 1.175 ;
     RECT  84.132 1.147 85.482 1.435 ;
     RECT  83.952 1.435 85.482 1.483 ;
     RECT  38.16 0.523 38.538 1.561 ;
     RECT  59.58 1.099 60.534 1.561 ;
     RECT  63.036 0.571 63.054 1.579 ;
     RECT  47.088 1.175 47.286 1.606 ;
     RECT  69.192 1.147 69.894 1.606 ;
     RECT  45.576 0.091 45.594 1.651 ;
     RECT  68.652 1.606 69.894 1.651 ;
     RECT  12.636 1.147 15.138 1.675 ;
     RECT  16.128 1.175 18.522 1.675 ;
     RECT  38.16 1.561 39.15 1.675 ;
     RECT  40.032 1.175 40.086 1.675 ;
     RECT  62.532 1.579 63.054 1.675 ;
     RECT  35.964 0.571 37.026 1.687 ;
     RECT  75.636 0.091 75.654 1.687 ;
     RECT  76.464 0.571 76.482 1.687 ;
     RECT  3.42 0.091 3.438 1.723 ;
     RECT  5.184 1.099 7.65 1.723 ;
     RECT  8.856 0.571 8.874 1.723 ;
     RECT  10.584 1.147 10.638 1.723 ;
     RECT  11.664 1.147 11.682 1.723 ;
     RECT  12.636 1.675 18.522 1.723 ;
     RECT  19.296 1.675 19.314 1.723 ;
     RECT  20.772 1.147 20.79 1.723 ;
     RECT  21.636 0.091 21.978 1.723 ;
     RECT  23.004 1.147 23.454 1.723 ;
     RECT  24.444 1.147 25.614 1.723 ;
     RECT  26.64 0.571 28.89 1.723 ;
     RECT  30.996 1.147 31.014 1.723 ;
     RECT  32.472 1.147 32.49 1.723 ;
     RECT  34.56 1.147 35.19 1.723 ;
     RECT  35.964 1.687 37.206 1.723 ;
     RECT  38.16 1.675 40.086 1.723 ;
     RECT  41.868 1.675 41.886 1.723 ;
     RECT  44.46 1.099 44.478 1.723 ;
     RECT  47.088 1.606 47.394 1.723 ;
     RECT  48.276 0.571 48.294 1.723 ;
     RECT  52.308 0.523 53.046 1.723 ;
     RECT  56.808 1.147 56.898 1.723 ;
     RECT  58.32 1.147 58.518 1.723 ;
     RECT  59.508 1.561 60.534 1.723 ;
     RECT  62.496 1.675 63.558 1.723 ;
     RECT  67.032 0.571 67.05 1.723 ;
     RECT  67.968 1.651 69.894 1.723 ;
     RECT  70.884 1.147 70.902 1.723 ;
     RECT  72.54 0.571 73.098 1.723 ;
     RECT  75.636 1.687 76.482 1.723 ;
     RECT  77.544 1.175 77.85 1.723 ;
     RECT  80.784 0.571 80.802 1.723 ;
     RECT  43.164 1.723 44.478 1.771 ;
     RECT  55.98 1.723 60.534 1.921 ;
     RECT  45.504 1.651 46.098 1.957 ;
     RECT  47.088 1.723 48.294 1.957 ;
     RECT  49.32 1.561 49.626 1.957 ;
     RECT  51.732 1.723 54.054 1.993 ;
     RECT  50.94 1.993 54.054 2.011 ;
     RECT  55.98 1.921 61.038 2.011 ;
     RECT  45.36 1.957 48.294 2.059 ;
     RECT  49.032 1.957 49.626 2.059 ;
     RECT  41.004 1.723 41.022 2.065 ;
     RECT  41.868 1.723 42.174 2.065 ;
     RECT  3.42 1.723 7.65 2.101 ;
     RECT  65.52 1.723 71.19 2.101 ;
     RECT  72.54 1.723 74.106 2.101 ;
     RECT  80.244 1.723 80.802 2.101 ;
     RECT  81.72 1.099 81.738 2.101 ;
     RECT  82.692 0.523 83.07 2.101 ;
     RECT  83.88 1.483 85.482 2.101 ;
     RECT  2.304 2.101 2.322 2.143 ;
     RECT  3.204 2.101 7.65 2.143 ;
     RECT  8.46 1.723 9.63 2.143 ;
     RECT  12.456 1.723 18.522 2.143 ;
     RECT  19.296 1.723 21.978 2.143 ;
     RECT  22.788 1.723 23.454 2.143 ;
     RECT  24.444 1.723 31.59 2.143 ;
     RECT  34.56 1.723 40.086 2.143 ;
     RECT  41.004 2.065 42.174 2.143 ;
     RECT  55.98 2.011 61.686 2.143 ;
     RECT  62.496 1.723 63.63 2.143 ;
     RECT  75.204 1.723 77.85 2.143 ;
     RECT  45.36 2.059 49.626 2.155 ;
     RECT  50.904 2.011 54.45 2.155 ;
     RECT  55.188 1.723 55.206 2.155 ;
     RECT  64.368 1.723 64.782 2.155 ;
     RECT  65.52 2.101 74.106 2.155 ;
     RECT  2.304 2.143 9.63 2.191 ;
     RECT  10.584 1.723 11.682 2.191 ;
     RECT  12.456 2.143 21.978 2.191 ;
     RECT  22.788 2.143 31.59 2.191 ;
     RECT  32.472 1.723 33.606 2.191 ;
     RECT  34.56 2.143 42.174 2.191 ;
     RECT  43.164 1.771 44.55 2.191 ;
     RECT  45.36 2.155 55.206 2.191 ;
     RECT  55.98 2.143 63.63 2.191 ;
     RECT  64.368 2.155 74.106 2.191 ;
     RECT  75.204 2.143 78.105 2.191 ;
     RECT  79.38 1.099 79.506 2.191 ;
     RECT  80.244 2.101 81.738 2.191 ;
     RECT  82.692 2.101 85.482 2.191 ;
     RECT  2.304 2.191 74.106 2.203 ;
     RECT  75.204 2.191 85.482 2.203 ;
     RECT  2.304 2.203 85.482 2.371 ;
     RECT  86.22 0.475 86.238 2.491 ;
     RECT  2.268 2.371 85.482 2.839 ;
     RECT  86.22 2.491 86.274 2.842 ;
     RECT  86.256 2.842 86.274 2.939 ;
     RECT  2.196 2.839 85.482 3.605 ;
     RECT  2.196 3.605 85.302 4.027 ;
     RECT  1.836 4.027 85.302 5.189 ;
     RECT  86.292 4.555 86.31 5.225 ;
     RECT  15.048 5.189 85.302 5.227 ;
     RECT  1.836 5.189 14.31 5.333 ;
     RECT  9.396 5.333 14.31 5.459 ;
     RECT  15.048 5.227 85.482 5.495 ;
     RECT  1.836 5.333 8.586 5.639 ;
     RECT  86.22 5.563 86.238 5.801 ;
     RECT  2.304 5.639 8.586 5.909 ;
     RECT  2.304 5.909 8.097 5.999 ;
     RECT  10.62 5.459 14.31 6.151 ;
     RECT  15.048 5.495 85.302 6.151 ;
     RECT  10.62 6.151 85.302 6.179 ;
     RECT  11.196 6.179 85.302 6.235 ;
     RECT  11.196 6.235 85.482 6.269 ;
     RECT  2.376 5.999 8.097 6.305 ;
     RECT  11.196 6.269 62.406 6.413 ;
     RECT  4.356 6.305 8.097 6.449 ;
     RECT  11.196 6.413 62.262 6.509 ;
     RECT  2.376 6.305 3.546 6.539 ;
     RECT  2.415 6.539 3.546 6.719 ;
     RECT  63.144 6.269 85.482 6.719 ;
     RECT  2.415 6.719 3.366 6.809 ;
     RECT  5.724 6.449 8.097 6.809 ;
     RECT  65.016 6.719 85.482 6.817 ;
     RECT  2.415 6.809 3.042 6.845 ;
     RECT  4.356 6.449 4.626 6.881 ;
     RECT  9.396 5.459 9.702 6.917 ;
     RECT  4.572 6.881 4.626 7.079 ;
     RECT  11.196 6.509 62.226 7.151 ;
     RECT  63.288 6.719 64.242 7.151 ;
     RECT  15.48 7.151 62.226 7.231 ;
     RECT  63.288 7.151 63.882 7.349 ;
     RECT  63.432 7.349 63.882 7.457 ;
     RECT  15.48 7.231 62.514 7.529 ;
     RECT  65.016 6.817 85.518 7.529 ;
     RECT  65.016 7.529 84.15 7.619 ;
     RECT  65.016 7.619 84.114 7.627 ;
     RECT  6.084 6.809 8.097 7.691 ;
     RECT  9.684 6.917 9.702 7.727 ;
     RECT  85.212 7.529 85.518 7.763 ;
     RECT  64.908 7.627 84.114 7.889 ;
     RECT  85.212 7.763 85.302 7.889 ;
     RECT  63.828 7.457 63.882 7.963 ;
     RECT  64.908 7.889 77.238 7.963 ;
     RECT  16.128 7.529 62.19 8.333 ;
     RECT  63.828 7.963 77.238 8.381 ;
     RECT  78.015 7.889 84.114 8.429 ;
     RECT  11.196 7.151 14.31 8.437 ;
     RECT  64.728 8.381 77.238 8.477 ;
     RECT  4.608 7.079 4.626 8.537 ;
     RECT  85.248 7.889 85.302 8.587 ;
     RECT  63.828 8.381 63.882 8.609 ;
     RECT  85.248 8.587 85.482 8.735 ;
     RECT  16.128 8.333 62.097 8.765 ;
     RECT  11.196 8.437 14.85 8.843 ;
     RECT  11.196 8.843 13.95 8.861 ;
     RECT  16.128 8.765 57.222 8.879 ;
     RECT  58.104 8.765 62.097 9.041 ;
     RECT  86.22 7.915 86.238 9.041 ;
     RECT  17.64 8.879 57.222 9.113 ;
     RECT  61.02 9.041 62.097 9.113 ;
     RECT  62.82 8.941 62.838 9.113 ;
     RECT  61.74 9.113 62.097 9.121 ;
     RECT  78.015 8.429 83.97 9.149 ;
     RECT  61.74 9.121 62.766 9.239 ;
     RECT  78.015 9.149 80.982 9.239 ;
     RECT  84.888 8.923 84.906 9.293 ;
     RECT  58.104 9.041 60.174 9.341 ;
     RECT  81.72 9.149 83.97 9.383 ;
     RECT  7.164 7.691 8.097 9.419 ;
     RECT  81.72 9.383 83.826 9.509 ;
     RECT  11.196 8.861 13.497 9.581 ;
     RECT  63.828 8.609 63.846 9.581 ;
     RECT  11.268 9.581 13.497 9.617 ;
     RECT  14.868 9.553 14.886 9.689 ;
     RECT  81.72 9.509 83.697 9.779 ;
     RECT  59.292 9.341 60.174 9.815 ;
     RECT  78.015 9.239 79.794 9.821 ;
     RECT  6.084 7.691 6.102 9.851 ;
     RECT  58.104 9.341 58.194 9.887 ;
     RECT  16.812 8.879 16.83 9.895 ;
     RECT  17.64 9.113 57.042 9.895 ;
     RECT  12.888 9.617 13.497 9.917 ;
     RECT  58.104 9.887 58.122 9.923 ;
     RECT  64.872 8.477 77.238 9.931 ;
     RECT  78.015 9.821 78.297 9.931 ;
     RECT  16.812 9.895 57.042 9.959 ;
     RECT  79.128 9.821 79.794 9.979 ;
     RECT  80.568 9.239 80.982 9.979 ;
     RECT  81.828 9.779 83.697 10.013 ;
     RECT  52.416 9.959 57.042 10.049 ;
     RECT  79.128 9.979 80.982 10.049 ;
     RECT  16.812 9.959 51.534 10.085 ;
     RECT  16.812 10.085 51.462 10.121 ;
     RECT  17.352 10.121 51.462 10.157 ;
     RECT  52.416 10.049 54.702 10.157 ;
     RECT  59.292 9.815 60.102 10.157 ;
     RECT  17.352 10.157 37.17 10.193 ;
     RECT  38.088 10.157 38.97 10.193 ;
     RECT  30.708 10.193 37.17 10.205 ;
     RECT  39.708 10.157 48.294 10.205 ;
     RECT  34.056 10.205 37.17 10.229 ;
     RECT  38.088 10.193 38.898 10.229 ;
     RECT  52.452 10.157 54.666 10.229 ;
     RECT  81.936 10.013 83.697 10.267 ;
     RECT  11.268 9.617 11.97 10.319 ;
     RECT  34.308 10.229 37.17 10.319 ;
     RECT  38.088 10.229 38.466 10.319 ;
     RECT  61.74 9.239 62.097 10.319 ;
     RECT  47.376 10.205 48.294 10.349 ;
     RECT  30.708 10.205 33.138 10.355 ;
     RECT  52.452 10.229 54.306 10.355 ;
     RECT  81.936 10.267 84.366 10.391 ;
     RECT  30.744 10.355 33.138 10.397 ;
     RECT  30.744 10.397 31.806 10.427 ;
     RECT  39.708 10.205 46.278 10.427 ;
     RECT  49.176 10.157 51.462 10.427 ;
     RECT  32.724 10.397 33.138 10.445 ;
     RECT  49.32 10.427 51.462 10.463 ;
     RECT  32.76 10.445 33.138 10.493 ;
     RECT  38.448 10.319 38.466 10.493 ;
     RECT  41.4 10.427 46.278 10.499 ;
     RECT  80.964 10.049 80.982 10.561 ;
     RECT  35.892 10.319 37.17 10.589 ;
     RECT  49.32 10.463 51.426 10.589 ;
     RECT  79.128 10.049 80.118 10.625 ;
     RECT  81.936 10.391 83.79 10.625 ;
     RECT  36.36 10.589 37.17 10.637 ;
     RECT  79.776 10.625 80.118 10.637 ;
     RECT  85.464 9.595 85.482 10.637 ;
     RECT  64.872 9.931 78.297 10.669 ;
     RECT  81.936 10.625 82.278 10.697 ;
     RECT  17.352 10.193 29.898 10.733 ;
     RECT  34.308 10.319 35.097 10.733 ;
     RECT  30.852 10.427 31.806 10.769 ;
     RECT  55.44 10.049 57.042 10.769 ;
     RECT  36.36 10.637 36.774 10.859 ;
     RECT  81.936 10.697 82.098 10.867 ;
     RECT  17.352 10.733 29.697 10.895 ;
     RECT  17.352 10.895 28.602 10.931 ;
     RECT  32.76 10.493 33.102 10.931 ;
     RECT  11.268 10.319 11.286 10.967 ;
     RECT  17.352 10.931 28.314 10.967 ;
     RECT  55.476 10.769 57.042 10.967 ;
     RECT  17.352 10.967 23.094 10.973 ;
     RECT  36.432 10.859 36.774 10.973 ;
     RECT  47.412 10.349 48.294 11.003 ;
     RECT  49.32 10.589 51.297 11.003 ;
     RECT  59.292 10.157 59.31 11.003 ;
     RECT  80.1 10.637 80.118 11.011 ;
     RECT  80.964 10.561 81.018 11.011 ;
     RECT  17.352 10.973 21.438 11.039 ;
     RECT  64.872 10.669 78.678 11.039 ;
     RECT  22.212 10.973 23.094 11.069 ;
     RECT  22.356 11.069 23.094 11.129 ;
     RECT  24.015 10.967 28.314 11.129 ;
     RECT  83.016 10.625 83.79 11.129 ;
     RECT  41.652 10.499 46.278 11.165 ;
     RECT  52.956 10.355 54.306 11.165 ;
     RECT  22.572 11.129 23.094 11.201 ;
     RECT  31.572 10.769 31.806 11.201 ;
     RECT  39.708 10.427 40.497 11.201 ;
     RECT  50.292 11.003 51.297 11.201 ;
     RECT  29.34 10.895 29.697 11.213 ;
     RECT  52.956 11.165 52.974 11.237 ;
     RECT  81.828 10.867 82.098 11.245 ;
     RECT  22.608 11.201 23.094 11.273 ;
     RECT  22.716 11.273 23.094 11.309 ;
     RECT  24.015 11.129 27.27 11.309 ;
     RECT  22.824 11.309 23.094 11.399 ;
     RECT  24.015 11.309 25.398 11.399 ;
     RECT  17.352 11.039 21.33 11.435 ;
     RECT  53.892 11.165 54.306 11.435 ;
     RECT  80.1 11.011 81.018 11.443 ;
     RECT  81.756 11.245 82.098 11.443 ;
     RECT  48.132 11.003 48.294 11.453 ;
     RECT  31.788 11.201 31.806 11.471 ;
     RECT  53.928 11.435 54.306 11.471 ;
     RECT  80.1 11.443 82.098 11.471 ;
     RECT  83.016 11.129 83.697 11.471 ;
     RECT  41.652 11.165 41.67 11.501 ;
     RECT  60.084 10.157 60.102 11.501 ;
     RECT  19.62 11.435 21.33 11.507 ;
     RECT  26.424 11.309 27.27 11.507 ;
     RECT  28.296 11.129 28.314 11.507 ;
     RECT  42.768 11.165 46.278 11.507 ;
     RECT  55.476 10.967 56.97 11.507 ;
     RECT  42.768 11.507 44.406 11.543 ;
     RECT  55.476 11.507 56.697 11.543 ;
     RECT  19.728 11.507 21.33 11.579 ;
     RECT  48.132 11.453 48.15 11.579 ;
     RECT  42.768 11.543 43.974 11.669 ;
     RECT  55.584 11.543 56.697 11.669 ;
     RECT  64.872 11.039 78.297 11.669 ;
     RECT  26.496 11.507 27.27 11.705 ;
     RECT  42.768 11.669 43.938 11.705 ;
     RECT  20.916 11.579 21.33 11.741 ;
     RECT  53.928 11.471 53.946 11.741 ;
     RECT  19.728 11.579 20.178 11.777 ;
     RECT  22.824 11.399 22.914 11.777 ;
     RECT  50.688 11.201 51.297 11.777 ;
     RECT  82.008 11.471 82.098 11.785 ;
     RECT  20.916 11.741 20.934 11.813 ;
     RECT  49.32 11.003 49.338 11.813 ;
     RECT  17.352 11.435 18.897 11.849 ;
     RECT  43.128 11.705 43.938 11.849 ;
     RECT  22.824 11.777 22.842 11.975 ;
     RECT  26.568 11.705 27.27 11.975 ;
     RECT  80.1 11.471 81.27 12.209 ;
     RECT  80.1 12.209 80.586 12.253 ;
     RECT  82.008 11.785 82.602 12.325 ;
     RECT  81.432 12.325 82.602 12.361 ;
     RECT  83.376 11.471 83.697 12.361 ;
     RECT  80.064 12.253 80.586 12.557 ;
     RECT  81.432 12.361 83.826 12.619 ;
     RECT  84.888 10.939 84.906 12.619 ;
     RECT  81.432 12.619 84.906 12.785 ;
     RECT  78.015 11.669 78.297 12.829 ;
     RECT  79.272 11.983 79.29 12.829 ;
     RECT  64.872 11.669 77.274 13.099 ;
     RECT  78.015 12.829 79.29 13.099 ;
     RECT  64.872 13.099 79.29 13.291 ;
     RECT  80.064 12.557 80.514 13.405 ;
     RECT  81.432 12.785 83.697 13.405 ;
     RECT  80.064 13.405 83.697 13.559 ;
     RECT  84.888 12.785 84.906 13.567 ;
     RECT  84.888 13.567 85.518 13.709 ;
     RECT  81.576 13.559 83.697 13.801 ;
     RECT  64.872 13.291 79.326 13.945 ;
     RECT  80.064 13.559 80.442 13.945 ;
     RECT  81.576 13.801 83.934 14.099 ;
     RECT  64.872 13.945 80.442 14.171 ;
     RECT  80.064 14.171 80.442 14.341 ;
     RECT  81.576 14.099 83.697 14.341 ;
     RECT  80.064 14.341 83.697 14.881 ;
     RECT  30.996 14.683 31.014 14.909 ;
     RECT  6.84 14.881 6.858 14.981 ;
     RECT  30.96 14.971 30.978 15.017 ;
     RECT  2.415 6.845 2.697 15.025 ;
     RECT  2.415 15.025 3.078 15.061 ;
     RECT  64.872 14.171 79.326 15.295 ;
     RECT  80.064 14.881 84.042 15.295 ;
     RECT  4.932 11.677 4.95 15.457 ;
     RECT  84.888 13.709 84.906 15.485 ;
     RECT  64.872 15.295 84.042 15.529 ;
     RECT  2.415 15.061 3.33 15.565 ;
     RECT  4.932 15.457 5.202 15.629 ;
     RECT  43.38 11.849 43.938 15.719 ;
     RECT  2.415 15.565 3.762 15.871 ;
     RECT  32.76 10.931 33.03 15.989 ;
     RECT  2.415 15.871 3.942 16.105 ;
     RECT  19.728 11.777 19.89 16.169 ;
     RECT  2.304 16.105 3.942 16.205 ;
     RECT  2.415 16.205 3.942 16.259 ;
     RECT  4.932 15.629 4.95 16.259 ;
     RECT  64.872 15.529 84.402 16.259 ;
     RECT  81.612 16.259 84.402 16.363 ;
     RECT  3.6 16.259 3.942 16.529 ;
     RECT  45.615 11.507 46.278 16.529 ;
     RECT  64.872 16.259 80.766 16.529 ;
     RECT  3.6 16.529 3.762 16.799 ;
     RECT  34.488 10.733 35.097 16.799 ;
     RECT  64.872 16.529 80.694 16.799 ;
     RECT  3.6 16.799 3.618 16.973 ;
     RECT  81.612 16.363 84.906 17.069 ;
     RECT  84.888 17.069 84.906 17.405 ;
     RECT  64.872 16.799 80.442 17.519 ;
     RECT  81.612 17.069 84.114 17.689 ;
     RECT  81.432 17.689 84.114 17.761 ;
     RECT  85.464 17.707 85.482 17.951 ;
     RECT  81.288 17.761 84.114 17.995 ;
     RECT  81.252 17.995 84.402 18.077 ;
     RECT  80.136 17.519 80.442 18.091 ;
     RECT  81.252 18.077 83.862 18.091 ;
     RECT  58.824 17.659 58.842 18.149 ;
     RECT  80.136 18.091 83.862 18.149 ;
     RECT  81.612 18.149 83.862 18.185 ;
     RECT  57.708 18.121 57.726 18.221 ;
     RECT  64.872 17.519 79.29 18.301 ;
     RECT  80.136 18.149 80.766 18.301 ;
     RECT  64.872 18.301 80.766 18.689 ;
     RECT  84.888 18.379 84.906 18.967 ;
     RECT  80.136 18.689 80.766 19.075 ;
     RECT  81.612 18.185 83.697 19.075 ;
     RECT  84.888 18.967 85.482 19.535 ;
     RECT  64.872 18.689 79.29 19.771 ;
     RECT  80.136 19.075 83.697 19.771 ;
     RECT  64.872 19.771 83.697 19.811 ;
     RECT  85.464 19.535 85.482 20.093 ;
     RECT  80.136 19.811 83.697 20.461 ;
     RECT  80.136 20.461 83.934 20.615 ;
     RECT  84.888 20.395 84.906 20.731 ;
     RECT  80.136 20.615 83.826 20.849 ;
     RECT  84.852 20.731 84.906 20.921 ;
     RECT  64.872 19.811 79.29 21.235 ;
     RECT  80.136 20.849 83.697 21.235 ;
     RECT  64.872 21.235 83.697 21.389 ;
     RECT  3.492 21.355 3.798 21.395 ;
     RECT  42.696 21.739 42.714 21.929 ;
     RECT  84.888 20.921 84.906 22.075 ;
     RECT  64.872 21.389 79.29 22.469 ;
     RECT  66.6 22.469 79.29 22.585 ;
     RECT  80.136 21.389 83.697 22.585 ;
     RECT  84.888 22.075 85.482 22.811 ;
     RECT  84.888 22.811 84.906 23.419 ;
     RECT  84.816 23.419 84.906 23.693 ;
     RECT  66.6 22.585 83.697 23.999 ;
     RECT  80.064 23.999 83.697 24.091 ;
     RECT  66.6 23.999 79.326 24.173 ;
     RECT  80.064 24.091 84.366 24.233 ;
     RECT  85.464 23.755 85.482 24.665 ;
     RECT  80.064 24.233 83.697 25.321 ;
     RECT  66.6 24.173 79.29 25.439 ;
     RECT  80.028 25.321 83.697 25.439 ;
     RECT  84.888 24.811 84.906 25.447 ;
     RECT  84.888 25.447 85.482 25.517 ;
     RECT  43.488 15.719 43.938 25.709 ;
     RECT  17.352 11.849 17.874 25.723 ;
     RECT  4.5 25.681 4.518 25.757 ;
     RECT  3.564 25.675 3.582 25.861 ;
     RECT  80.064 25.439 83.697 25.861 ;
     RECT  24.015 11.399 24.297 25.951 ;
     RECT  34.815 16.799 35.097 25.951 ;
     RECT  45.615 16.529 45.897 25.951 ;
     RECT  55.584 11.669 55.602 25.951 ;
     RECT  56.415 11.669 56.697 25.951 ;
     RECT  4.572 25.825 4.59 25.979 ;
     RECT  17.208 25.723 17.874 25.979 ;
     RECT  23.904 25.951 24.297 25.997 ;
     RECT  34.704 25.951 35.097 25.997 ;
     RECT  45.504 25.951 45.897 25.997 ;
     RECT  55.584 25.951 56.697 25.997 ;
     RECT  80.064 25.861 83.826 26.023 ;
     RECT  80.064 26.023 83.862 26.189 ;
     RECT  80.064 26.189 83.826 26.237 ;
     RECT  17.352 25.979 17.874 26.249 ;
     RECT  81.504 26.237 83.826 26.285 ;
     RECT  81.504 26.285 83.697 26.357 ;
     RECT  78.015 25.439 79.29 26.365 ;
     RECT  80.064 26.237 80.694 26.365 ;
     RECT  26.568 11.975 26.838 26.519 ;
     RECT  78.015 26.365 80.694 26.519 ;
     RECT  3.564 25.861 3.834 26.563 ;
     RECT  78.015 26.519 80.514 26.699 ;
     RECT  3.492 26.563 3.834 26.761 ;
     RECT  32.76 15.989 32.778 26.789 ;
     RECT  84.888 25.517 84.906 26.824 ;
     RECT  2.415 16.259 2.697 26.905 ;
     RECT  2.304 26.905 2.697 27.005 ;
     RECT  19.8 16.169 19.89 27.059 ;
     RECT  80.064 26.699 80.514 27.301 ;
     RECT  81.612 26.357 83.697 27.301 ;
     RECT  3.42 26.761 3.834 27.329 ;
     RECT  55.584 25.997 55.602 27.329 ;
     RECT  80.064 27.301 83.697 27.341 ;
     RECT  3.672 27.329 3.834 27.599 ;
     RECT  36.756 10.973 36.774 27.599 ;
     RECT  84.888 26.824 85.482 27.635 ;
     RECT  78.015 26.699 79.29 27.751 ;
     RECT  80.064 27.341 80.514 27.751 ;
     RECT  64.872 22.469 65.61 28.211 ;
     RECT  84.888 27.635 84.906 28.283 ;
     RECT  85.464 28.417 85.482 28.541 ;
     RECT  78.015 27.751 80.514 28.561 ;
     RECT  81.54 27.341 83.697 28.561 ;
     RECT  66.6 25.439 77.274 28.679 ;
     RECT  78.015 28.561 83.826 28.831 ;
     RECT  78.015 28.831 83.934 29.057 ;
     RECT  78.015 29.057 82.674 29.219 ;
     RECT  83.415 29.057 83.934 29.497 ;
     RECT  84.888 29.179 84.906 29.497 ;
     RECT  83.415 29.497 84.906 29.549 ;
     RECT  80.208 29.219 82.674 29.875 ;
     RECT  83.415 29.549 83.697 29.875 ;
     RECT  84.888 29.549 84.906 29.885 ;
     RECT  72.36 28.679 77.274 30.029 ;
     RECT  85.464 30.187 85.482 30.605 ;
     RECT  78.015 29.219 79.29 30.715 ;
     RECT  80.208 29.875 83.697 30.715 ;
     RECT  78.015 30.715 83.697 30.755 ;
     RECT  74.304 30.029 77.274 30.911 ;
     RECT  66.6 28.679 71.55 31.109 ;
     RECT  84.888 30.847 84.906 31.522 ;
     RECT  84.852 31.522 84.906 31.685 ;
     RECT  80.208 30.755 83.697 31.801 ;
     RECT  80.028 31.801 83.697 32.099 ;
     RECT  80.208 32.099 83.697 32.189 ;
     RECT  80.496 32.189 83.697 32.197 ;
     RECT  64.872 28.211 64.89 32.459 ;
     RECT  85.464 31.867 85.482 32.573 ;
     RECT  80.496 32.197 83.79 32.611 ;
     RECT  80.496 32.611 83.934 32.765 ;
     RECT  69.156 31.109 71.55 32.801 ;
     RECT  78.015 30.755 79.29 33.007 ;
     RECT  80.496 32.765 83.697 33.349 ;
     RECT  80.316 33.349 83.697 33.421 ;
     RECT  66.6 31.109 68.31 33.449 ;
     RECT  74.52 30.911 77.274 33.539 ;
     RECT  80.244 33.421 83.697 33.547 ;
     RECT  84.888 32.875 84.906 33.547 ;
     RECT  78.015 33.007 79.326 33.581 ;
     RECT  80.244 33.547 84.906 33.584 ;
     RECT  69.156 32.801 71.01 33.809 ;
     RECT  80.244 33.584 83.697 33.925 ;
     RECT  69.264 33.809 71.01 34.079 ;
     RECT  78.015 33.581 79.29 34.087 ;
     RECT  84.888 33.584 84.906 34.219 ;
     RECT  77.868 34.087 79.29 34.315 ;
     RECT  80.172 33.925 83.697 34.315 ;
     RECT  69.264 34.079 69.318 34.349 ;
     RECT  84.888 34.219 85.482 34.385 ;
     RECT  84.888 34.385 85.122 34.655 ;
     RECT  77.868 34.315 83.697 34.699 ;
     RECT  77.868 34.699 83.826 34.771 ;
     RECT  77.508 34.771 83.826 34.799 ;
     RECT  74.52 33.539 76.662 34.888 ;
     RECT  77.508 34.799 83.697 34.888 ;
     RECT  74.52 34.888 83.697 34.925 ;
     RECT  70.128 34.079 71.01 35.069 ;
     RECT  85.104 34.655 85.122 35.275 ;
     RECT  85.104 35.275 85.482 35.465 ;
     RECT  67.215 33.449 68.31 35.501 ;
     RECT  68.292 35.501 68.31 35.609 ;
     RECT  78.015 34.925 79.29 35.899 ;
     RECT  80.172 34.925 83.697 35.899 ;
     RECT  78.015 35.899 83.697 35.969 ;
     RECT  80.496 35.969 83.697 36.049 ;
     RECT  69.264 34.349 69.282 36.149 ;
     RECT  78.015 35.969 79.758 36.347 ;
     RECT  4.5 32.431 4.518 36.509 ;
     RECT  84.888 35.611 84.906 36.589 ;
     RECT  84.888 36.589 85.482 36.653 ;
     RECT  80.496 36.049 84.006 36.661 ;
     RECT  43.488 25.709 43.506 36.779 ;
     RECT  70.128 35.069 70.254 36.779 ;
     RECT  70.128 36.779 70.182 36.959 ;
     RECT  80.496 36.661 84.114 36.959 ;
     RECT  17.856 26.249 17.874 37.049 ;
     RECT  70.128 36.959 70.146 37.049 ;
     RECT  84.888 36.653 84.906 37.121 ;
     RECT  78.015 36.347 79.722 37.165 ;
     RECT  80.496 36.959 80.586 37.165 ;
     RECT  3.456 36.661 3.726 37.201 ;
     RECT  26.568 26.519 26.586 37.229 ;
     RECT  78.015 37.165 80.586 37.229 ;
     RECT  13.215 9.917 13.497 37.291 ;
     RECT  24.015 25.997 24.297 37.291 ;
     RECT  81.504 36.959 84.114 37.291 ;
     RECT  3.456 37.201 4.41 37.319 ;
     RECT  80.388 37.229 80.586 37.319 ;
     RECT  5.796 37.291 5.814 37.328 ;
     RECT  13.104 37.291 13.497 37.328 ;
     RECT  23.904 37.291 24.297 37.328 ;
     RECT  74.52 34.925 76.662 37.355 ;
     RECT  81.504 37.291 84.69 37.355 ;
     RECT  3.456 37.319 3.726 37.499 ;
     RECT  4.5 37.471 4.77 37.589 ;
     RECT  81.504 37.355 83.862 37.589 ;
     RECT  3.456 37.499 3.618 37.627 ;
     RECT  19.8 27.059 19.818 37.627 ;
     RECT  84.672 37.355 84.69 37.661 ;
     RECT  2.415 27.005 2.697 37.741 ;
     RECT  70.992 35.069 71.01 37.769 ;
     RECT  0.108 37.597 0.126 37.805 ;
     RECT  2.304 37.741 2.697 37.859 ;
     RECT  19.8 37.627 20.034 37.859 ;
     RECT  78.015 37.229 79.65 37.967 ;
     RECT  81.504 37.589 83.826 37.975 ;
     RECT  79.272 37.967 79.65 38.011 ;
     RECT  80.388 37.319 80.514 38.011 ;
     RECT  19.8 37.859 19.854 38.039 ;
     RECT  14.868 38.011 14.886 38.129 ;
     RECT  19.836 38.039 19.854 38.129 ;
     RECT  56.415 25.997 56.697 38.203 ;
     RECT  79.272 38.011 80.514 38.203 ;
     RECT  81.396 37.975 83.826 38.203 ;
     RECT  84.852 37.867 84.906 38.333 ;
     RECT  2.415 37.859 2.697 38.443 ;
     RECT  3.42 37.627 3.618 38.443 ;
     RECT  74.916 37.355 76.662 38.471 ;
     RECT  79.272 38.203 83.826 38.515 ;
     RECT  79.272 38.515 83.898 38.551 ;
     RECT  55.764 38.203 56.697 38.669 ;
     RECT  4.5 37.589 4.554 38.717 ;
     RECT  55.584 38.677 55.602 38.717 ;
     RECT  79.272 38.551 84.042 38.717 ;
     RECT  78.015 37.967 78.297 38.821 ;
     RECT  2.415 38.443 3.618 38.849 ;
     RECT  2.415 38.849 3.438 38.939 ;
     RECT  4.5 38.717 4.518 38.939 ;
     RECT  84.888 38.333 84.906 39.083 ;
     RECT  78.015 38.821 78.498 39.091 ;
     RECT  79.272 38.717 83.934 39.091 ;
     RECT  74.916 38.471 74.934 39.119 ;
     RECT  86.292 39.211 86.31 39.341 ;
     RECT  72.36 30.029 73.386 39.353 ;
     RECT  72.615 39.353 73.386 39.389 ;
     RECT  78.015 39.091 83.934 39.451 ;
     RECT  78.015 39.451 84.402 39.677 ;
     RECT  76.104 38.471 76.662 39.749 ;
     RECT  85.536 39.793 85.554 39.865 ;
     RECT  72.615 39.389 73.062 40.019 ;
     RECT  78.015 39.677 84.114 40.405 ;
     RECT  77.472 40.405 84.114 40.445 ;
     RECT  78.015 40.445 84.114 40.469 ;
     RECT  79.272 40.469 84.114 40.559 ;
     RECT  76.644 39.749 76.662 40.631 ;
     RECT  80.244 40.559 84.114 40.739 ;
     RECT  2.415 38.939 2.697 40.787 ;
     RECT  7.815 9.419 8.097 40.787 ;
     RECT  13.215 37.328 13.497 40.787 ;
     RECT  18.615 11.849 18.897 40.787 ;
     RECT  24.015 37.328 24.297 40.787 ;
     RECT  29.415 11.213 29.697 40.787 ;
     RECT  34.815 25.997 35.097 40.787 ;
     RECT  40.215 11.201 40.497 40.787 ;
     RECT  45.615 25.997 45.897 40.787 ;
     RECT  51.015 11.777 51.297 40.787 ;
     RECT  56.415 38.669 56.697 40.787 ;
     RECT  61.815 10.319 62.097 40.787 ;
     RECT  67.215 35.501 67.497 40.787 ;
     RECT  72.615 40.019 72.897 40.787 ;
     RECT  78.015 40.469 78.297 40.787 ;
     RECT  80.244 40.739 80.874 40.829 ;
     RECT  81.828 40.739 84.114 40.829 ;
     RECT  79.272 40.559 79.326 40.865 ;
     RECT  81.864 40.829 83.79 40.865 ;
     RECT  85.464 39.865 85.554 40.909 ;
     RECT  79.272 40.865 79.29 40.937 ;
     RECT  80.532 40.829 80.874 40.973 ;
     RECT  80.856 40.973 80.874 41.009 ;
     RECT  81.864 40.865 82.242 41.009 ;
     RECT  84.888 40.909 85.554 41.021 ;
     RECT  2.415 40.787 2.505 41.057 ;
     RECT  7.815 40.787 7.905 41.057 ;
     RECT  13.215 40.787 13.305 41.057 ;
     RECT  18.615 40.787 18.705 41.057 ;
     RECT  24.015 40.787 24.105 41.057 ;
     RECT  29.415 40.787 29.505 41.057 ;
     RECT  34.815 40.787 34.905 41.057 ;
     RECT  40.215 40.787 40.305 41.057 ;
     RECT  45.615 40.787 45.705 41.057 ;
     RECT  51.015 40.787 51.105 41.057 ;
     RECT  56.415 40.787 56.505 41.057 ;
     RECT  61.815 40.787 61.905 41.057 ;
     RECT  67.215 40.787 67.305 41.057 ;
     RECT  72.615 40.787 72.705 41.057 ;
     RECT  78.015 40.787 78.105 41.057 ;
     RECT  83.415 40.865 83.79 41.057 ;
     RECT  83.772 41.057 83.79 42.029 ;
     RECT  85.464 41.021 85.554 42.365 ;
     RECT  82.224 41.009 82.242 42.701 ;
     RECT  85.464 42.365 85.482 43.037 ;
    LAYER M4 ;
     RECT  0.469 5.376 1.141 5.784 ;
     RECT  0.133 3.984 1.477 4.008 ;
     RECT  1.141 5.136 1.477 5.784 ;
     RECT  1.477 3.984 2.149 5.784 ;
     RECT  2.149 3.984 2.293 5.832 ;
     RECT  2.293 3.936 2.408 5.832 ;
     RECT  0.181 21.744 2.408 21.768 ;
     RECT  2.408 2.148 2.512 41.052 ;
     RECT  2.512 2.418 2.704 40.782 ;
     RECT  2.485 1.152 3.155 1.176 ;
     RECT  3.205 0.096 3.449 0.12 ;
     RECT  2.704 37.632 3.539 37.656 ;
     RECT  2.704 16.272 3.629 16.968 ;
     RECT  3.629 16.944 3.635 16.968 ;
     RECT  2.704 25.68 3.731 25.704 ;
     RECT  2.704 4.224 3.737 5.832 ;
     RECT  2.704 2.88 3.769 2.904 ;
     RECT  2.704 21.36 3.809 21.768 ;
     RECT  3.769 2.736 4.201 2.904 ;
     RECT  3.737 4.224 4.201 5.4 ;
     RECT  4.201 2.736 4.277 5.4 ;
     RECT  3.869 1.728 4.565 1.752 ;
     RECT  4.277 2.88 4.997 5.064 ;
     RECT  4.997 3.408 5.069 5.064 ;
     RECT  5.173 1.104 5.516 1.128 ;
     RECT  5.516 0.528 5.603 1.128 ;
     RECT  5.069 3.408 6.041 4.92 ;
     RECT  6.533 0.096 6.617 0.12 ;
     RECT  6.041 4.128 6.689 4.92 ;
     RECT  5.603 1.104 6.947 1.128 ;
     RECT  6.689 4.416 7.261 4.92 ;
     RECT  6.145 2.256 7.585 2.28 ;
     RECT  7.261 3.312 7.669 3.336 ;
     RECT  7.261 4.416 7.669 5.064 ;
     RECT  7.585 2.016 7.808 2.28 ;
     RECT  7.669 3.312 7.808 5.064 ;
     RECT  3.809 21.744 7.808 21.768 ;
     RECT  4.489 25.728 7.808 25.752 ;
     RECT  5.785 37.296 7.808 37.32 ;
     RECT  4.525 38.688 7.808 38.712 ;
     RECT  7.808 2.016 7.912 41.052 ;
     RECT  7.912 2.016 8.104 40.782 ;
     RECT  8.104 3.312 8.381 3.96 ;
     RECT  8.104 4.992 8.669 5.064 ;
     RECT  7.573 0.576 8.885 0.6 ;
     RECT  8.381 3.936 9.097 3.96 ;
     RECT  8.669 4.992 9.097 5.016 ;
     RECT  9.097 3.936 9.137 5.016 ;
     RECT  8.245 1.728 9.641 1.752 ;
     RECT  9.925 2.88 10.501 2.904 ;
     RECT  9.137 3.936 10.501 4.92 ;
     RECT  10.261 1.152 10.613 1.176 ;
     RECT  10.565 0.096 10.649 0.12 ;
     RECT  10.501 2.88 10.937 4.92 ;
     RECT  10.925 1.728 11.605 1.752 ;
     RECT  11.605 1.152 11.693 1.752 ;
     RECT  11.693 1.728 11.761 1.752 ;
     RECT  10.937 3.696 11.837 4.92 ;
     RECT  11.761 1.728 11.987 2.28 ;
     RECT  12.581 0.096 12.665 0.12 ;
     RECT  11.837 4.416 13.093 4.92 ;
     RECT  11.987 1.728 13.208 1.752 ;
     RECT  13.093 4.416 13.208 5.064 ;
     RECT  12.877 9.888 13.208 9.912 ;
     RECT  8.104 21.744 13.208 21.768 ;
     RECT  8.104 25.728 13.208 25.752 ;
     RECT  8.104 37.296 13.208 37.32 ;
     RECT  8.104 38.688 13.208 38.712 ;
     RECT  13.208 1.728 13.285 41.052 ;
     RECT  13.285 1.152 13.312 41.052 ;
     RECT  13.312 1.152 13.385 40.782 ;
     RECT  13.385 1.728 13.504 40.782 ;
     RECT  13.669 0.096 13.997 0.12 ;
     RECT  13.504 4.08 14.569 5.064 ;
     RECT  14.341 0.576 14.717 0.6 ;
     RECT  14.569 4.032 14.819 5.064 ;
     RECT  14.819 4.032 14.933 4.968 ;
     RECT  13.504 1.728 15.013 1.752 ;
     RECT  15.013 1.152 15.149 1.752 ;
     RECT  15.149 1.68 15.401 1.752 ;
     RECT  15.401 1.68 15.731 1.704 ;
     RECT  16.945 2.256 17.075 2.28 ;
     RECT  13.504 8.832 17.089 8.856 ;
     RECT  17.089 8.736 17.129 8.856 ;
     RECT  13.504 25.728 17.237 25.752 ;
     RECT  16.021 0.576 17.701 0.6 ;
     RECT  17.089 6.288 17.881 6.312 ;
     RECT  14.933 4.08 17.917 4.968 ;
     RECT  17.881 6 17.917 6.312 ;
     RECT  17.129 8.736 18.025 8.76 ;
     RECT  17.917 4.08 18.061 6.312 ;
     RECT  17.701 0.576 18.209 1.176 ;
     RECT  18.209 0.576 18.605 0.6 ;
     RECT  18.385 1.68 18.608 2.04 ;
     RECT  18.061 4.08 18.608 7.128 ;
     RECT  18.025 8.208 18.608 8.76 ;
     RECT  13.504 9.888 18.608 9.912 ;
     RECT  17.881 10.944 18.608 10.968 ;
     RECT  13.504 21.744 18.608 21.768 ;
     RECT  13.504 37.296 18.608 37.32 ;
     RECT  13.504 38.688 18.608 38.712 ;
     RECT  18.608 1.68 18.712 41.052 ;
     RECT  18.712 1.68 18.904 40.782 ;
     RECT  18.904 1.68 19.325 1.752 ;
     RECT  18.904 37.296 20.005 37.32 ;
     RECT  20.005 37.296 20.089 37.656 ;
     RECT  19.325 1.728 20.717 1.752 ;
     RECT  20.717 1.152 20.801 1.752 ;
     RECT  18.904 2.928 20.977 11.016 ;
     RECT  20.801 1.728 21.305 1.752 ;
     RECT  21.397 0.096 21.989 0.12 ;
     RECT  22.733 1.728 22.817 1.752 ;
     RECT  23.036 0.528 23.123 0.552 ;
     RECT  23.381 0.096 23.465 0.12 ;
     RECT  20.977 2.928 23.965 11.448 ;
     RECT  23.965 2.88 24.008 11.448 ;
     RECT  18.904 21.744 24.008 21.768 ;
     RECT  18.904 25.968 24.008 25.992 ;
     RECT  20.089 37.296 24.008 37.32 ;
     RECT  18.904 38.688 24.008 38.712 ;
     RECT  24.008 2.148 24.112 41.052 ;
     RECT  24.112 2.148 24.304 40.782 ;
     RECT  24.304 2.88 24.362 11.448 ;
     RECT  24.085 0.576 24.473 0.6 ;
     RECT  24.469 1.728 24.805 1.752 ;
     RECT  24.805 1.152 25.625 1.752 ;
     RECT  24.362 2.928 25.793 11.448 ;
     RECT  25.793 2.832 25.877 11.448 ;
     RECT  25.877 3.024 26.413 11.448 ;
     RECT  26.485 0.576 26.957 0.6 ;
     RECT  26.413 3.024 27.173 11.496 ;
     RECT  25.625 1.728 27.217 1.752 ;
     RECT  27.169 0.528 27.829 0.552 ;
     RECT  27.829 0.096 27.929 0.552 ;
     RECT  27.173 3.024 28.501 11.448 ;
     RECT  28.165 0.576 28.901 0.6 ;
     RECT  28.501 2.304 29.173 11.448 ;
     RECT  29.173 1.728 29.408 11.448 ;
     RECT  24.304 21.744 29.408 21.768 ;
     RECT  24.304 25.968 29.408 25.992 ;
     RECT  24.304 37.296 29.408 37.32 ;
     RECT  24.304 38.688 29.408 38.712 ;
     RECT  29.408 1.728 29.512 41.052 ;
     RECT  29.512 1.728 29.704 40.782 ;
     RECT  29.704 1.728 30.853 1.752 ;
     RECT  30.949 14.976 30.956 15 ;
     RECT  30.853 1.152 31.025 1.752 ;
     RECT  30.956 14.784 31.043 15 ;
     RECT  29.704 2.928 31.561 11.448 ;
     RECT  31.189 0.144 31.619 0.168 ;
     RECT  31.025 1.728 31.765 1.752 ;
     RECT  31.561 2.832 31.765 11.448 ;
     RECT  31.765 1.728 32.197 11.448 ;
     RECT  32.197 1.152 32.501 11.448 ;
     RECT  32.501 1.728 33.617 11.448 ;
     RECT  33.617 2.64 34.808 11.448 ;
     RECT  31.043 14.976 34.808 15 ;
     RECT  29.704 21.744 34.808 21.768 ;
     RECT  29.704 25.968 34.808 25.992 ;
     RECT  29.704 37.296 34.808 37.32 ;
     RECT  29.704 38.688 34.808 38.712 ;
     RECT  34.808 2.148 34.912 41.052 ;
     RECT  34.912 2.148 35.104 40.782 ;
     RECT  35.104 2.148 35.261 11.448 ;
     RECT  35.261 1.728 35.885 11.448 ;
     RECT  34.213 0.096 36.205 0.12 ;
     RECT  36.205 0.096 36.593 0.552 ;
     RECT  36.593 0.096 36.677 0.6 ;
     RECT  35.885 2.64 37.285 11.448 ;
     RECT  37.285 1.728 37.613 11.448 ;
     RECT  37.621 1.152 37.763 1.176 ;
     RECT  36.677 0.096 38.189 0.12 ;
     RECT  38.293 0.528 38.477 0.6 ;
     RECT  38.477 0.528 38.675 0.552 ;
     RECT  37.613 2.64 38.725 11.448 ;
     RECT  38.725 1.872 39.596 11.448 ;
     RECT  39.596 1.68 40.057 11.448 ;
     RECT  39.973 0.096 40.133 0.12 ;
     RECT  40.057 1.104 40.208 11.448 ;
     RECT  35.104 14.976 40.208 15 ;
     RECT  35.104 21.744 40.208 21.768 ;
     RECT  35.104 25.968 40.208 25.992 ;
     RECT  35.104 38.688 40.208 38.712 ;
     RECT  40.208 1.104 40.312 41.052 ;
     RECT  40.312 1.104 40.355 40.782 ;
     RECT  40.355 1.728 40.504 40.782 ;
     RECT  40.504 1.728 41.641 11.448 ;
     RECT  41.641 1.728 41.857 11.496 ;
     RECT  41.857 1.68 42.371 11.496 ;
     RECT  40.504 21.744 42.725 21.768 ;
     RECT  40.504 14.976 43.859 15 ;
     RECT  43.801 21.648 43.885 21.672 ;
     RECT  42.371 1.728 44.449 11.496 ;
     RECT  44.449 1.104 44.723 11.496 ;
     RECT  45.349 0.096 45.605 0.12 ;
     RECT  44.723 1.728 45.605 11.496 ;
     RECT  45.605 1.872 45.608 11.496 ;
     RECT  43.813 18.192 45.608 18.216 ;
     RECT  40.504 25.968 45.608 25.992 ;
     RECT  40.504 38.688 45.608 38.712 ;
     RECT  45.608 1.872 45.712 41.052 ;
     RECT  45.712 1.872 45.904 40.782 ;
     RECT  45.904 1.872 46.741 11.496 ;
     RECT  46.741 1.728 47.036 11.496 ;
     RECT  47.036 1.104 47.123 11.496 ;
     RECT  47.123 1.728 47.765 11.496 ;
     RECT  47.765 1.776 47.873 11.496 ;
     RECT  48.085 0.576 48.305 0.6 ;
     RECT  47.873 1.824 49.093 11.496 ;
     RECT  49.093 1.152 49.235 11.496 ;
     RECT  49.235 1.728 49.565 11.496 ;
     RECT  49.565 1.824 50.773 11.496 ;
     RECT  50.773 1.728 51.008 11.496 ;
     RECT  45.904 18.192 51.008 18.216 ;
     RECT  45.904 25.968 51.008 25.992 ;
     RECT  45.904 38.688 51.008 38.712 ;
     RECT  51.008 1.728 51.112 41.052 ;
     RECT  51.112 1.728 51.304 40.782 ;
     RECT  51.304 1.728 51.761 10.488 ;
     RECT  52.117 0.096 52.337 0.12 ;
     RECT  51.761 1.776 52.789 10.488 ;
     RECT  52.789 1.152 52.931 10.488 ;
     RECT  53.017 0.528 53.171 0.552 ;
     RECT  52.931 1.728 54.065 10.488 ;
     RECT  54.065 1.824 55.133 10.488 ;
     RECT  51.304 38.688 55.753 38.712 ;
     RECT  55.133 1.728 56.408 10.488 ;
     RECT  51.304 11.472 56.408 11.496 ;
     RECT  51.304 18.192 56.408 18.216 ;
     RECT  51.304 25.968 56.408 25.992 ;
     RECT  55.753 38.208 56.408 38.712 ;
     RECT  56.408 1.728 56.512 41.052 ;
     RECT  56.512 1.728 56.704 40.782 ;
     RECT  56.485 0.576 56.837 0.6 ;
     RECT  56.704 18.192 57.737 18.216 ;
     RECT  58.213 0.576 58.529 0.6 ;
     RECT  58.813 17.664 58.897 17.688 ;
     RECT  56.704 1.728 59.321 10.488 ;
     RECT  59.525 0.576 59.609 0.6 ;
     RECT  56.704 11.472 60.113 11.496 ;
     RECT  59.321 1.824 60.505 10.488 ;
     RECT  60.505 1.104 60.611 10.488 ;
     RECT  59.893 0.096 60.947 0.12 ;
     RECT  60.611 1.68 61.808 10.488 ;
     RECT  56.704 25.968 61.808 25.992 ;
     RECT  61.808 1.68 61.912 41.052 ;
     RECT  61.912 1.68 62.104 40.782 ;
     RECT  62.104 1.68 62.245 10.488 ;
     RECT  62.245 1.584 62.561 10.488 ;
     RECT  62.917 0.576 63.065 0.6 ;
     RECT  62.561 1.824 63.529 10.488 ;
     RECT  63.529 1.68 63.971 10.488 ;
     RECT  62.104 25.968 64.595 25.992 ;
     RECT  63.971 1.728 66.673 10.488 ;
     RECT  66.949 0.576 67.061 0.6 ;
     RECT  66.673 1.824 67.208 10.488 ;
     RECT  67.208 1.824 67.312 41.052 ;
     RECT  67.312 1.824 67.504 40.782 ;
     RECT  67.504 1.824 67.661 10.488 ;
     RECT  67.661 1.728 69.013 10.488 ;
     RECT  69.013 1.152 70.225 10.488 ;
     RECT  70.225 1.152 70.373 10.824 ;
     RECT  70.373 1.152 70.913 10.488 ;
     RECT  70.913 1.728 71.201 10.488 ;
     RECT  72.373 0.096 72.529 0.12 ;
     RECT  72.529 0.096 72.605 0.552 ;
     RECT  71.201 2.208 72.608 10.488 ;
     RECT  71.077 14.448 72.608 14.472 ;
     RECT  71.893 37.872 72.608 37.896 ;
     RECT  72.608 2.148 72.712 41.052 ;
     RECT  72.605 0.528 72.755 0.552 ;
     RECT  72.712 2.148 72.904 40.782 ;
     RECT  72.904 14.352 73.001 14.472 ;
     RECT  73.025 0.576 73.109 0.6 ;
     RECT  72.904 2.148 73.381 10.488 ;
     RECT  73.381 1.728 74.653 10.488 ;
     RECT  74.653 1.728 74.981 10.632 ;
     RECT  75.397 0.096 75.665 0.12 ;
     RECT  74.981 1.728 75.881 6.696 ;
     RECT  76.405 0.576 76.493 0.6 ;
     RECT  74.981 7.728 76.709 10.632 ;
     RECT  75.881 1.728 76.957 6.6 ;
     RECT  76.957 1.728 76.961 6.648 ;
     RECT  77.533 0.48 77.713 0.504 ;
     RECT  77.713 0.48 77.797 1.176 ;
     RECT  76.961 2.544 78.008 6.648 ;
     RECT  76.709 7.728 78.008 8.568 ;
     RECT  76.709 9.792 78.008 10.632 ;
     RECT  76.993 11.952 78.008 11.976 ;
     RECT  77.461 13.296 78.008 13.32 ;
     RECT  73.001 14.352 78.008 14.376 ;
     RECT  77.353 34.896 78.008 34.92 ;
     RECT  72.904 37.872 78.008 37.896 ;
     RECT  77.461 40.416 78.008 40.44 ;
     RECT  78.008 2.148 78.112 41.052 ;
     RECT  77.797 0.48 78.131 0.552 ;
     RECT  78.112 2.418 78.304 40.782 ;
     RECT  78.131 0.48 78.515 0.504 ;
     RECT  78.304 25.488 78.659 26.232 ;
     RECT  78.304 15.888 79.283 15.912 ;
     RECT  78.304 18.72 79.283 18.744 ;
     RECT  78.304 2.496 79.285 8.568 ;
     RECT  78.304 9.792 79.285 10.632 ;
     RECT  78.659 25.488 79.285 25.512 ;
     RECT  79.285 25.248 79.331 25.512 ;
     RECT  79.292 33.552 79.333 33.576 ;
     RECT  78.304 34.896 79.333 34.92 ;
     RECT  78.304 13.296 79.337 13.32 ;
     RECT  79.285 24.144 79.372 24.168 ;
     RECT  79.333 33.552 79.379 34.92 ;
     RECT  79.369 0.528 79.436 0.552 ;
     RECT  78.304 37.872 79.477 37.896 ;
     RECT  79.436 0.528 79.523 1.128 ;
     RECT  78.304 40.416 79.553 40.44 ;
     RECT  79.379 34.32 79.573 34.92 ;
     RECT  79.285 2.496 79.621 10.632 ;
     RECT  79.58 30.72 79.621 30.744 ;
     RECT  79.573 34.32 79.66 35.928 ;
     RECT  79.621 30.24 79.667 30.744 ;
     RECT  78.304 31.92 79.667 31.944 ;
     RECT  79.66 34.32 79.697 35.736 ;
     RECT  78.304 17.088 79.769 17.112 ;
     RECT  79.621 2.208 79.805 10.632 ;
     RECT  79.523 0.528 79.859 0.552 ;
     RECT  79.805 2.208 80.149 10.008 ;
     RECT  80.149 1.728 80.273 10.008 ;
     RECT  79.331 25.248 80.521 25.272 ;
     RECT  80.521 25.248 80.561 25.704 ;
     RECT  79.477 37.248 80.597 37.896 ;
     RECT  80.273 2.112 80.633 10.008 ;
     RECT  80.561 25.68 80.665 25.704 ;
     RECT  80.557 31.776 80.684 31.8 ;
     RECT  80.597 37.872 80.701 37.896 ;
     RECT  78.304 39.312 80.701 39.336 ;
     RECT  80.684 31.776 80.725 31.896 ;
     RECT  78.304 19.776 80.777 19.8 ;
     RECT  79.697 34.32 80.777 34.344 ;
     RECT  80.701 37.872 80.809 39.336 ;
     RECT  80.521 40.368 80.809 40.392 ;
     RECT  80.485 0.576 80.813 0.6 ;
     RECT  80.557 22.224 80.917 22.248 ;
     RECT  78.304 14.352 80.921 14.376 ;
     RECT  80.917 21.648 80.963 22.248 ;
     RECT  80.341 12.528 80.965 12.552 ;
     RECT  80.665 25.68 80.993 26.232 ;
     RECT  79.477 23.376 81.212 23.4 ;
     RECT  79.667 30.24 81.212 30.264 ;
     RECT  79.697 35.712 81.253 35.736 ;
     RECT  80.633 2.208 81.281 10.008 ;
     RECT  81.212 23.376 81.281 24.36 ;
     RECT  81.212 30 81.299 30.264 ;
     RECT  81.253 35.328 81.313 35.736 ;
     RECT  81.308 19.104 81.395 19.416 ;
     RECT  80.725 31.776 81.425 32.52 ;
     RECT  80.963 21.648 81.445 21.912 ;
     RECT  80.965 12.528 81.453 13.512 ;
     RECT  81.445 21.072 81.491 21.912 ;
     RECT  81.299 30.24 81.569 30.264 ;
     RECT  80.773 18.096 81.713 18.12 ;
     RECT  80.809 37.872 81.733 40.392 ;
     RECT  81.313 35.328 81.749 36.648 ;
     RECT  80.773 15.408 81.817 15.432 ;
     RECT  81.425 32.496 81.817 32.52 ;
     RECT  81.281 2.256 81.857 10.008 ;
     RECT  81.817 15.024 81.857 15.432 ;
     RECT  81.395 19.392 81.857 19.416 ;
     RECT  81.491 21.072 81.857 21.096 ;
     RECT  81.709 1.104 81.875 1.128 ;
     RECT  81.733 37.872 81.877 40.536 ;
     RECT  81.281 24.288 81.925 24.36 ;
     RECT  80.993 25.68 81.925 25.704 ;
     RECT  81.749 36.624 81.925 36.648 ;
     RECT  81.877 37.872 81.925 40.68 ;
     RECT  81.857 9.696 82.067 9.72 ;
     RECT  81.925 24.288 82.067 25.704 ;
     RECT  81.925 13.584 82.069 13.608 ;
     RECT  81.857 2.256 82.109 8.712 ;
     RECT  80.989 27.312 82.109 27.336 ;
     RECT  81.453 12.528 82.115 12.552 ;
     RECT  81.817 32.496 82.117 33.048 ;
     RECT  82.033 34.8 82.117 34.824 ;
     RECT  82.117 32.496 82.163 34.824 ;
     RECT  82.163 33.936 82.204 34.248 ;
     RECT  82.261 16.224 82.348 16.248 ;
     RECT  82.163 32.496 82.361 32.52 ;
     RECT  81.925 36.624 82.433 40.68 ;
     RECT  82.109 2.256 82.597 8.616 ;
     RECT  82.681 0.144 83.041 0.168 ;
     RECT  82.597 2.208 83.408 8.616 ;
     RECT  82.069 13.584 83.408 13.656 ;
     RECT  81.857 15.024 83.408 15.048 ;
     RECT  82.067 24.288 83.408 24.312 ;
     RECT  82.067 25.68 83.408 25.704 ;
     RECT  79.477 28.896 83.408 28.92 ;
     RECT  83.173 33.024 83.408 33.048 ;
     RECT  82.204 34.224 83.408 34.248 ;
     RECT  82.433 36.624 83.408 40.584 ;
     RECT  82.165 41.664 83.408 41.688 ;
     RECT  83.041 0.144 83.509 0.552 ;
     RECT  83.408 2.148 83.509 41.688 ;
     RECT  83.509 0.144 83.704 41.688 ;
     RECT  83.704 41.664 83.761 41.688 ;
     RECT  82.213 42.672 83.761 42.696 ;
     RECT  83.704 5.808 83.765 7.752 ;
     RECT  83.765 5.808 83.837 6.12 ;
     RECT  83.765 7.2 83.873 7.752 ;
     RECT  83.704 38.64 83.873 40.68 ;
     RECT  83.704 0.144 83.945 2.568 ;
     RECT  83.704 3.696 83.945 3.72 ;
     RECT  83.873 7.248 84.125 7.752 ;
     RECT  83.873 38.688 84.125 40.68 ;
     RECT  83.945 0.144 84.149 2.184 ;
     RECT  83.704 24.096 84.805 24.12 ;
     RECT  83.704 32.208 84.841 32.232 ;
     RECT  83.704 37.296 84.841 37.656 ;
     RECT  84.125 38.688 84.841 39.672 ;
     RECT  83.837 5.904 84.877 5.928 ;
     RECT  84.125 7.248 84.877 7.272 ;
     RECT  83.704 10.272 84.877 10.296 ;
     RECT  83.704 12.624 84.877 12.648 ;
     RECT  83.704 15.024 84.877 17.064 ;
     RECT  83.704 18.048 84.877 18.072 ;
     RECT  84.841 20.736 84.877 20.76 ;
     RECT  84.805 23.424 84.877 24.12 ;
     RECT  83.704 26.16 84.877 26.184 ;
     RECT  83.704 28.848 84.877 29.544 ;
     RECT  84.841 31.536 84.877 32.232 ;
     RECT  83.704 33.552 84.877 33.576 ;
     RECT  84.841 37.296 84.877 39.672 ;
     RECT  84.125 40.656 84.877 40.68 ;
     RECT  83.761 41.664 84.877 42.696 ;
     RECT  84.949 4.224 84.985 4.248 ;
     RECT  84.877 30.864 85.093 34.584 ;
     RECT  84.877 35.616 85.093 39.672 ;
     RECT  84.877 8.928 85.237 9.288 ;
     RECT  84.149 0.096 85.241 2.184 ;
     RECT  85.241 0.144 85.453 2.184 ;
     RECT  84.985 3.888 85.453 4.248 ;
     RECT  84.877 5.904 85.453 7.272 ;
     RECT  85.237 8.256 85.453 9.288 ;
     RECT  84.877 10.272 85.453 19.416 ;
     RECT  84.877 20.4 85.453 29.88 ;
     RECT  85.093 30.864 85.453 39.672 ;
     RECT  84.877 40.656 85.453 42.696 ;
     RECT  85.453 5.232 85.489 7.272 ;
     RECT  85.453 8.256 85.489 43.032 ;
     RECT  85.453 0.144 86.281 4.248 ;
     RECT  85.489 5.232 86.281 43.032 ;
     RECT  86.281 0.144 86.364 43.032 ;
    LAYER M5 ;
     RECT  0.144 0.016 86.232 0.131 ;
     RECT  85.536 0.131 86.232 0.467 ;
     RECT  85.536 0.467 85.896 0.515 ;
     RECT  22.08 0.131 59.592 0.563 ;
     RECT  60.576 0.131 83.88 0.563 ;
     RECT  85.536 0.515 85.56 0.563 ;
     RECT  0.144 0.131 21.096 0.611 ;
     RECT  23.76 0.563 27.192 0.611 ;
     RECT  28.176 0.563 35.64 0.611 ;
     RECT  36.624 0.563 59.592 0.611 ;
     RECT  73.056 0.563 77.784 0.611 ;
     RECT  0.144 0.611 15.72 1.139 ;
     RECT  17.04 0.611 21.096 1.139 ;
     RECT  38.976 0.611 59.256 1.139 ;
     RECT  60.576 0.563 72.072 1.139 ;
     RECT  78.816 0.563 83.544 1.139 ;
     RECT  7.248 1.139 15.72 1.187 ;
     RECT  17.04 1.139 17.736 1.187 ;
     RECT  23.76 0.611 26.184 1.187 ;
     RECT  28.512 0.611 35.64 1.187 ;
     RECT  10.944 1.187 15.72 1.715 ;
     RECT  61.248 1.139 72.072 1.715 ;
     RECT  0.144 1.139 4.92 1.763 ;
     RECT  7.248 1.187 9.96 1.763 ;
     RECT  10.944 1.715 15.384 1.763 ;
     RECT  18.72 1.139 21.096 1.763 ;
     RECT  22.08 0.563 22.776 1.763 ;
     RECT  23.76 1.187 24.504 1.763 ;
     RECT  25.488 1.187 26.184 1.763 ;
     RECT  27.168 0.611 27.192 1.763 ;
     RECT  28.512 1.187 30.552 1.763 ;
     RECT  31.536 1.187 35.64 1.763 ;
     RECT  37.296 0.611 37.752 1.763 ;
     RECT  40.656 1.139 59.256 1.763 ;
     RECT  61.584 1.715 72.072 1.763 ;
     RECT  73.392 0.611 77.784 1.763 ;
     RECT  40.656 1.763 44.376 1.811 ;
     RECT  45.456 1.763 52.92 1.811 ;
     RECT  67.2 1.763 69.384 1.811 ;
     RECT  38.976 1.139 39.672 1.861 ;
     RECT  18.72 1.763 20.088 2.137 ;
     RECT  38.736 1.861 39.672 2.137 ;
     RECT  40.656 1.811 43.656 2.137 ;
     RECT  71.376 1.763 72.072 2.137 ;
     RECT  77.088 1.763 77.784 2.137 ;
     RECT  78.816 1.139 79.176 2.137 ;
     RECT  80.16 1.139 83.544 2.151 ;
     RECT  48.432 1.811 52.92 2.195 ;
     RECT  54.144 1.763 54.84 2.195 ;
     RECT  61.584 1.763 63.288 2.195 ;
     RECT  64.944 1.763 64.968 2.195 ;
     RECT  77.088 2.137 79.176 2.197 ;
     RECT  80.16 2.151 83.712 2.197 ;
     RECT  74.4 1.763 74.76 2.243 ;
     RECT  6.24 1.139 6.264 2.291 ;
     RECT  7.248 1.763 8.112 2.291 ;
     RECT  11.952 1.763 11.976 2.291 ;
     RECT  17.04 1.187 17.064 2.291 ;
     RECT  75.744 1.763 75.768 2.291 ;
     RECT  28.512 1.763 29.712 2.339 ;
     RECT  31.584 1.763 35.112 2.339 ;
     RECT  61.584 2.195 62.112 2.339 ;
     RECT  71.376 2.137 72.912 2.339 ;
     RECT  45.456 1.811 47.208 2.725 ;
     RECT  63.264 2.195 63.288 2.771 ;
     RECT  37.728 1.763 37.752 2.773 ;
     RECT  38.736 2.137 43.656 2.773 ;
     RECT  45.072 2.725 47.208 2.773 ;
     RECT  52.464 2.195 52.92 2.773 ;
     RECT  54.816 2.195 54.84 2.773 ;
     RECT  55.824 1.763 57.576 2.773 ;
     RECT  74.4 2.243 74.424 2.819 ;
     RECT  25.824 1.763 25.848 2.867 ;
     RECT  4.56 1.763 4.92 2.915 ;
     RECT  9.936 1.763 9.96 2.915 ;
     RECT  52.464 2.773 53.16 3.061 ;
     RECT  37.728 2.773 43.656 3.155 ;
     RECT  70.368 1.763 70.392 3.157 ;
     RECT  71.376 2.339 71.4 3.157 ;
     RECT  7.8 2.291 8.112 3.301 ;
     RECT  18.6 2.137 20.088 3.301 ;
     RECT  22.08 1.763 22.44 3.301 ;
     RECT  44.832 2.773 47.208 3.301 ;
     RECT  48.768 2.195 51.312 3.301 ;
     RECT  52.464 3.061 53.208 3.349 ;
     RECT  37.728 3.155 41.304 3.397 ;
     RECT  54.816 2.773 57.576 3.397 ;
     RECT  54.624 3.397 57.576 3.443 ;
     RECT  4.896 2.915 4.92 3.491 ;
     RECT  60.432 3.253 60.456 3.491 ;
     RECT  48.768 3.301 51.48 3.541 ;
     RECT  52.464 3.349 53.304 3.541 ;
     RECT  29.4 2.339 29.712 3.589 ;
     RECT  23.76 1.763 24.312 3.685 ;
     RECT  28.656 3.589 29.712 3.781 ;
     RECT  33.216 2.339 35.112 3.923 ;
     RECT  18.6 3.301 20.568 3.925 ;
     RECT  21.888 3.301 22.44 3.925 ;
     RECT  18.6 3.925 22.44 3.971 ;
     RECT  34.8 3.923 35.112 3.973 ;
     RECT  44.832 3.301 47.448 3.973 ;
     RECT  48.768 3.541 53.304 3.973 ;
     RECT  67.2 1.811 68.76 3.973 ;
     RECT  0.144 1.763 3.576 4.019 ;
     RECT  58.752 1.763 58.92 4.019 ;
     RECT  33.216 3.923 33.24 4.021 ;
     RECT  18.6 3.971 20.088 4.067 ;
     RECT  33.024 4.021 33.24 4.067 ;
     RECT  23.52 3.685 24.312 4.069 ;
     RECT  77.088 2.197 83.712 4.115 ;
     RECT  31.584 2.339 31.8 4.165 ;
     RECT  28.656 3.781 30.024 4.211 ;
     RECT  23.52 4.069 24.408 4.213 ;
     RECT  25.488 3.973 25.512 4.213 ;
     RECT  34.8 3.973 35.784 4.213 ;
     RECT  37.056 3.397 41.304 4.213 ;
     RECT  21.072 3.971 22.44 4.259 ;
     RECT  42.336 3.155 43.656 4.261 ;
     RECT  61.8 2.339 62.112 4.261 ;
     RECT  21.072 4.259 21.912 4.307 ;
     RECT  23.52 4.213 25.512 4.307 ;
     RECT  28.656 4.211 29.712 4.357 ;
     RECT  20.064 4.067 20.088 4.403 ;
     RECT  28.512 4.357 29.712 4.405 ;
     RECT  34.8 4.213 41.304 4.501 ;
     RECT  42.336 4.261 43.704 4.501 ;
     RECT  23.808 4.307 25.512 4.549 ;
     RECT  0.48 4.019 3.576 4.643 ;
     RECT  54.624 3.443 57.288 4.643 ;
     RECT  7.68 3.301 8.112 4.691 ;
     RECT  76.032 3.541 76.056 4.691 ;
     RECT  2.16 4.643 3.576 4.739 ;
     RECT  23.808 4.549 25.992 4.741 ;
     RECT  55.296 4.643 57.288 4.789 ;
     RECT  58.752 4.019 58.872 4.789 ;
     RECT  13.2 1.763 13.512 4.885 ;
     RECT  34.8 4.501 43.704 4.933 ;
     RECT  44.832 3.973 53.304 4.933 ;
     RECT  70.368 3.157 71.4 4.981 ;
     RECT  72.6 2.339 72.912 4.981 ;
     RECT  60.672 4.261 62.112 5.029 ;
     RECT  13.104 4.885 13.512 5.075 ;
     RECT  14.784 4.117 14.808 5.075 ;
     RECT  55.296 4.789 58.872 5.077 ;
     RECT  60.672 5.029 62.616 5.125 ;
     RECT  0.48 4.643 1.176 5.171 ;
     RECT  23.808 4.741 26.664 5.173 ;
     RECT  27.744 4.405 29.712 5.173 ;
     RECT  34.8 4.933 53.304 5.267 ;
     RECT  31.008 4.165 31.8 5.269 ;
     RECT  34.8 5.267 51.432 5.269 ;
     RECT  55.296 5.077 59.16 5.269 ;
     RECT  60.48 5.125 62.616 5.269 ;
     RECT  23.808 5.173 29.712 5.317 ;
     RECT  52.464 5.267 53.304 5.317 ;
     RECT  55.296 5.269 62.616 5.363 ;
     RECT  0.48 5.171 0.84 5.365 ;
     RECT  67.104 3.973 68.76 5.365 ;
     RECT  21.072 4.307 21.384 5.461 ;
     RECT  22.608 5.269 22.632 5.461 ;
     RECT  67.104 5.365 69.048 5.507 ;
     RECT  55.296 5.363 62.424 5.603 ;
     RECT  34.224 5.269 51.432 5.651 ;
     RECT  55.296 5.603 60.744 5.651 ;
     RECT  33.024 4.067 33.048 5.699 ;
     RECT  0.192 5.365 0.84 5.747 ;
     RECT  70.368 4.981 72.912 5.747 ;
     RECT  67.104 5.507 68.76 5.749 ;
     RECT  0.192 5.747 0.504 5.795 ;
     RECT  34.224 5.651 47.208 5.795 ;
     RECT  55.296 5.651 59.592 5.795 ;
     RECT  78 4.115 83.712 5.795 ;
     RECT  52.464 5.317 53.688 5.797 ;
     RECT  2.16 4.739 3.528 5.843 ;
     RECT  60.672 5.651 60.744 5.843 ;
     RECT  23.808 5.317 29.832 5.893 ;
     RECT  55.296 5.795 59.112 5.987 ;
     RECT  63.6 5.749 63.624 5.987 ;
     RECT  64.992 6.085 65.016 6.133 ;
     RECT  70.416 5.747 71.112 6.179 ;
     RECT  23.664 5.893 29.832 6.229 ;
     RECT  30.96 5.269 31.8 6.229 ;
     RECT  64.032 6.133 65.016 6.275 ;
     RECT  23.664 6.229 31.8 6.323 ;
     RECT  34.224 5.795 46.776 6.323 ;
     RECT  78 5.795 79.416 6.323 ;
     RECT  67.056 5.749 68.76 6.325 ;
     RECT  76.896 5.653 76.92 6.371 ;
     RECT  48.192 5.651 51.432 6.373 ;
     RECT  52.464 5.797 53.88 6.373 ;
     RECT  34.224 6.323 46.536 6.421 ;
     RECT  23.664 6.323 31.032 6.515 ;
     RECT  66.912 6.325 68.76 6.515 ;
     RECT  21.072 5.461 22.632 6.517 ;
     RECT  32.88 6.181 32.904 6.611 ;
     RECT  48.192 6.373 53.88 6.661 ;
     RECT  21.024 6.517 22.632 6.803 ;
     RECT  67.008 6.515 68.76 6.803 ;
     RECT  79.296 6.323 79.416 6.805 ;
     RECT  47.76 6.661 53.88 6.851 ;
     RECT  58.848 5.987 59.112 6.853 ;
     RECT  64.032 6.275 64.056 6.899 ;
     RECT  80.448 5.795 83.712 6.899 ;
     RECT  60.72 5.843 60.744 6.947 ;
     RECT  27.888 6.515 31.032 6.995 ;
     RECT  23.664 6.515 26.472 7.043 ;
     RECT  34.08 6.421 46.536 7.043 ;
     RECT  58.848 6.853 59.448 7.043 ;
     RECT  55.296 5.987 57.288 7.045 ;
     RECT  79.296 6.805 79.464 7.045 ;
     RECT  80.448 6.899 81.96 7.045 ;
     RECT  21.024 6.803 21.048 7.091 ;
     RECT  55.104 7.045 57.288 7.187 ;
     RECT  36.48 7.043 46.536 7.235 ;
     RECT  55.584 7.187 57.288 7.285 ;
     RECT  52.656 6.851 53.88 7.333 ;
     RECT  71.088 6.179 71.112 7.333 ;
     RECT  72.6 5.747 72.912 7.333 ;
     RECT  27.888 6.995 29.88 7.379 ;
     RECT  34.08 7.043 35.208 7.381 ;
     RECT  38.592 7.235 46.536 7.381 ;
     RECT  83.184 6.899 83.712 7.475 ;
     RECT  65.28 7.429 65.304 7.525 ;
     RECT  52.656 7.333 54.408 7.571 ;
     RECT  36.48 7.235 37.224 7.667 ;
     RECT  60.384 7.429 60.408 7.667 ;
     RECT  65.184 7.525 65.304 7.667 ;
     RECT  67.008 6.803 68.376 7.667 ;
     RECT  83.28 7.475 83.712 7.667 ;
     RECT  67.008 7.667 67.848 7.669 ;
     RECT  38.592 7.381 46.92 7.715 ;
     RECT  52.656 7.571 53.832 7.715 ;
     RECT  23.664 7.043 25.512 7.763 ;
     RECT  33.984 7.381 35.208 7.765 ;
     RECT  22.08 6.803 22.632 7.859 ;
     RECT  38.592 7.715 46.248 7.859 ;
     RECT  33.168 7.765 35.208 7.861 ;
     RECT  23.664 7.763 25.464 7.907 ;
     RECT  55.584 7.285 57.576 7.907 ;
     RECT  22.224 7.859 22.632 7.909 ;
     RECT  48.144 6.851 51.528 7.957 ;
     RECT  22.224 7.909 22.68 8.003 ;
     RECT  66.576 7.669 67.848 8.003 ;
     RECT  30.96 6.995 31.032 8.099 ;
     RECT  79.296 7.045 81.96 8.099 ;
     RECT  33.072 7.861 35.208 8.147 ;
     RECT  38.736 7.859 46.248 8.147 ;
     RECT  33.984 8.147 35.208 8.149 ;
     RECT  36.48 7.667 37.08 8.195 ;
     RECT  33.984 8.149 35.352 8.291 ;
     RECT  43.872 8.147 46.248 8.291 ;
     RECT  28.512 7.379 29.88 8.341 ;
     RECT  36.672 8.195 37.08 8.435 ;
     RECT  28.512 8.341 30.024 8.483 ;
     RECT  53.04 7.715 53.832 8.483 ;
     RECT  67.2 8.003 67.848 8.531 ;
     RECT  47.904 7.957 51.528 8.533 ;
     RECT  38.736 8.147 42.888 8.579 ;
     RECT  47.472 8.533 51.528 8.579 ;
     RECT  28.512 8.483 29.712 8.627 ;
     RECT  47.472 8.579 49.128 8.627 ;
     RECT  22.32 8.003 22.68 8.629 ;
     RECT  23.664 7.907 25.416 8.629 ;
     RECT  39.792 8.579 42.888 8.723 ;
     RECT  55.584 7.907 57 8.723 ;
     RECT  50.496 8.579 51.528 8.725 ;
     RECT  55.584 8.723 56.808 8.725 ;
     RECT  22.32 8.629 25.416 8.771 ;
     RECT  39.792 8.723 41.016 8.771 ;
     RECT  47.472 8.627 49.032 8.771 ;
     RECT  53.28 8.483 53.832 8.771 ;
     RECT  53.808 8.771 53.832 8.819 ;
     RECT  50.496 8.725 51.96 8.867 ;
     RECT  55.056 8.725 56.808 8.915 ;
     RECT  47.568 8.771 49.032 8.963 ;
     RECT  29.184 8.627 29.712 9.011 ;
     RECT  37.056 8.435 37.08 9.011 ;
     RECT  22.32 8.771 22.68 9.059 ;
     RECT  44.352 8.291 46.248 9.059 ;
     RECT  33.984 8.291 35.256 9.107 ;
     RECT  39.792 8.771 40.776 9.107 ;
     RECT  22.656 9.059 22.68 9.155 ;
     RECT  23.856 8.771 25.416 9.203 ;
     RECT  24 9.203 25.416 9.205 ;
     RECT  55.248 8.915 56.808 9.299 ;
     RECT  47.568 8.963 47.928 9.347 ;
     RECT  48.96 8.963 49.032 9.347 ;
     RECT  61.8 5.603 62.424 9.347 ;
     RECT  29.28 9.011 29.712 9.395 ;
     RECT  24 9.205 25.704 9.491 ;
     RECT  38.736 8.579 38.76 9.587 ;
     RECT  42.096 8.723 42.888 9.587 ;
     RECT  44.352 9.059 46.008 9.587 ;
     RECT  50.496 8.867 51.432 9.587 ;
     RECT  24 9.491 25.608 9.635 ;
     RECT  79.296 8.099 81 9.731 ;
     RECT  82.032 8.293 82.056 9.731 ;
     RECT  39.984 9.107 40.776 9.829 ;
     RECT  42.096 9.587 42.792 9.829 ;
     RECT  39.984 9.829 42.792 9.875 ;
     RECT  55.248 9.299 56.712 9.923 ;
     RECT  49.008 9.347 49.032 9.971 ;
     RECT  24 9.635 25.224 10.019 ;
     RECT  40.2 9.875 42.792 10.019 ;
     RECT  80.4 9.731 81 10.019 ;
     RECT  42.288 10.019 42.792 10.115 ;
     RECT  44.352 9.587 44.376 10.163 ;
     RECT  47.568 9.347 47.592 10.163 ;
     RECT  40.2 10.019 40.776 10.403 ;
     RECT  21.6 9.589 21.624 10.547 ;
     RECT  79.296 9.731 79.32 10.595 ;
     RECT  24 10.019 25.128 10.931 ;
     RECT  50.496 9.587 51.312 10.931 ;
     RECT  42.768 10.115 42.792 10.979 ;
     RECT  22.8 9.973 22.824 11.123 ;
     RECT  78 6.323 78.312 11.941 ;
     RECT  77.472 11.941 78.312 13.331 ;
     RECT  80.976 10.019 81 13.477 ;
     RECT  82.08 12.517 82.104 13.477 ;
     RECT  80.976 13.477 82.104 13.523 ;
     RECT  81.36 13.523 82.104 13.667 ;
     RECT  71.088 7.333 72.912 14.483 ;
     RECT  31.008 8.099 31.032 14.819 ;
     RECT  81.36 13.667 81.384 15.013 ;
     RECT  78 13.331 78.312 15.877 ;
     RECT  81.36 15.013 82.296 16.259 ;
     RECT  2.4 5.843 3.528 16.933 ;
     RECT  58.848 7.043 58.872 17.699 ;
     RECT  78 15.877 79.272 19.811 ;
     RECT  81.36 16.259 81.384 21.061 ;
     RECT  2.4 16.933 3.624 21.349 ;
     RECT  81.36 21.061 81.48 21.637 ;
     RECT  43.824 14.965 43.848 21.683 ;
     RECT  0.192 5.795 0.216 21.779 ;
     RECT  80.928 21.637 81.48 21.923 ;
     RECT  80.928 21.923 81.384 22.259 ;
     RECT  81.36 22.259 81.384 24.277 ;
     RECT  81.36 24.277 82.056 24.325 ;
     RECT  81.264 24.325 82.056 25.139 ;
     RECT  78 19.811 78.312 25.477 ;
     RECT  79.296 24.133 79.32 25.477 ;
     RECT  78 25.477 79.32 25.523 ;
     RECT  2.4 21.349 3.72 25.715 ;
     RECT  64.56 8.341 64.584 26.003 ;
     RECT  78 25.523 78.648 26.243 ;
     RECT  81.264 25.139 81.288 27.301 ;
     RECT  81.264 27.301 81.528 28.931 ;
     RECT  81.264 28.931 81.288 31.861 ;
     RECT  79.632 30.229 79.656 31.955 ;
     RECT  80.736 31.861 81.288 32.531 ;
     RECT  81.264 32.531 81.288 33.013 ;
     RECT  83.4 7.667 83.712 33.013 ;
     RECT  83.184 33.013 83.712 34.259 ;
     RECT  79.344 33.541 79.368 34.355 ;
     RECT  81.264 33.013 82.152 34.835 ;
     RECT  81.264 34.835 81.384 35.363 ;
     RECT  79.584 34.885 79.608 37.283 ;
     RECT  33.984 9.107 35.112 37.331 ;
     RECT  83.4 34.259 83.712 37.429 ;
     RECT  81.36 35.363 81.384 37.477 ;
     RECT  82.512 37.429 83.712 37.477 ;
     RECT  2.4 25.715 3.528 37.667 ;
     RECT  20.016 8.389 20.04 37.667 ;
     RECT  71.904 14.483 72.912 37.907 ;
     RECT  55.776 9.923 56.712 38.243 ;
     RECT  81.36 37.477 83.712 39.061 ;
     RECT  80.928 39.061 83.712 39.923 ;
     RECT  81.408 39.923 83.712 40.019 ;
     RECT  81.744 40.019 83.712 40.499 ;
     RECT  81.744 40.499 82.2 40.547 ;
     RECT  83.184 40.499 83.712 40.547 ;
     RECT  83.28 40.547 83.712 40.595 ;
     RECT  81.888 40.547 82.2 40.691 ;
     RECT  2.4 37.667 2.712 41.049 ;
     RECT  7.8 4.691 8.112 41.049 ;
     RECT  13.2 5.075 13.512 41.049 ;
     RECT  18.6 4.067 18.912 41.049 ;
     RECT  24 10.931 24.312 41.049 ;
     RECT  29.4 9.395 29.712 41.049 ;
     RECT  34.8 37.331 35.112 41.049 ;
     RECT  40.2 10.403 40.512 41.049 ;
     RECT  45.6 9.587 45.912 41.049 ;
     RECT  51 10.931 51.312 41.049 ;
     RECT  56.4 38.243 56.712 41.049 ;
     RECT  61.8 9.347 62.112 41.049 ;
     RECT  67.2 8.531 67.512 41.049 ;
     RECT  72.6 37.907 72.912 41.049 ;
     RECT  78 26.243 78.312 41.049 ;
     RECT  83.4 40.595 83.712 41.049 ;
     RECT  2.4 41.049 2.52 41.063 ;
     RECT  7.8 41.049 7.92 41.063 ;
     RECT  13.2 41.049 13.32 41.063 ;
     RECT  18.6 41.049 18.72 41.063 ;
     RECT  24 41.049 24.12 41.063 ;
     RECT  29.4 41.049 29.52 41.063 ;
     RECT  34.8 41.049 34.92 41.063 ;
     RECT  40.2 41.049 40.32 41.063 ;
     RECT  45.6 41.049 45.72 41.063 ;
     RECT  51 41.049 51.12 41.063 ;
     RECT  56.4 41.049 56.52 41.063 ;
     RECT  61.8 41.049 61.92 41.063 ;
     RECT  67.2 41.049 67.32 41.063 ;
     RECT  72.6 41.049 72.72 41.063 ;
     RECT  78 41.049 78.12 41.063 ;
     RECT  83.4 41.049 83.52 41.063 ;
     RECT  82.176 40.691 82.2 41.699 ;
     RECT  21.144 0.131 21.36 0.132 ;
     RECT  21.48 0.131 21.696 0.132 ;
     RECT  21.816 0.131 22.032 0.132 ;
     RECT  59.64 0.131 59.856 0.132 ;
     RECT  59.976 0.131 60.192 0.132 ;
     RECT  60.312 0.131 60.528 0.132 ;
     RECT  21.096 0.132 22.08 1.763 ;
     RECT  59.592 0.132 60.576 0.611 ;
     RECT  22.776 0.563 23.76 1.763 ;
     RECT  27.192 0.563 28.176 0.611 ;
     RECT  35.64 0.563 36.624 0.611 ;
     RECT  72.072 0.563 73.056 0.611 ;
     RECT  77.784 0.563 78.816 2.137 ;
     RECT  15.72 0.611 17.04 1.715 ;
     RECT  26.184 0.611 27.168 1.763 ;
     RECT  27.192 0.611 28.512 1.763 ;
     RECT  37.752 0.611 38.976 1.861 ;
     RECT  59.256 0.611 60.576 1.139 ;
     RECT  72.072 0.611 73.392 1.763 ;
     RECT  4.92 1.139 6.24 2.291 ;
     RECT  6.264 1.139 7.248 2.291 ;
     RECT  17.736 1.139 18.72 1.187 ;
     RECT  39.672 1.139 40.656 2.137 ;
     RECT  79.176 1.139 80.16 2.197 ;
     RECT  9.96 1.187 10.944 1.763 ;
     RECT  18.6 1.187 18.72 2.137 ;
     RECT  24.504 1.187 25.488 1.763 ;
     RECT  30.552 1.187 31.536 1.763 ;
     RECT  3.576 1.763 4.56 2.915 ;
     RECT  11.976 1.763 13.2 2.291 ;
     RECT  22.44 1.763 23.76 3.685 ;
     RECT  24.312 1.763 25.824 2.867 ;
     RECT  44.376 1.763 45.456 1.811 ;
     RECT  52.92 1.763 54.144 2.195 ;
     RECT  54.84 1.763 55.824 2.773 ;
     RECT  57.576 1.763 58.752 3.443 ;
     RECT  58.92 1.763 59.256 3.253 ;
     RECT  69.384 1.763 70.368 1.811 ;
     RECT  70.392 1.763 71.376 3.157 ;
     RECT  72.072 1.763 74.4 2.137 ;
     RECT  74.76 1.763 75.744 2.243 ;
     RECT  75.768 1.763 77.088 2.291 ;
     RECT  43.656 1.811 45.456 2.725 ;
     RECT  47.208 1.811 48.432 2.195 ;
     RECT  37.752 1.861 38.736 2.773 ;
     RECT  72.912 2.137 74.4 2.819 ;
     RECT  47.208 2.195 48.768 3.301 ;
     RECT  51.312 2.195 52.464 3.301 ;
     RECT  52.92 2.195 54.816 2.773 ;
     RECT  62.112 2.195 63.264 2.771 ;
     RECT  74.424 2.243 75.744 2.291 ;
     RECT  7.68 2.291 7.8 3.301 ;
     RECT  76.032 2.291 77.088 3.541 ;
     RECT  28.656 2.339 29.4 3.589 ;
     RECT  31.8 2.339 33.216 4.021 ;
     RECT  61.584 2.339 61.8 3.253 ;
     RECT  71.4 2.339 72.6 4.981 ;
     RECT  43.656 2.725 45.072 2.773 ;
     RECT  43.656 2.773 44.832 4.261 ;
     RECT  53.16 2.773 54.816 3.061 ;
     RECT  24.312 2.867 25.512 3.973 ;
     RECT  3.576 2.915 4.896 3.491 ;
     RECT  53.208 3.061 54.816 3.349 ;
     RECT  41.304 3.155 42.336 4.501 ;
     RECT  58.92 3.253 60.432 3.491 ;
     RECT  60.456 3.253 61.8 3.491 ;
     RECT  20.568 3.301 21.888 3.925 ;
     RECT  47.448 3.301 48.768 3.973 ;
     RECT  51.48 3.301 52.464 3.541 ;
     RECT  53.304 3.349 54.816 3.397 ;
     RECT  53.304 3.397 54.624 4.643 ;
     RECT  57.288 3.443 58.752 4.789 ;
     RECT  60.672 3.491 61.8 4.261 ;
     RECT  76.056 3.541 77.088 4.115 ;
     RECT  22.44 3.685 23.52 4.259 ;
     RECT  33.24 3.923 34.8 4.067 ;
     RECT  20.088 3.971 21.072 4.403 ;
     RECT  24.312 3.973 25.488 4.069 ;
     RECT  35.784 3.973 37.056 4.213 ;
     RECT  0.192 4.019 0.48 5.328 ;
     RECT  58.872 4.019 58.92 5.077 ;
     RECT  31.8 4.021 33.024 5.699 ;
     RECT  18.912 4.067 20.064 4.403 ;
     RECT  33.048 4.067 34.8 5.269 ;
     RECT  24.408 4.069 25.488 4.213 ;
     RECT  13.512 4.117 14.784 5.075 ;
     RECT  30.024 4.165 31.008 4.211 ;
     RECT  29.712 4.211 31.008 5.269 ;
     RECT  21.912 4.259 23.52 4.307 ;
     RECT  43.704 4.261 44.832 4.933 ;
     RECT  21.384 4.307 23.808 5.269 ;
     RECT  1.176 4.643 2.16 5.171 ;
     RECT  53.304 4.643 55.296 5.317 ;
     RECT  26.664 4.741 27.744 5.173 ;
     RECT  59.16 5.077 60.672 5.125 ;
     RECT  59.16 5.125 60.48 5.269 ;
     RECT  0.84 5.171 2.16 5.747 ;
     RECT  51.432 5.267 52.464 6.373 ;
     RECT  21.384 5.269 22.608 5.461 ;
     RECT  22.632 5.269 23.808 5.893 ;
     RECT  29.712 5.269 30.96 5.317 ;
     RECT  33.048 5.269 34.224 5.699 ;
     RECT  29.832 5.317 30.96 6.229 ;
     RECT  53.688 5.317 55.296 5.797 ;
     RECT  62.424 5.363 62.616 5.749 ;
     RECT  69.048 5.365 70.368 5.507 ;
     RECT  60.744 5.603 61.8 6.947 ;
     RECT  47.208 5.651 48.192 5.795 ;
     RECT  59.592 5.651 60.672 5.795 ;
     RECT  76.92 5.653 78 6.371 ;
     RECT  31.8 5.699 34.224 6.181 ;
     RECT  71.112 5.747 72.6 7.333 ;
     RECT  62.424 5.749 63.6 5.987 ;
     RECT  46.776 5.795 48.192 6.323 ;
     RECT  59.112 5.795 60.672 5.843 ;
     RECT  79.416 5.795 80.448 6.805 ;
     RECT  53.88 5.797 55.296 7.045 ;
     RECT  59.112 5.843 60.72 6.853 ;
     RECT  22.632 5.893 23.664 7.909 ;
     RECT  57.288 5.987 58.848 7.285 ;
     RECT  31.8 6.181 32.88 6.323 ;
     RECT  32.904 6.181 34.224 6.421 ;
     RECT  46.536 6.323 48.192 6.661 ;
     RECT  78.312 6.323 79.296 10.595 ;
     RECT  32.904 6.421 34.08 6.611 ;
     RECT  26.472 6.515 27.888 7.043 ;
     RECT  66.912 6.515 67.008 7.669 ;
     RECT  33.072 6.611 34.08 7.381 ;
     RECT  46.536 6.661 47.76 6.851 ;
     RECT  21.048 6.803 22.08 7.091 ;
     RECT  79.464 6.805 80.448 7.045 ;
     RECT  46.536 6.851 48.144 7.381 ;
     RECT  51.528 6.851 52.656 7.715 ;
     RECT  59.448 6.853 60.72 6.947 ;
     RECT  81.96 6.899 83.184 7.475 ;
     RECT  59.448 6.947 61.8 7.043 ;
     RECT  29.88 6.995 30.96 8.099 ;
     RECT  35.208 7.043 36.48 8.149 ;
     RECT  58.872 7.043 61.8 7.429 ;
     RECT  53.88 7.045 55.104 7.187 ;
     RECT  53.88 7.187 55.584 7.333 ;
     RECT  37.224 7.235 38.592 7.667 ;
     RECT  57.576 7.285 58.848 7.907 ;
     RECT  54.408 7.333 55.584 7.571 ;
     RECT  33.072 7.381 33.984 7.765 ;
     RECT  46.92 7.381 48.144 7.715 ;
     RECT  58.872 7.429 60.384 7.667 ;
     RECT  60.408 7.429 61.8 7.667 ;
     RECT  81.96 7.475 83.28 7.667 ;
     RECT  53.832 7.571 55.584 8.725 ;
     RECT  37.08 7.667 38.592 7.859 ;
     RECT  81.96 7.667 83.4 8.099 ;
     RECT  46.248 7.715 48.144 7.957 ;
     RECT  51.528 7.715 53.04 8.483 ;
     RECT  25.464 7.763 25.512 7.907 ;
     RECT  33.072 7.765 33.168 7.861 ;
     RECT  25.416 7.907 25.512 9.205 ;
     RECT  22.68 7.909 23.664 8.629 ;
     RECT  46.248 7.957 47.904 8.533 ;
     RECT  29.88 8.099 31.008 8.341 ;
     RECT  81 8.099 83.4 8.293 ;
     RECT  42.888 8.147 43.872 8.291 ;
     RECT  35.352 8.149 36.48 8.195 ;
     RECT  35.352 8.195 36.672 8.291 ;
     RECT  35.256 8.291 36.672 8.435 ;
     RECT  42.888 8.291 44.352 9.587 ;
     RECT  81 8.293 82.032 9.731 ;
     RECT  82.056 8.293 83.4 9.731 ;
     RECT  30.024 8.341 31.008 8.483 ;
     RECT  18.912 8.389 20.016 37.667 ;
     RECT  29.712 8.483 31.008 14.819 ;
     RECT  51.528 8.483 53.28 8.725 ;
     RECT  46.248 8.533 47.472 8.771 ;
     RECT  38.76 8.579 39.792 9.107 ;
     RECT  49.128 8.579 50.496 8.627 ;
     RECT  49.032 8.627 50.496 9.971 ;
     RECT  41.016 8.723 42.096 8.771 ;
     RECT  51.96 8.725 53.28 8.771 ;
     RECT  53.832 8.725 55.056 8.819 ;
     RECT  22.68 8.771 23.856 9.155 ;
     RECT  40.776 8.771 42.096 9.829 ;
     RECT  46.248 8.771 47.568 9.059 ;
     RECT  47.928 8.963 48.96 9.347 ;
     RECT  22.32 9.059 22.656 9.155 ;
     RECT  38.76 9.107 39.984 9.587 ;
     RECT  22.32 9.155 23.856 9.203 ;
     RECT  22.32 9.203 24 9.589 ;
     RECT  47.592 9.347 49.008 9.971 ;
     RECT  44.376 9.587 45.6 10.163 ;
     RECT  21.624 9.589 24 9.973 ;
     RECT  79.32 9.731 80.4 10.019 ;
     RECT  21.624 9.973 22.8 10.547 ;
     RECT  22.824 9.973 24 11.123 ;
     RECT  40.776 10.019 42.288 10.115 ;
     RECT  81 12.517 82.08 13.477 ;
     RECT  82.104 12.517 83.4 13.667 ;
     RECT  81.384 13.667 83.4 15.013 ;
     RECT  82.296 15.013 83.4 16.259 ;
     RECT  78.312 24.133 79.296 25.477 ;
     RECT  82.056 24.277 83.4 25.139 ;
     RECT  78.312 30.229 79.632 31.955 ;
     RECT  79.656 31.861 80.736 31.955 ;
     RECT  82.152 33.013 83.184 34.259 ;
     RECT  78.312 33.541 79.344 34.355 ;
     RECT  82.152 34.259 83.4 34.835 ;
     RECT  78.312 34.355 79.368 34.885 ;
     RECT  78.312 34.885 79.584 37.283 ;
     RECT  81.384 37.429 82.512 37.477 ;
     RECT  82.2 40.499 83.184 40.547 ;
     RECT  82.2 40.547 83.28 40.595 ;
     RECT  82.2 40.595 83.4 41.063 ;
  END
END ot_hgi_qdq_transport_wslice
END LIBRARY
